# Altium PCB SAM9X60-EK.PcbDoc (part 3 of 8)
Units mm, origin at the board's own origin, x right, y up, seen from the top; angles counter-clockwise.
Board outline 150 x 125 mm, 4 copper layers (L1 - Top Layer, L2 - GND, L3 - PWR, L4 - Bottom Layer), stack 1.52 mm thick; 566 components, 500 nets, 2132 pads, 1038 vias.

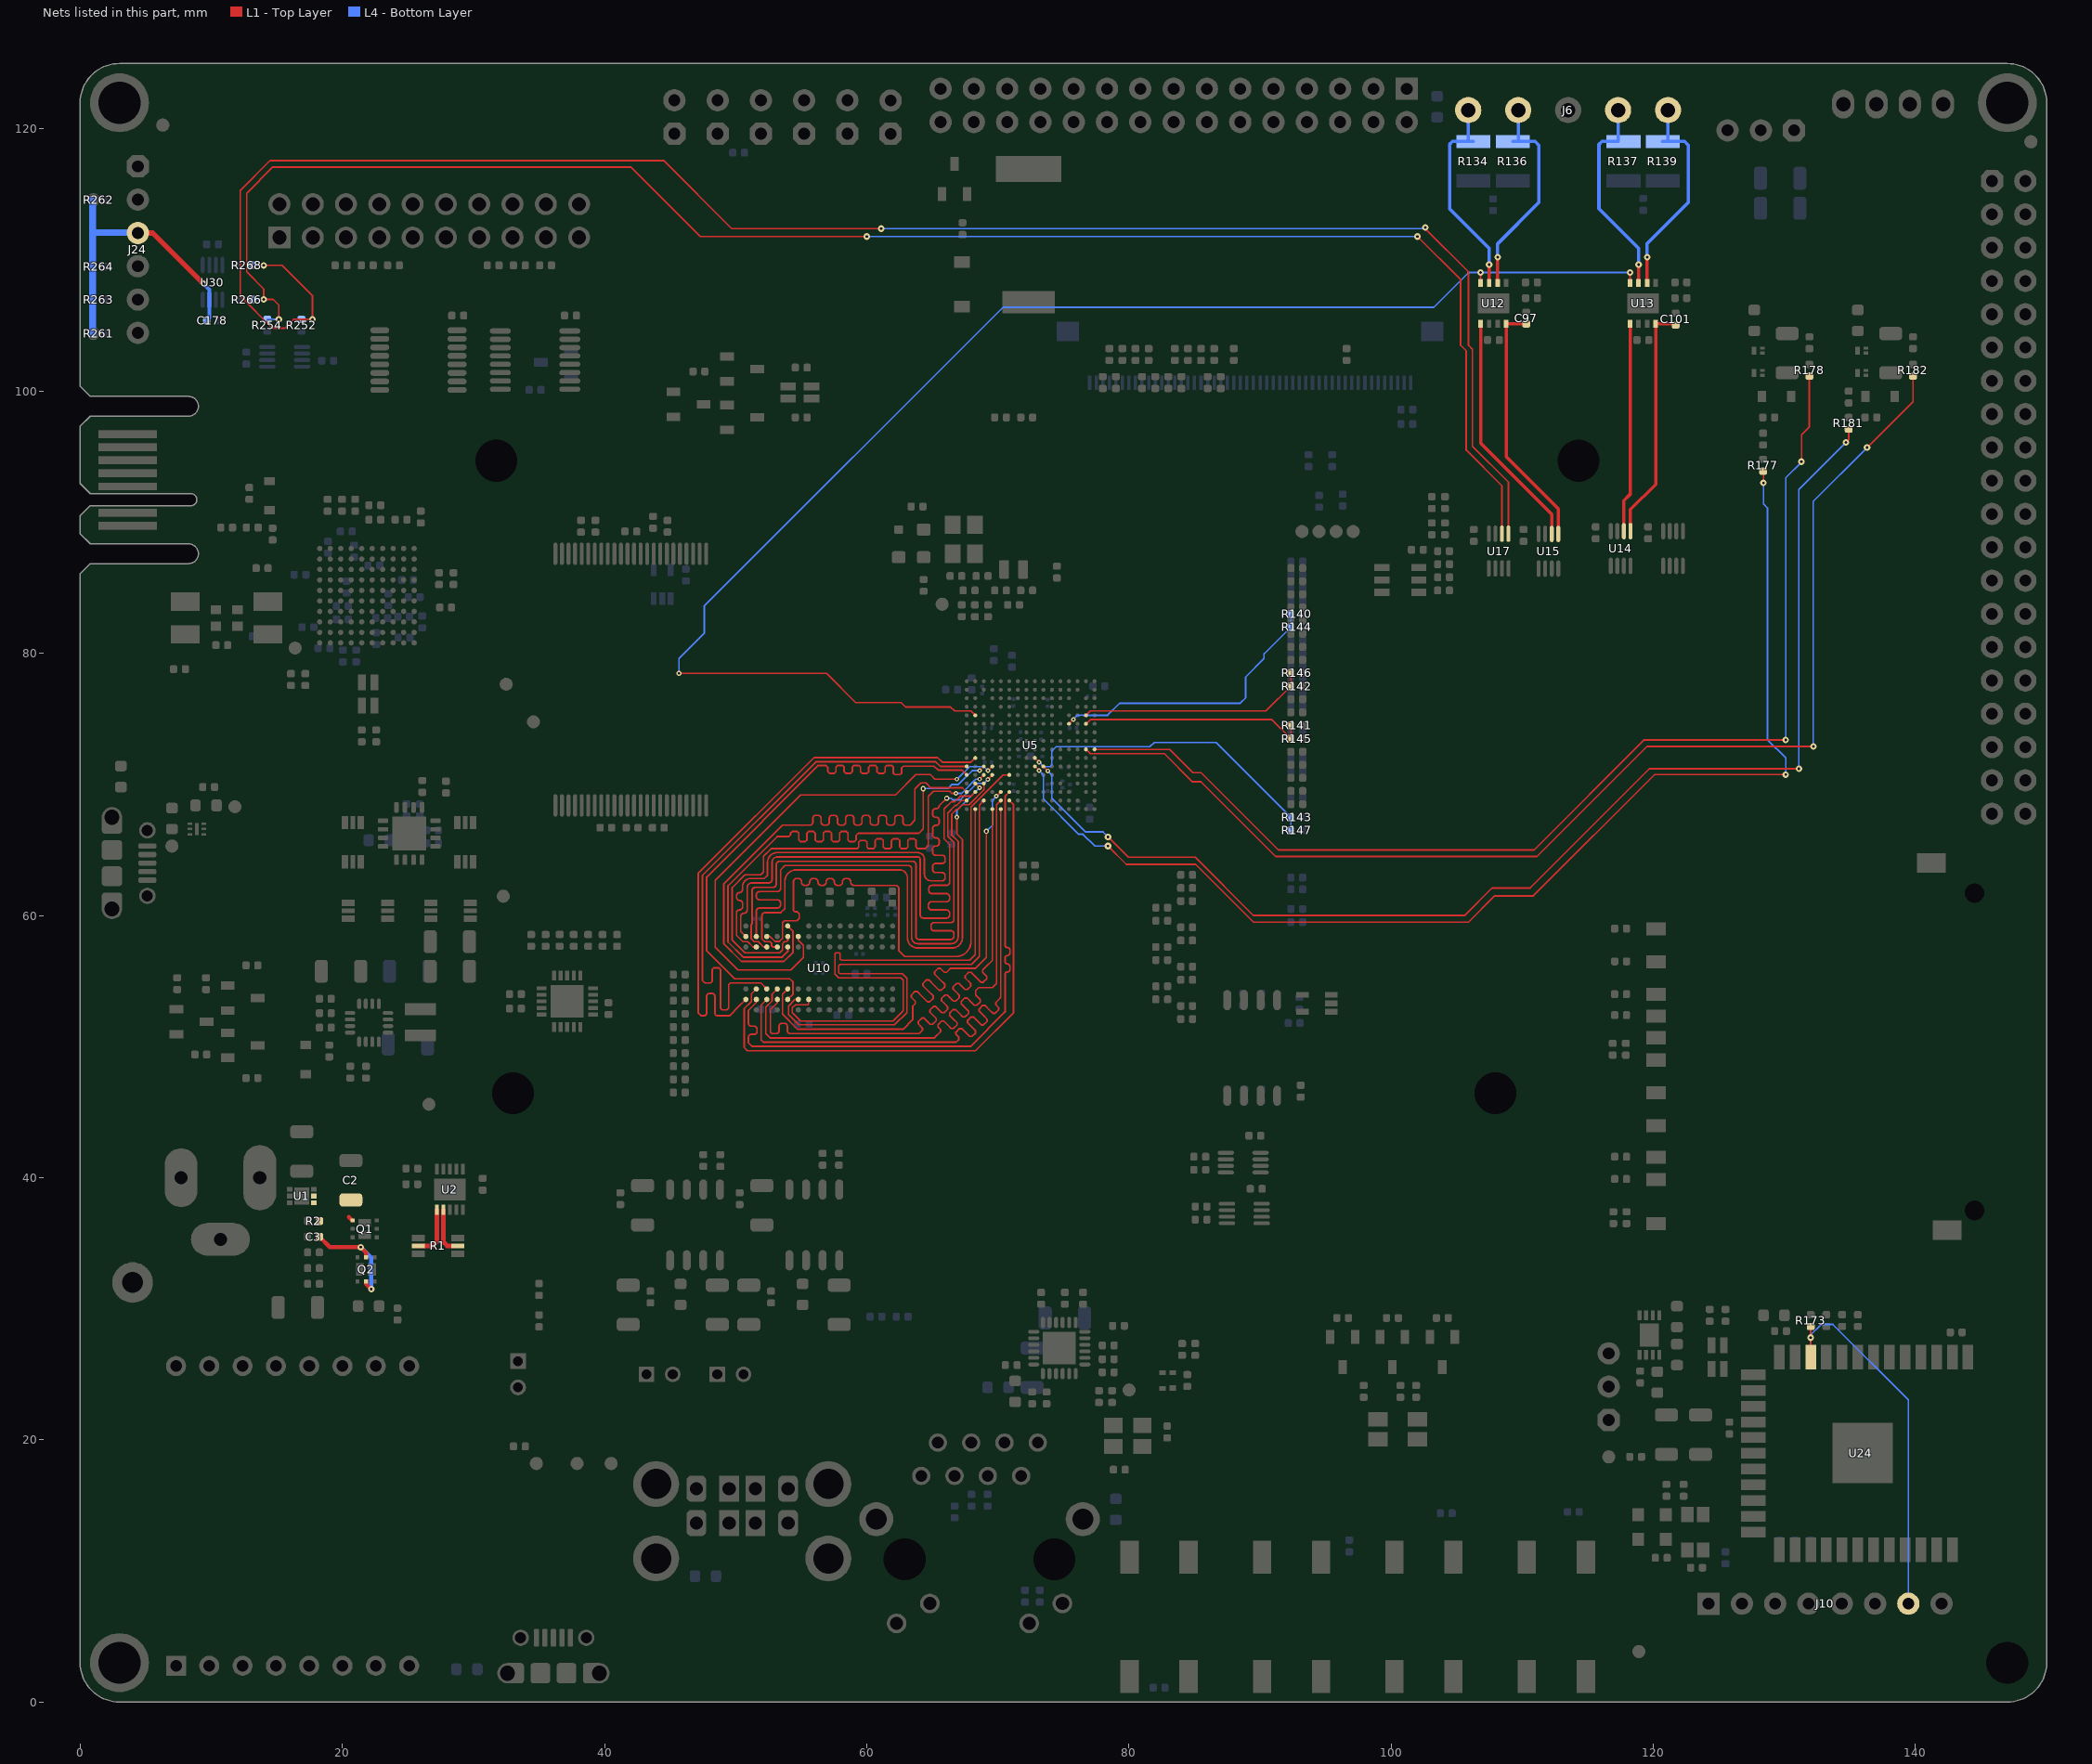
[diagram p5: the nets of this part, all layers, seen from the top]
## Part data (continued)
J12: library part CON0005, Current=6A, Manufacturer 1="Phoenix Contact", Manufacturer 2="Degson Electronics Co., Ltd.", Manufacturer Part Number 1=1725672, Manufacturer Part Number 2=DG308-2.54-04P-14-00A(H), Supplier Part Number 1=277-1275-ND, Voltage=63V
J14: library part SKT1042, Manufacturer 1="Sullins Connector Solutions", Manufacturer 2=Nextron, Manufacturer Part Number 1=PPTC081LFBN-RC, Manufacturer Part Number 2=R-212-0810-0071-000, Package="mikroBUS HOST", Supplier Part Number 1=S7006-ND
J15: library part CON1372, Current=0.5A, Manufacturer 1="Omron Electronics Inc-EMC Div", Manufacturer Part Number 1=XF2M-5015-1A, Supplier Part Number 1=OR732CT-ND
J16: library part CON0153, Manufacturer 1=Samtec, Manufacturer Part Number 1=TSW-120-07-G-D, Manufacturer Part Number 2=TSW-120-07-S-D
J17: library part CON1580, Manufacturer 1="Wurth Electronics Inc.", Manufacturer Part Number 1=61303021121, Supplier Part Number 1=732-5306-ND
J18: library part CON1674, "CON_PCB_MEC1-108-02-F-D-RA1-SL", Current=1.6A, Manufacturer 1="Samtec Inc.", Manufacturer Part Number 1=MEC1-108-02-F-D-RA1-SL, Supplier Part Number 1=SAM11473-ND
J23: library part CON1883, Current=3A, Manufacturer 1="On Shore Technology Inc.", Manufacturer Part Number 1=302-R201, Supplier Part Number 1=ED10536-ND, Voltage="HDR-2.54 Male 2x10"
J24: library part CON1106, Manufacturer 1=FCI, Manufacturer 3="Samtec Inc", Manufacturer 4=Nextron, Manufacturer Part Number 1=68000-106HLF, Manufacturer Part Number 2=68001-106HLF, Manufacturer Part Number 3=TSW-106-07-G-S, Manufacturer Part Number 4=R-211-0611-0021-400, Supplier Part Number 1=609-3249-ND
L1: library part IND1348, Manufacturer 1=TDK, Manufacturer 2="TDK Corporation", Manufacturer Part Number 1=MLP2520H2R2MT0S1, Operating Temperature="-40C to +125C", Package=1008, RMS Current=1.3A, Supplier Part Number 1=810-MLP2520H2R2MT0S1, Test Frequency=2MHz
LABEL1: library part 08-00126
LCD1: library part DISPLAY0025, Manufacturer 1="PDA INC", Manufacturer Part Number 1=TM5000B, Operating Temperature="0C to +70C", Voltage=5V
LD1: library part DIODE1214, Forward Current="20mA, 20mA, 20mA", Manufacturer 1="Cree Inc", Manufacturer 2="Cree Inc.", Manufacturer Part Number 1=CLV1A-FKB-CK1N1G1BB7R4S3, Manufacturer Part Number 2=CLV1A-FKB-CK1VW1DE1BB7C3C3, Operating Temperature="-40C - +100C", Package=4-PLCC, Power="130mW, 100mW, 100mW", Reverse Current=10uA, Reverse Voltage=5V, Supplier Part Number 1=CLV1A-FKB-CK1N1G1BB7R4S3CT-ND
PAD1 PAD2 PAD3 PAD4: library part MECH0185, Manufacturer 1="Essentra Components", Manufacturer Part Number 1=RBS-35, Supplier Part Number 1=RPC1620-ND
Q1 Q2: library part TRA1245, Current=-4.5A, Drain to Source Voltage=-20V, Gate to Source Voltage=900mV, Manufacturer 1="Vishay Siliconix", Operating Temperature="-55C to +150C", Package=SC70-6L, Power=7.8W, Supplier Part Number 1=SIA923AEDJ-T1-GE3CT-ND
Q3 Q4 Q5 Q10 Q11 Q12 Q13 Q14 Q15: library part MIC7420, "Transistor MOS", Manufacturer 1="Microchip Technology", Manufacturer Part Number 1=TN2106K1-G
Q6 Q8: library part TRA1229, "Transistor MOS", Current=1.4A, Drain to Source Voltage=20V, Gate to Source Voltage=8V, Manufacturer 1="Toshiba Semiconductor and Storage", Manufacturer Part Number 1=SSM3J56ACT,L3F, Operating Temperature="-55C to +150C", Package=SOT-883, Power=0.5W, Supplier Part Number 1=SSM3J56ACTL3FCT-ND
Q7 Q9: library part TRA1230, "Transistor MOS", Current=1.4A, Drain to Source Voltage=20V, Gate to Source Voltage=4.5V, Manufacturer 1="Toshiba Semiconductor and Storage", Manufacturer Part Number 1=SSM3K56ACT,L3F, Operating Temperature="-55C to +150C", Package=SOT-883, Power=0.5W, Supplier Part Number 1=SSM3K56ACTL3FCT-ND
Q16: library part TRA1223, "Transistor MOS", Current=230mA, Drain to Source Voltage=60V, Gate to Source Voltage=20V, Manufacturer 1="Infineon Technologies", Manufacturer Part Number 1=BSS138NH6327XTSA2, Operating Temperature="-55C to +150C", Package=SOT23-3, Power=0.36W, Supplier Part Number 1=BSS138NH6327XTSA2CT-ND
R1: library part RSMT1231, "Shunt", Current=5A, Manufacturer 1=Yageo, Manufacturer Part Number 1=PF1206FRF070R01L, Operating Temperature="-55C to +155C", Package=1206, Power=0.25W, Supplier Part Number 1=311-0.01AJCT-ND, Temperature Coeffcient=100ppm/C, Tolerance=1%, Voltage=50mV
R2 R3 R5 R15 R16 R17 R29 R34 R35 R36 R37 R47 R48 R49 R148 R162 R163 R164 R165 R166 R167 R189 R194 R204 R245 R256 R257 R258 R259 R260 R261 R262 R263 R264 R270: library part RES2196, Manufacturer 1=Yageo, Manufacturer Part Number 1=RC0402JR-07100KL, Package=0402, Power=1/16W, Supplier Part Number 1=311-100KJRCT-ND, Temperature Coeffcient=100ppm/C, Tolerance=5%
R4 R12 R13 R19 R33 R97 R98 R99 R100 R101 R102 R103 R104 R105 R106 R107 R108 R109 R110 R111 R112 R113 R114 R115 R116 R117 R118 R127 R129 R152 R153 R154 R155 R168 R176 R179 R180 R183 R186 R196 R202 R207 R232 R237 R241 R250: library part RSMT0439, Manufacturer 1=Vishay, Manufacturer 2=Yageo, Manufacturer Part Number 1=CRCW040210K0JNED, Manufacturer Part Number 2=RC0402JR-0710KL, Operating Temperature="-55C to +155C", Package=0402, Power=1/16W, Supplier Part Number 1=541-10KJCT-ND, Temperature Coeffcient=100ppm/C, Tolerance=5%, Voltage=50V
R6 R20 R185 R190 R191 R192 R195 R197 R200 R206 R234 R235 R238 R265: library part RES1587, Manufacturer 1=Yageo, Manufacturer Part Number 1=RC0402FR-07100RL, Operating Temperature="-55C to +155C", Package=0402, Power=1/16W, Supplier Part Number 1=311-100LRCT-ND, Temperature Coeffcient=100ppm/C, Tolerance=1%, Voltage=50V
R7 R8 R9 R10: library part RSMT1231, "Shunt", Current=5A, Manufacturer 1=Yageo, Manufacturer Part Number 1=PF1206FRF070R01L, Operating Temperature="-55C to +155C", Package=1206, Power=1/4W, Supplier Part Number 1=311-0.01AJCT-ND, Temperature Coeffcient=100ppm/C, Tolerance=1%, Voltage=50mV
R11 R119: library part RSMT1238, Current=1A, Manufacturer 1=Yageo, Manufacturer Part Number 1=RC0402FR-0720KL, Operating Temperature="-55C to +155C", Package=0402, Power=1/16, Supplier Part Number 1=311-20.0KLRCT-ND, Temperature Coeffcient=100ppm/C, Tolerance=1%, Voltage=100V
R14: library part RSMT0440, Manufacturer 1=Yageo, Manufacturer Part Number 1=9C06031A8451FKHFT, Operating Temperature="-55C to +155C", Package=0603, Power=1/10W, Supplier Part Number 1=311-8.45KHCT-ND, Temperature Coeffcient=100ppm/C, Tolerance=1%, Voltage=50V
R18 R122 R123 R160 R161 R187 R188 R199 R201 R246 R249: library part RSMT0316, Manufacturer 1=Panasonic, Manufacturer Part Number 1=ERJ-2GEJ102X, Operating Temperature="-55C to +155C", Package=0402, Power=1/16W, Supplier Part Number 1=P1.0KJCT-ND, Temperature Coeffcient=200ppm/C, Tolerance=5%, Voltage=50V
R21 R24: library part RES1019, Manufacturer 1=Yageo, Manufacturer Part Number 1=RC0402JR-071ML, Operating Temperature="-55C to +155C", Package=0402, Power=1/16W, Supplier Part Number 1=311-1.0MJRCT-ND, Temperature Coeffcient=100ppm/C, Tolerance=5%, Voltage=50V
R22 R26 R27 R28 R30 R60 R63 R65 R66 R91 R126 R128 R130 R131 R133 R135 R138 R169 R170 R171 R173 R174 R177 R178 R181 R182 R208 R209 R210 R211 R214 R217 R233 R239: library part RSMT1040, Manufacturer 1=Yageo, Manufacturer Part Number 1=RC0402JR-070RL, Operating Temperature="-55C to +155C", Package=0402, Power=1/16W, Supplier Part Number 1=311-0.0JRCT-ND
R23: library part RES1505, Manufacturer 1="Vishay Dale", Manufacturer Part Number 1=CRCW04025K62FKED, Operating Temperature="-55C to +155C", Package=0402, Power=1/16W, Supplier Part Number 1=541-5.62KLTR-ND, Temperature Coeffcient=100ppm/C, Tolerance=1%, Voltage=50V
R25: library part RES2180, Manufacturer 1="Vishay Dale", Manufacturer Part Number 1=CRCW020110R0FNED, Operating Temperature="-55C to +155C", Package=0201, Power=1/20W, Supplier Part Number 1=541-10.0ABCT-ND, Temperature Coeffcient=200ppm/C, Tolerance=1%
R31 R32 R38 R39 R40 R41 R42 R43 R44 R45 R46 R50 R51 R52 R53 R54 R55 R56 R57 R58 R59 R64 R67 R68 R69 R70 R71 R72 R73 R74 R75 R76 R77 R78 R79 R80 R81 R82 R85 R86 R87 R88 R89 R90 R92 R93 R94 R95 R96 R140 R141 R142 R143 R144 R145 R146 R147 R156 R157 R158 R159 R212 R213 R215 R216 R218 R219 R220 R221 R222 R223 R224 R225 R226 R227 R228 R229 R230 R231 R252 R254 R266 R268: library part RES1474, Manufacturer 1="Panasonic Electronic Components", Manufacturer Part Number 1=ERJ-2RKF22R0X, Operating Temperature="-55C to +155C", Package=0402, Power=1/10W, Supplier Part Number 1=P22.0LCT-ND, Temperature Coeffcient=100ppm/C, Tolerance=1%
R61 R62 R83 R84 R203: library part RES1020, Manufacturer 1="Vishay Dale", Manufacturer Part Number 1=CRCW04022K20JNED, Operating Temperature="-55C to +155C", Package=0402, Power=1/16W, Supplier Part Number 1=541-2.2KJCT-ND, Temperature Coeffcient=200ppm/C, Tolerance=5%, Voltage=50V
R120 R121: library part RES1519, Manufacturer 1="Panasonic Electronic Components", Manufacturer Part Number 1=ERJ-1GEF4701C, Operating Temperature="-55C to +125C", Package=0201, Power=1/20W, Supplier Part Number 1=P4.70KABTR-ND, Temperature Coeffcient=200ppm/C, Tolerance=1%, Voltage=25V
R124: library part RES1731, Manufacturer 1=Yageo, Manufacturer Part Number 1=RC0402FR-076K49L, Operating Temperature="-55C to +155C", Package=0402, Power=1/16W, Supplier Part Number 1=311-6.49KLRCT-ND, Temperature Coeffcient=100ppm/C, Tolerance=1%, Voltage=50V
R125: library part RSMT1037, Manufacturer 1=Yageo, Manufacturer Part Number 1=RC0402JR-07470RL, Operating Temperature="-55C to +155C", Package=0402, Power=1/16W, Supplier Part Number 1=311-470JRCT-ND, Temperature Coeffcient=100ppm/C, Tolerance=5%, Voltage=50V
R132 R149 R172 R175 R251: library part RSMT1243, Current=1A, Manufacturer 1=Yageo, Manufacturer Part Number 1=RC0402FR-0751RL, Operating Temperature="-55C to +155C", Package=0402, Power=1/16W, Supplier Part Number 1=311-51.0LRCT-ND, Temperature Coeffcient=100ppm/C, Tolerance=1%, Voltage=100V
R134 R136 R137 R139: library part RSMT1222, Current=5.56A, Manufacturer 1=Yageo, Manufacturer Part Number 1=RC1210FR-0762RL, Operating Temperature="-55C to +155C", Package=1210, Power=1/2W, Supplier Part Number 1=603-RC1210FR-0762RL, Temperature Coeffcient=100PPM/C, Tolerance=1%, Voltage=200V
R150: library part RES1424, Manufacturer 1=Panasonic, Manufacturer Part Number 1=ERJ-2RKF2003X, Operating Temperature="-55C to +125C", Package=0402, Power=1/10W, Supplier Part Number 1=P200KLCT-ND, Temperature Coeffcient=100ppm/C, Tolerance=1%, Voltage=50V
R236 R242 R243 R244: library part RSMT1167, Manufacturer 1="Vishay Dale", Manufacturer Part Number 1=CRCW0402150RFKED, Supplier Part Number 1=541-150LCT-ND
R240: library part RSMT1211, Manufacturer 1="Vishay Dale", Manufacturer Part Number 1=CRCW04026K80FKED, Operating Temperature="-55C to +155C", Package=0402, Power=1/16W, Supplier Part Number 1=541-6.80KLCT-ND, Temperature Coeffcient=100ppm/C, Tolerance=1%, Voltage=50V
R247 R248: library part RES1800, Manufacturer 1=Yageo, Manufacturer 2=Digi-Key, Manufacturer Part Number 1=RC0402FR-0739RL, Manufacturer Part Number 2=311-39.0LRCT-ND, Operating Temperature="-55°C ~ 155°C", Package=0402, Power=1/16W, Tolerance=1%
SW1 SW2 SW3 SW4: library part SWITCH0003, "Switch", Current=50mA, Manufacturer 1=E-Switch, Manufacturer 4=OMRON, Manufacturer 8="Switech Electronics Co. Ltd", Manufacturer Part Number 1=TL3301NF260QG/TR, Manufacturer Part Number 2=TL3301NF260QG, Manufacturer Part Number 3=TL3301NF160QG/TR, Manufacturer Part Number 4=B3S-1000P, Manufacturer Part Number 5=B3S-1000, Manufacturer Part Number 6=B3S-1002P, Manufacturer Part Number 7=B3S-1002, Manufacturer Part Number 8=TS2A-043C-G9, Operating Temperature="-20C to +70C", Supplier Part Number 1=EG1868CT-ND, Voltage=12V
TP1: library part MISC0025, "Test Point", Manufacturer 1=Keystone, Manufacturer Part Number 1=5011, Supplier Part Number 1=36-5011-ND
TP2 TP4 TP5 TP6 TP7 TP8 TP9 TP10 TP11 VBUS_JLINK VBUS_USBA VBUS_USBB VBUS_USBC VDD_3V3 VDD_3V3_3U VDD_MAIN_5V VDD_WILC VDDCORE VDDIOM: library part TEST-POINT, "Test Point pad 1.00mm"
U1: library part IC1481, Manufacturer 1="ON Semiconductor", Manufacturer Part Number 1=NCP349MNAETBG, Operating Temperature="-40C to 85C", Package=DFN-6, Supplier Part Number 1=NCP349MNAETBGOSCT-ND
U2: library part MIC6142, Manufacturer 1="Microchip Technology", Manufacturer Part Number 1=PAC1710-1-AIA-TR, Supplier Part Number 1=PAC1710-1-AIA-CT-ND
U3: library part MIC7858, Manufacturer 1="Microchip Technology", Manufacturer Part Number 1=MIC2800-G8SYML, Supplier Part Number 1=MIC2800-G8SYML-TRCT-ND
U4: library part MIC7010, Manufacturer 1="Microchip Technology", Manufacturer Part Number 1=PAC1934-I/JQ
U5: library part MIC8772, "SAM9X60 MPU 600MHz ARM926EJ-S TFBGA-228", Manufacturer 1=Microchip, Manufacturer Part Number 1=SAM9X60-V/DWB, PackageType=TFBGA, PackageWidth=11x11x1.2mm, TempRange=Various
U6: library part MIC2806, "I/O Expander", IOVoltageTolerant=VDD, Manufacturer 1=Microchip, Manufacturer Part Number 1=MCP23008T-E/ML, Manufacturer Part Number 2=MCP23008-E/ML, OperatingVoltageMax=5.5, OperatingVoltageMin=1.8, PackageType=QFN, PackageWidth=4x4x0.9mm, PinCurrent=25, TempRange="-40C to +125C", TotalCurrent=160
U7: library part MIC7407, Manufacturer 1="Microchip Technology", Manufacturer Part Number 1=24AA025E48T-I/OT, MaxClockFreq="400 kHz", OpVoltMax=5.5, OpVoltMin=1.7, PackageType=SOT-23, Supplier Part Number 1=24AA025E48T-I/OTCT-ND, TempRange="-40C to +85C"
U8: library part MIC6216, "SQI Serial Flash", Manufacturer 1="Microchip Technology", Manufacturer Part Number 1=SST26VF064B-104I/SM, MaxClockFreq="104 MHz", OpVoltMax=3,6, OpVoltMin=2,3, PackageType=SOIJ, PackageWidth=.208in, TempRange="-40C to +85C"
U9: library part IC1477, Manufacturer 1="Micron Technology Inc.", Manufacturer Part Number 1="MT29F4G08ABAEAWP:E TR", Operating Temperature="0C to +70C", Package=TSOP-48, Supplier Part Number 1=557-1674-1-ND
U10: library part IC1476, "2Gb DDR2-800 SDRAM, 128Mb x 16", Manufacturer 1="Winbond Electronics", Manufacturer Part Number 1=W972GG6KB-25, Operating Temperature="0C to +85C", Package=WBGA-84
U11: library part MIC7404, Manufacturer 1="Microchip Technology", Manufacturer Part Number 1=KSZ8081RNAIA-TR, Supplier Part Number 1=576-4174-1-ND
U12 U13: library part MIC7856, Manufacturer 1="Microchip Technology", Manufacturer Part Number 1=MCP2542FDT-E/MF, OperatingCurrentMax=10, OperatingVoltageMax=5.5, OperatingVoltageMin=4.5, PackageType=DFN, PackageWidth=3x3x0.9mm, StandbyCurrentMax=15, Supplier Part Number 1=MCP2542FDT-E/MFCT-ND, TempRange="-40C to +125C", TransientVoltage="-150 to +100"
U14 U15 U21: library part IC1512, "BUFFER DL TRI-ST NON-INV", Manufacturer 1="ON Semiconductor", Manufacturer Part Number 1=NL27WZ125USG, Operating Temperature="-55C to +125C", Package=US-8, Supplier Part Number 1=NL27WZ125USGOSCT-ND
U16 U17 U23: library part IC1514, "BUFFER DL TRI-ST NON-INV", Manufacturer 1="ON Semiconductor", Manufacturer Part Number 1=NL27WZ126USG, Operating Temperature="-55C to +125C", Package=US-8, Supplier Part Number 1=NL27WZ126USGOSCT-ND
U19 U20: library part MIC7234, Manufacturer 1="Microchip Technology", Supplier Part Number 1=576-1057-ND
U22: library part MIC2599, "LDO", Manufacturer 1=Microchip, Manufacturer Part Number 1=MCP1725T-3302E/MC, Manufacturer Part Number 2=MCP1725-3302E/MC, PackageType=DFN, PackageWidth=2x3x0.9mm, TempRange="-40C to +125C"
U24: library part MIC7405, FrequencyRange="2.412-2.472 MHz", Manufacturer 1="Microchip Technology", Manufacturer Part Number 1=ATWILC3000-MR110CA, PowerRX="84mA (802.11n MCS7)", PowerTX="253mA (802.11n MCS7)", RfPower=0, Supplier Part Number 1=ATWILC3000-MR110CA-ND
U25 U26: library part IC1252, "Single  Non-Inverting 3-State  buffer", Manufacturer 1="Diodes Incorporated", Manufacturer Part Number 1=74AHC1G126SE-7, Operating Temperature="-40°C ~ 125°C", Package=SC-70-5, Supplier Part Number 1=621-74AHC1G126SE-7
U27: library part MIC7470, Manufacturer 1="Microchip Technology", Manufacturer Part Number 1=ATSAM3U4CA-CU, PackageType=TFBGA, PackageWidth=9x9x1.2mm, Supplier Part Number 1=ATSAM3U4CA-CU-ND, TempRange="-40C to +85C"
U28: library part MIC6905, Manufacturer 1="Microchip Technology", Manufacturer Part Number 1=MIC5528-3.3YMT-TR, PackageType=UDFN, PackageWidth=1.2x1.2x0.6mm, Supplier Part Number 1=576-4766-1-ND, TempRange="-40C to +125C"
U29 U30: library part IC1128, "Level Shifter", Manufacturer 1="Texas Instruments", Manufacturer Part Number 1=TXS0102DCUR, Operating Temperature="-40C to +85C", Package=US-8, Supplier Part Number 1=296-21931-1-ND
U31: library part IC1517, Manufacturer 1="IDT, Integrated Device Technology Inc", Manufacturer Part Number 1=QS3VH257PAG, Operating Temperature="-40C to +85C", Package=TSSOP-16, Supplier Part Number 1=800-2205-ND
U32: library part IC1516, Manufacturer 1="IDT, Integrated Device Technology Inc", Manufacturer Part Number 1=QS3VH125QG, Operating Temperature="-40C to +85C", Package=QSOP-16, Supplier Part Number 1=800-2199-ND
Y1: library part OSC1047, "Crystal", Load Capacitance=18pF, Manufacturer 1="Abracon Corporation", Manufacturer Part Number 1=ABM8G-24.000MHZ-18-D2Y-T, Package=ABM8G, Supplier Part Number 1=535-10273-1-ND
Y2: library part OSC1063, "Crystal", Manufacturer 1="Abracon LLC", Manufacturer Part Number 1=ABS06-32.768KHZ-T, Supplier Part Number 1=535-10104-1-ND
Y3: library part MIC7861, Manufacturer 1="Microchip Technology", Manufacturer Part Number 1=DSC1001CI5-024.0000, Supplier Part Number 1=576-4617-ND
Y5: library part OSC1159, "Crystal", Load Capacitance=20pF, Manufacturer 1="ECS Inc.", Manufacturer Part Number 1=ECS-250-20-33-CKM-TR, Operating Temperature="-20C to +70C", Package=L3.2W2.5H0.8, Supplier Part Number 1=XC1817CT-ND, Tolerance=10ppm
Y6: library part MIC8785, Manufacturer 1="Microchip Technology Inc", Manufacturer Part Number 1=DSC6102HI2B-025.000
Y7: library part OSC1187, Manufacturer 1="Abracon LLC", Manufacturer Part Number 1=ASH7KW-32.768KHZ-L-T, Operating Temperature="-40C to +85C", Package=DFN-4, Supplier Part Number 1=535-12059-1-ND, Supply Current=1.8uA, Tolerance=20ppm, Voltage=1.2-5.5V
Y8: library part MIC7476, Manufacturer 1="Microchip Technology", Manufacturer Part Number 1=DSC6083CE2A-032K768, Supplier Part Number 1=DSC6083CE2A-032K768-ND
Y9: library part OSC1155, "Crystal", Load Capacitance=16pF, Manufacturer 1="IQD Frequency Products", Manufacturer Part Number 1=LFXTAL026384Reel, Operating Temperature="-20C to +70C", Package="7.5mm X 5mm", Supplier Part Number 1=449-LFXTAL026384REEL, Supply Current=-, Tolerance=30ppm
Y10: library part MIC7210, Manufacturer 1="Microchip Technology Inc", Manufacturer Part Number 1=DSC6011JI1A-012.0000

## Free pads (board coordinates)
  round 4.5 hole 3.2 unplated mask+0.2: 0(3,3) 0(3,122) 0(147,122)
  round 0 hole 3.2 unplated mask+0.2: 0(147,3)
  round 1 smd paste-1 mask+0.5: 1.00mm(6.3,120.3) 1.00mm(118.9,3.85) 1.00mm(148.8,119.025)
  round 1 smd far side paste-1 mask+0.5: 1.00mm(6.3,120.3) 1.00mm(118.9,3.85) 1.00mm(148.8,119.025)

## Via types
v1: diameter 0.5, hole 0.2, L1 - Top Layer to L4 - Bottom Layer, tented both sides, 483 vias
v2: diameter 0.5, hole 0.2, L1 - Top Layer to L4 - Bottom Layer, 268 vias
v3: diameter 0.4, hole 0.2, L1 - Top Layer to L4 - Bottom Layer, tented both sides, 145 vias
v4: diameter 0.35, hole 0.15, L1 - Top Layer to L4 - Bottom Layer, tented both sides, 121 vias
v5: diameter 0.55, hole 0.3, L1 - Top Layer to L4 - Bottom Layer, tented bottom, 16 vias
v6: diameter 0.559, hole 0.305, L1 - Top Layer to L4 - Bottom Layer, 5 vias

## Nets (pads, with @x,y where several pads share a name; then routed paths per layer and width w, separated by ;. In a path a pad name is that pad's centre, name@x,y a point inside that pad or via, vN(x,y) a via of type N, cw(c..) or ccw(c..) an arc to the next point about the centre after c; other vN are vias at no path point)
5V_FTDI: C178.2 J24.3 R261.1 R262.1 R263.2 R264.2 U30.7 | length 23.3
  L1 - Top Layer w0.4: J24.3@4.4,112.07 5.53,112.07 v1(9.4,108.2)
  L4 - Bottom Layer w0.3: v1(9.4,108.2) 9.85,107.75 U30.7@9.85,106.975 9.85,105.6 C178.2@9.65,105.4
  L4 - Bottom Layer w0.5: R261.1@0.95,104.4 R263.2@0.95,107 R264.2@0.95,109.5 0.95,112.1 ; R262.1@0.95,114.6 0.95,112.1 ; J24.3@4.4,112.07 4.37,112.1 0.95,112.1
5V_N: R1.4 U2.2 | length 3.3
  L1 - Top Layer w0.35: U2.2@27.7,37.55 27.7,35.1 28,34.8 R1.4@28.4,34.8
5V_P: R1.3 U2.1 | length 4
  L1 - Top Layer w0.35: R1.3@25.8,34.8 26.9,34.8 27.2,35.1 U2.1@27.2,37.55
CAN0_H: J6.1 R134.2 U12.7 | length 16.1
  L1 - Top Layer w0.25: U12.7@107.475,108.25 v2(107.475,109.65)
  L4 - Bottom Layer w0.25: J6.1@105.88,121.444 R134.2@105.88,119.05 ; R134.2@106.275,119.05 R134.2@105.88,119.05 ; v2(107.475,109.65) 107.475,110.9 104.45,113.925 104.45,118.825 104.675,119.05 R134.2@105.88,119.05
CAN0_L: J6.2 R136.1 U12.6 | length 16.3
  L1 - Top Layer w0.25: U12.6@108.125,108.25 v2(108.125,110.225)
  L4 - Bottom Layer w0.25: v2(108.125,110.225) 108.125,111.25 111.25,114.375 111.25,118.775 110.975,119.05 R136.1@109.275,119.05 ; R136.1@109.69,119.05 J6.2@109.69,121.444
CAN0_RX: C97.2 U12.4 U15.5 | length 19.2
  L1 - Top Layer w0.25: C97.2@110.3,105.125 110.275,105.15 U12.4@108.775,105.15 108.775,95 112.75,91.025 U15.5@112.75,89.115
CAN0_TX: U12.1 U15.6 | length 18.3
  L1 - Top Layer w0.25: U12.1@106.825,105.15 106.825,96.025 112.25,90.6 U15.6@112.25,89.115
CAN1_H: J6.4 R137.2 U13.7 | length 15.7
  L1 - Top Layer w0.25: U13.7@118.875,108.25 v2(118.875,109.65)
  L4 - Bottom Layer w0.25: R137.2@117.28,119.05 116.075,119.05 115.85,118.825 115.85,113.925 118.875,110.9 v2(118.875,109.65) ; R137.2@117.31,119.05 J6.4@117.31,121.444
CAN1_L: J6.5 R139.1 U13.6 | length 16.3
  L1 - Top Layer w0.25: U13.6@119.525,108.25 v2(119.525,110.225)
  L4 - Bottom Layer w0.25: v2(119.525,110.225) 119.525,111.25 122.65,114.375 122.65,118.775 122.375,119.05 R139.1@120.675,119.05 ; R139.1@121.12,119.05 J6.5@121.12,121.444
CAN1_RX: C101.2 U13.4 U14.5 | length 18.2
  L1 - Top Layer w0.25: U14.5@118.25,89.325 118.25,90.975 120.175,92.9 U13.4@120.175,105.15 121.6,105.15 C101.2@121.7,105.05
CAN1_TX: U13.1 U14.6 | length 16
  L1 - Top Layer w0.25: U14.6@117.75,89.325 117.75,91.65 118.225,92.125 U13.1@118.225,105.15
CAN/DBGU_RX_PA09: R143.2 R147.2 U5.G8 | length 24.5
  L1 - Top Layer w0.125: U5.G8@72.825,72.025 v4(73.15,71.7)
  L4 - Bottom Layer w0.1: v4(73.15,71.7) 73.475,71.375 74,71.375 74.125,71.5 74.125,72.55 ; 74.45,72.875 81.6,72.875 81.925,73.2
  L4 - Bottom Layer w0.125: 74.125,72.55 74.45,72.875 ; 81.925,73.2 86.65,73.2 R143.2@92.35,67.5 R147.2@92.35,66.5
CAN/DBGU_TX_PA10: R141.2 R145.2 U5.L2 | length 17.4
  L1 - Top Layer w0.125: U5.L2@76.725,74.625 77.047,74.947 90.903,74.947 R145.2@92.35,73.5 R141.2@92.35,74.5
CAN/FLEXCOM_RX_PA06: R142.2 R146.2 U5.M2 | length 17.5
  L1 - Top Layer w0.125: U5.M2@76.725,75.275 77.05,75.6 90.45,75.6 R142.2@92.35,77.5 R146.2@92.35,78.5
CAN/FLEXCOM_TX_PA05: R140.2 R144.2 U5.L4 | length 22.2
  L1 - Top Layer w0.125: U5.L4@75.425,74.625 v4(75.75,74.95)
  L4 - Bottom Layer w0.1: 76.275,75.275 76.491,75.275
  L4 - Bottom Layer w0.125: v4(75.75,74.95) 76.075,75.275 76.275,75.275 ; 76.491,75.275 78.375,75.275 79.3,76.2 88.5,76.2 88.9,76.6 88.9,78.2 90.3,79.6 90.3,80 90.35,80 R144.2@92.35,82 R140.2@92.35,83
CAN_STBY_PD21: U5.M15 U12.8 U13.8 | length 112.6
  L1 - Top Layer w0.125: v3(45.675,78.475) 56.925,78.475 59.15,76.25 62.625,76.25 62.975,75.9 66.4,75.9 66.7,75.6 67.95,75.6 U5.M15@68.275,75.275 ; U12.8@106.825,108.25 v2(106.825,109.05) ; U13.8@118.225,108.25 v2(118.225,109.05)
  L4 - Bottom Layer w0.125: v3(45.675,78.475) 45.675,79.6 47.6,81.525 47.6,83.6 70.4,106.4 103.25,106.4 105.9,109.05 v2(106.825,109.05) v2(118.225,109.05)
CLASSD_L0_PA24: R177.1 U5.F8 | length 91.7
  L1 - Top Layer w0.125: U5.F8@72.825,71.375 72.829,71.375 v4(73.143,71.061) ; v1(78.4,65.3) 79.8,63.9 85.1,63.9 89.5,59.5 105.9,59.5 107.9,61.5 110.849,61.5 120.098,70.749 v2(130.1,70.749) ; R177.1@128.375,93.9 128.4,93.875 v2(128.4,93)
  L4 - Bottom Layer w0.1: 73.475,68.9 73.475,70.729
  L4 - Bottom Layer w0.125: v4(73.143,71.061) 73.475,70.729 ; 73.475,68.9 76.175,66.2 76.5,66.2 77.4,65.3 v1(78.4,65.3) ; v2@128.5,92.9 128.4,92.8 128.4,91.4 128.7,91.1 128.7,73.425 130.1,72.025 v2(130.1,70.749)
CLASSD_L1_PA25: R178.1 U5.H1 | length 87.9
  L1 - Top Layer w0.125: U5.H1@77.375,72.675 83.1,72.675 84.875,70.9 85.5,70.9 91.4,65 110.9,65 119.3,73.4 v2(130.1,73.4) ; v2(131.3,94.625) 131.3,96.675 131.9,97.275 R178.1@131.9,101.15
  L4 - Bottom Layer w0.125: v2(130.1,73.4) 130.1,93.4 131.3,94.6 v2(131.3,94.625)
CLASSD_L2_PA26: R181.1 U5.F7 | length 95.5
  L1 - Top Layer w0.125: U5.F7@73.475,71.375 73.803,71.047 v4(73.803,71.036) ; v1(78.4,66) 79.95,64.45 85.05,64.45 89.5,60 105.6,60 107.7,62.1 110.6,62.1 119.7,71.2 v2(131.1,71.2) ; v2(134.7,96.1) 134.9,96.3 R181.1@134.9,97.1
  L4 - Bottom Layer w0.1: 74.125,68.95 74.125,70.714
  L4 - Bottom Layer w0.125: v4(73.803,71.036) 74.125,70.714 ; 74.125,68.95 76.7,66.375 78.025,66.375 v1(78.4,66) ; v2(131.1,71.2) 131.1,92.5 v2(134.7,96.1)
CLASSD_L3_PA27: R182.1 U5.H2 | length 93.7
  L1 - Top Layer w0.125: U5.H2@76.725,72.675 77.043,72.357 82.7,72.357 84.857,70.2 85.5,70.2 91.2,64.5 111.107,64.5 119.507,72.9 v2(132.2,72.9) ; v2(136.3,95.7) 139.8,99.2 R182.1@139.8,101.15
  L4 - Bottom Layer w0.125: v2(132.2,72.9) 132.2,91.6 v2(136.3,95.7)
CTS/SCL: J10.7 R173.1 U24.11 | length 28.3
  L1 - Top Layer w0.125: U24.11@132,26.31 v2(132,27.8) R173.1@132,28.65
  L4 - Bottom Layer w0.125: v2(132,27.8) 132,28 132.8,28.8 133.7,28.8 139.45,23.05 J10.7@139.45,7.5
DBGU_RX_PA09: R252.1 R268.1 U17.5 | length 142.6
  L1 - Top Layer w0.125: v1(14,109.6) 15.4,109.6 17.725,107.275 v1(17.725,105.475) 16.275,105.475 15.6,104.8 14.675,104.8 12.205,107.27 12.205,115.305 14.495,117.595 44.505,117.595 49.7,112.4 v1(61.1,112.4) ; v1(102.6,112.5) 102.6,112.4 105.9,109.1 105.9,103.5 106.2,103.2 106.2,95.8 108.95,93.05 U17.5@108.95,89.125
  L4 - Bottom Layer w0.125: R268.1@13.15,109.6 v1(14,109.6) ; R252.1@16.875,105.475 v1(17.725,105.475) ; v1(61.1,112.4) 102.5,112.4 v1(102.6,112.5)
DBGU_TX_PA10: R254.1 R266.1 U17.6 | length 130.5
  L1 - Top Layer w0.125: v1(15.15,105.475) 15.15,106.575 14.725,107 v1(14,107) 14,107.8 12.7,109.1 12.7,115.1 14.7,117.1 40.8,117.1 42,117.1 47.3,111.8 v1(60,111.8) ; v1(102,111.8) 105.3,108.5 105.3,103.494 105.725,103.069 105.725,95.496 108.45,92.771 U17.6@108.45,89.125
  L4 - Bottom Layer w0.125: R266.1@13.15,107 v1(14,107) ; R254.1@14.275,105.475 v1(15.15,105.475) ; v1(60,111.8) v1(102,111.8)
DC_5V: C2.1 C3.1 Q1.1 Q2.2 Q2.5 R2.2 U1.4 U1.5 | length 9.1
  L1 - Top Layer w0.3: C3.1@18.25,35.5 19.05,34.7 v1(21.4,34.7) 21.8,34.3 Q2.5@21.8,33.913 ; 20.5,37 20.75,36.75 Q1.1@20.788,36.75 ; Q2.2@21.8,32.087 21.8,31.9 v1(22.2,31.5)
  L4 - Bottom Layer w0.3: v1(21.4,34.7) 22.2,33.9 v1(22.2,31.5)
DDR_A2: U5.A13 U10.M8 | length 43
  L1 - Top Layer w0.125: U10.M8@53.175,53.6 53.175,53.35 52.65,52.825 52.65,51.1 52.75,51 53,51 53.094,51 ccw(c53.094,51.219) 53.313,51.219 53.313,51.562 cw(c53.531,51.562) 53.531,51.781 53.719,51.781 cw(c53.719,51.562) 53.938,51.562 53.938,51.219 ccw(c54.156,51.219) 54.156,51 54.425,51 64,51 64.113,51.112 64.245,51.245 64.245,51.422 63.935,51.732 63.935,51.909 64.2,52.174 64.377,52.174 64.775,51.775 64.846,51.705 65.023,51.705 65.288,51.97 65.288,52.147 65.217,52.217 64.819,52.616 64.819,52.793 65.084,53.058 65.261,53.058 65.659,52.659 65.73,52.589 65.907,52.589 66.172,52.854 66.172,53.031 66.101,53.101 65.702,53.5 65.702,53.677 65.968,53.942 66.144,53.942 66.543,53.543 66.614,53.472 66.791,53.472 67.056,53.738 67.056,53.914 66.985,53.985 66.586,54.384 66.586,54.561 66.851,54.826 67.028,54.826 67.427,54.427 67.498,54.356 67.675,54.356 67.94,54.622 67.94,54.798 67.869,54.869 67.513,55.225 67.513,55.402 67.778,55.667 67.955,55.667 68.311,55.311 68.71,54.912 68.887,54.912 69.152,55.177 69.152,55.354 68.841,55.664 68.841,55.841 69.087,56.087 69.575,56.575 69.575,67.265 ; 69.575,67.285 U5.A13@69.575,68.125
DDR_A3: U5.D15 U10.M3 | length 40.1
  L1 - Top Layer w0.125: U10.M3@53.175,57.6 52.825,57.6 52.75,57.675 52.75,57.875 52.625,58 52.225,58 52,58.225 52,59.975 cw(c52.25,59.975) 52.25,60.225 53.45,60.225 53.75,60.525 53.75,62.615 cw(c54.621,62.615) 54.621,63.486 62.492,63.486 cw(c62.492,62.878) 63.1,62.878 63.1,58.296 ccw(c63.871,58.296) 63.871,57.525 66.525,57.525 ccw(c66.525,58.296) 67.296,58.296 ; v4(66.875,67.5) 66.875,66.225 67.3,65.8 67.3,58.296 ; U5.D15@68.275,70.075 v4(68.6,69.75)
  L4 - Bottom Layer w0.125: v4(66.875,67.5) 66.875,68.025 v4(68.6,69.75)
DDR_A4: U5.B12 U10.M7 | length 43
  L1 - Top Layer w0.125: U10.M7@53.175,54.4 52.775,54 52.775,53.475 52.3,53 52.3,50.989 52.625,50.664 65.164,50.664 65.633,51.133 65.633,51.309 65.441,51.501 65.441,51.678 65.706,51.943 65.882,51.943 66.163,51.663 66.443,51.382 66.62,51.382 66.885,51.648 66.885,51.824 66.605,52.105 66.324,52.385 66.324,52.562 66.59,52.827 66.766,52.827 67.047,52.547 67.327,52.266 67.504,52.266 67.769,52.531 67.769,52.708 67.489,52.989 67.208,53.269 67.208,53.446 67.473,53.711 67.65,53.711 67.931,53.431 68.211,53.15 68.388,53.15 68.653,53.415 68.653,53.592 68.373,53.873 68.3,53.945 68.3,54.267 68.533,54.5 69.575,54.5 69.9,54.825 69.9,68.45 U5.B12@70.225,68.775
DDR_A5: U5.E11 U10.N2 | length 42.7
  L1 - Top Layer w0.125: U10.N2@52.375,58.4 52.625,58.4 53,58.025 53.338,58.025 53.575,58.262 53.575,59.45 53.725,59.6 54.675,59.6 54.85,59.775 54.85,60.125 54.675,60.3 54.5,60.3 54.4,60.4 54.4,62.575 cw(c54.65,62.575) 54.65,62.825 54.775,62.825 cw(c54.775,62.575) 55.025,62.575 ; 55.025,62.55 ccw(c55.275,62.55) 55.275,62.3 55.4,62.3 ccw(c55.4,62.55) 55.65,62.55 ; 55.65,62.575 cw(c55.9,62.575) 55.9,62.825 56.025,62.825 cw(c56.025,62.575) 56.275,62.575 ; 56.275,62.55 ccw(c56.525,62.55) 56.525,62.3 56.65,62.3 ccw(c56.65,62.55) 56.9,62.55 ; 56.9,62.575 cw(c57.15,62.575) 57.15,62.825 57.275,62.825 cw(c57.275,62.575) 57.525,62.575 ; 57.525,62.55 ccw(c57.775,62.55) 57.775,62.3 57.9,62.3 ccw(c57.9,62.55) 58.15,62.55 ; 58.15,62.575 cw(c58.4,62.575) 58.4,62.825 58.525,62.825 cw(c58.525,62.575) 58.775,62.575 ; 58.775,62.55 ccw(c59.025,62.55) 59.025,62.3 62.19,62.3 cw(c62.19,62.05) 62.44,62.05 62.44,57.335 62.9,56.875 66.799,56.875 ; 66.799,56.872 ccw(c66.799,58.024) 67.95,58.024 67.95,68.277 70.398,70.725 U5.E11@70.875,70.725
DDR_A6: U5.A12 U10.N8 | length 43
  L1 - Top Layer w0.125: U10.N8@52.375,53.6 51.95,53.175 51.95,50.5 52.111,50.339 66.814,50.339 66.887,50.412 67.02,50.545 67.02,50.722 66.808,50.934 66.808,51.111 67.073,51.376 67.25,51.376 67.55,51.075 67.851,50.775 68.028,50.775 68.293,51.04 68.293,51.217 67.992,51.517 67.692,51.818 67.692,51.995 67.957,52.26 68.134,52.26 68.434,51.959 68.735,51.659 68.912,51.659 69.177,51.924 69.177,52.101 68.876,52.401 68.576,52.702 68.576,52.879 68.841,53.144 69.018,53.144 69.318,52.843 69.619,52.543 69.795,52.543 70.061,52.808 70.061,52.985 69.849,53.197 69.849,53.374 70.038,53.562 70.225,53.75 U5.A12@70.225,68.125
DDR_A7: U5.B16 U10.N3 | length 42.9
  L1 - Top Layer w0.125: U10.N3@52.375,57.6 52.125,57.6 51.725,58 51.425,58 51.175,58.25 51.175,59.275 51.25,59.35 51.25,61.9 cw(c51.5,61.9) 51.5,62.15 52.85,62.15 ccw(c52.85,62.4) 53.1,62.4 53.1,63.886 cw(c53.35,63.886) 53.35,64.136 63.5,64.136 cw(c63.5,63.886) 63.75,63.886 63.75,58.425 ccw(c64,58.425) 64,58.175 66.4,58.175 ccw(c66.4,58.425) 66.65,58.425 66.65,58.525 66.65,58.619 ccw(c66.431,58.619) 66.431,58.837 65.126,58.837 cw(c65.126,59.056) 64.907,59.056 64.907,59.244 cw(c65.126,59.244) 65.126,59.462 66.431,59.462 ccw(c66.431,59.681) 66.65,59.681 66.65,59.825 66.65,65.575 66.175,66.05 66.175,67.825 66.75,68.4 66.85,68.4 67.225,68.775 U5.B16@67.625,68.775
DDR_A8: U5.F16 U10.N7 | length 43.1
  L1 - Top Layer w0.125: U10.N7@52.375,54.4 51.925,54.85 50.175,54.85 49.588,54.85 49.463,54.725 49.463,52.934 49.338,52.809 48.963,52.809 48.838,52.934 48.838,54.85 48.838,55.885 48.713,56.01 48.338,56.01 48.213,55.885 48.213,54.975 48.088,54.85 47.9,54.85 47.65,54.85 47.465,55.035 47.465,63.076 56.113,71.725 65.265,71.725 65.565,71.425 65.615,71.375 U5.F16@67.625,71.375
DDR_A9: U5.D14 U10.P2 | length 43
  L1 - Top Layer w0.125: U10.P2@51.575,58.4 51.575,60.175 ; 51.575,60.125 51.575,60.325 cw(c51.825,60.325) 51.825,60.575 53.175,60.575 ccw(c53.175,60.825) 53.425,60.825 53.425,60.95 ccw(c53.175,60.95) 53.175,61.2 51.825,61.2 cw(c51.825,61.45) 51.575,61.45 51.575,61.575 cw(c51.825,61.575) 51.825,61.825 53.175,61.825 ccw(c53.175,62.075) 53.425,62.075 53.425,63.475 53.761,63.811 63.175,63.811 cw(c63.175,63.561) 63.425,63.561 63.425,58.311 ; U5.D14@68.925,70.075 68.938,70.062 68.938,69.588 68.925,69.575 67.8,68.45 67.3,68.45 66.95,68.1 66.85,68.1 66.475,67.725 66.475,66.15 66.975,65.65 66.975,58.399 cw(c66.426,58.399) 66.426,57.85 63.889,57.85 cw(c63.889,58.314) 63.425,58.303 ; 63.425,58.303 cw(c63.889,58.314) 63.425,58.311 ; 63.425,58.303 cw(c63.889,58.314) 63.425,58.311 ; 63.425,58.303 cw(c63.889,58.314) 63.425,58.311 ; 63.425,58.303 cw(c63.889,58.314) 63.425,58.311 ; 63.425,58.303 cw(c63.889,58.314) 63.425,58.311 ; 63.425,58.303 63.425,58.311 ; 63.425,58.311 cw(c63.889,58.314) 63.425,58.314 ; 63.425,58.311 cw(c63.889,58.314) 63.425,58.314 ; 63.425,58.311 cw(c63.889,58.314) 63.425,58.314 ; 63.425,58.311 cw(c63.889,58.314) 63.425,58.314 ; 63.425,58.311 cw(c63.889,58.314) 63.425,58.314 ; 63.425,58.311 cw(c63.889,58.314) 63.425,58.314 ; 63.425,58.311 cw(c63.889,58.314) 63.425,58.314 ; 63.425,58.311 cw(c63.889,58.314) 63.425,58.314
DDR_A10: U5.C11 U10.P8 | length 43
  L1 - Top Layer w0.125: U10.P8@51.575,53.6 51.575,53.365 50.975,52.765 50.975,51.875 50.975,51.781 ccw(c51.194,51.781) 51.194,51.562 51.406,51.562 cw(c51.406,51.344) 51.625,51.344 51.625,51.156 cw(c51.406,51.156) 51.406,50.937 51.194,50.937 ccw(c51.194,50.719) 50.975,50.719 50.975,50.5 50.975,50.3 51.261,50.014 67.914,50.014 70.55,52.65 70.55,54.75 70.55,55.062 70.55,55.531 cw(c70.706,55.531) 70.706,55.687 ccw(c70.706,55.906) 70.925,55.906 70.925,56.094 ccw(c70.706,56.094) 70.706,56.312 cw(c70.706,56.469) 70.55,56.469 70.55,56.781 cw(c70.706,56.781) 70.706,56.937 ccw(c70.706,57.156) 70.925,57.156 70.925,57.344 ccw(c70.706,57.344) 70.706,57.562 cw(c70.706,57.719) 70.55,57.719 70.55,58.187 70.55,58.575 70.55,69.1 U5.C11@70.875,69.425
DDR_A11: U5.E13 U10.P3 | length 40
  L1 - Top Layer w0.1: v4(69.231,70.375) 69.231,70.381 U5.E13@69.575,70.725
  L1 - Top Layer w0.125: U10.P3@51.575,57.6 51.325,57.6 50.925,58 50.55,58 50.065,58.485 50.065,60.215 cw(c50.275,60.215) 50.275,60.425 ccw(c50.275,60.675) 50.525,60.675 50.525,60.925 ccw(c50.3,60.925) 50.3,61.15 cw(c50.3,61.376) 50.074,61.376 50.074,61.525 cw(c50.3,61.525) 50.3,61.751 ccw(c50.3,61.976) 50.525,61.976 50.525,62.198 cw(c51.152,62.198) 51.152,62.825 52.175,62.825 52.428,63.078 52.428,64.053 cw(c53.175,64.053) 53.175,64.8 63.9,64.8 cw(c63.9,64.3) 64.4,64.3 ; 64.4,64.3 64.4,63.16 ccw(c64.912,63.16) 64.912,62.649 65.75,62.65 ccw(c65.75,62.876) 65.976,62.876 65.976,63.05 ccw(c65.749,63.05) 65.749,63.276 65.25,63.276 65.249,63.275 cw(c65.249,63.5) 65.024,63.5 65.024,63.75 cw(c65.249,63.75) 65.249,63.975 65.748,63.975 65.749,63.976 ccw(c65.749,64.202) 65.975,64.202 ; 65.025,66.125 65.025,66.148 ; 65.249,65.299 ccw(c65.249,65.074) 65.024,65.074 65.024,64.824 ccw(c65.249,64.824) 65.249,64.599 65.25,64.6 65.749,64.6 cw(c65.749,64.374) 65.975,64.374 65.976,64.2 ; 65.249,65.299 65.3,65.299 ; 65.25,68.15 ccw(c65.25,67.925) 65.025,67.925 65.025,67.723 ccw(c65.25,67.725) 65.25,67.5 65.298,67.5 cw(c65.298,67.274) 65.524,67.274 65.524,67.1 ; 65.25,68.15 65.3,68.15 ccw(c65.3,68.375) 65.525,68.375 v3(66.1,68.95) ; 65.3,65.299 ccw(c65.3,65.524) 65.525,65.524 65.524,65.525 65.524,65.699 ccw(c65.298,65.699) 65.298,65.925 65.25,65.925 cw(c65.25,66.15) 65.025,66.148 ; 65.525,67.099 cw(c65.3,67.099) 65.3,66.874 65.25,66.874 ccw(c65.25,66.649) 65.025,66.649 65.025,66.148 ; 65.025,66.148 cw(c65.25,66.15) 65.025,66.15 ; 65.025,66.148 cw(c65.25,66.15) 65.025,66.15 ; 65.025,66.148 cw(c65.25,66.15) 65.025,66.15 ; 65.025,66.148 cw(c65.25,66.15) 65.025,66.15 ; 65.025,66.148 cw(c65.25,66.15) 65.025,66.15 ; 65.025,66.148 cw(c65.25,66.15) 65.025,66.15 ; 65.025,66.148 cw(c65.25,66.15) 65.025,66.15 ; 65.025,66.148 cw(c65.25,66.15) 65.025,66.15
  L4 - Bottom Layer w0.1: 68.397,70.075 68.931,70.075 v4(69.231,70.375)
  L4 - Bottom Layer w0.125: v3(66.1,68.95) 66.425,68.95 66.55,68.825 67.147,68.825 68.397,70.075
DDR_A13: U5.B11 U10.P7 | length 43
  L1 - Top Layer w0.125: U10.P7@51.575,54.4 51.2,54.025 51.2,53.45 50.65,52.9 50.65,49.925 50.886,49.689 68.289,49.689 71.2,52.6 71.2,68.45 U5.B11@70.875,68.775
DDR_A14: U5.C15 U10.R2 | length 42.9
  L1 - Top Layer w0.125: 50.625,60.175 ccw(c50.625,60.425) 50.875,60.425 50.875,62.114 cw(c51.25,62.114) 51.25,62.489 52.525,62.489 ccw(c52.525,62.739) 52.775,62.739 52.775,64.063 cw(c53.187,64.063) 53.187,64.475 63.875,64.475 ; 50.64,60.175 ccw(c50.64,59.925) 50.39,59.925 50.39,58.785 U10.R2@50.775,58.4 ; 63.88,64.475 cw(c63.875,64.275) 64.075,64.275 64.075,60.05 ccw(c64.325,60.05) 64.318,59.8 66.075,59.8 ccw(c66.075,60.05) 66.325,60.05 66.325,60.178 ; 66.325,60.2 66.325,60.178 ; U5.C15@68.275,69.425 67.95,69.1 67.125,69.1 66.713,68.688 66.463,68.688 65.9,68.125 65.9,65.85 66.325,65.425 66.325,62.543 cw(c66.075,62.55) 66.075,62.3 64.975,62.3 ccw(c64.975,62.05) 64.725,62.05 64.725,61.925 ccw(c64.975,61.925) 64.975,61.675 66.075,61.675 cw(c66.075,61.425) 66.325,61.425 66.325,61.3 cw(c66.075,61.3) 66.075,61.05 64.95,61.05 ccw(c64.95,60.8) 64.7,60.8 64.7,60.675 ccw(c64.95,60.675) 64.95,60.425 66.075,60.425 cw(c66.075,60.175) 66.325,60.178 ; 66.325,60.175 ccw(c66.075,60.175) 66.325,60.178 ; 66.325,60.175 ccw(c66.075,60.175) 66.325,60.178 ; 66.325,60.175 ccw(c66.075,60.175) 66.325,60.178 ; 66.325,60.175 ccw(c66.075,60.175) 66.325,60.178 ; 66.325,60.175 ccw(c66.075,60.175) 66.325,60.178 ; 66.325,60.175 ccw(c66.075,60.175) 66.325,60.178 ; 66.325,60.175 ccw(c66.075,60.175) 66.325,60.178 ; 66.325,60.175 ccw(c66.075,60.175) 66.325,60.178
DDR_A15: U5.G15 U10.R8 | length 43
  L1 - Top Layer w0.125: 50.25,53.075 49.525,52.35 48.725,52.35 48.631,52.35 cw(c48.631,52.569) 48.413,52.569 48.413,53.84 ccw(c48.194,53.84) 48.194,54.059 48.006,54.059 ccw(c48.006,53.84) 47.788,53.84 47.788,52.569 cw(c47.569,52.569) 47.569,52.35 47.55,52.35 47.365,52.35 47.14,52.575 47.14,63.211 55.979,72.05 65.4,72.05 65.75,71.7 67.95,71.7 U5.G15@68.275,72.025 ; 50.25,53.075 U10.R8@50.775,53.6
DDR_A16: U5.E14 U10.L2 | length 40
  L1 - Top Layer w0.125: U10.L2@53.975,58.4 53.975,58.1 53.875,58 53.725,58 53.575,57.85 53.575,57.375 53.354,57.154 50.708,57.154 49.74,58.122 49.74,62.134 50.706,63.1 51.9,63.1 52.125,63.325 52.125,64.519 52.706,65.1 59.075,65.1 59.262,65.1 59.387,65.225 59.387,65.605 59.512,65.73 59.887,65.73 60.012,65.605 60.012,65.225 60.137,65.1 60.512,65.1 60.637,65.225 60.637,65.729 60.762,65.854 61.137,65.854 61.262,65.729 61.262,65.225 61.387,65.1 61.762,65.1 61.887,65.225 61.887,65.729 62.012,65.854 62.387,65.854 62.512,65.729 62.512,65.225 62.637,65.1 63.012,65.1 63.137,65.225 63.137,65.729 63.262,65.854 63.637,65.854 63.762,65.729 63.762,65.225 63.887,65.1 64.25,65.1 64.45,65.1 64.7,65.35 64.7,69.1 65.075,69.475 66.325,69.475 66.475,69.325 v4(66.8,69.325) 66.837,69.325 v4@66.85,69.338 ; v4(68.6,70.4) U5.E14@68.925,70.725
  L4 - Bottom Layer w0.125: v4(66.8,69.325) 67.24,69.325 68.315,70.4 v4(68.6,70.4)
DDR_A17: U5.F14 U10.L3 | length 40
  L1 - Top Layer w0.125: U10.L3@53.975,57.6 53.975,57.254 53.548,56.827 50.575,56.827 49.415,57.988 49.415,62.269 53.171,66.025 54.062,66.025 54.187,66.15 54.187,66.286 54.312,66.411 54.687,66.411 54.812,66.286 54.812,65.764 54.937,65.639 55.312,65.639 55.437,65.764 55.437,66.286 55.562,66.411 55.937,66.411 56.062,66.286 56.062,65.764 56.188,65.639 56.562,65.639 56.687,65.764 56.687,66.286 56.813,66.411 57.187,66.411 57.312,66.286 57.312,65.764 57.438,65.639 57.812,65.639 57.937,65.764 57.937,66.286 58.063,66.411 58.437,66.411 58.562,66.286 58.562,65.764 58.688,65.639 59.062,65.639 59.187,65.764 59.187,66.112 59.35,66.275 63.975,66.275 64.3,66.6 v3(64.3,69.675) ; v4(68.596,71.05) 68.6,71.05 U5.F14@68.925,71.375
  L4 - Bottom Layer w0.125: v3(64.3,69.675) 64.275,69.675 64.25,69.7 66.2,69.7 66.5,70 66.99,70 68.04,71.05 v4(68.596,71.05) v4@68.6,71.05
DDR_A18: U5.C16 U10.L1 | length 43
  L1 - Top Layer w0.125: U10.L1@53.975,59.2 54.375,58.8 54.375,57.194 53.681,56.5 50.443,56.5 49.09,57.853 49.09,62.403 53.587,66.9 54,66.9 55.669,66.9 ccw(c55.669,67.119) 55.888,67.119 55.888,67.423 cw(c56.106,67.423) 56.106,67.642 56.294,67.642 cw(c56.294,67.423) 56.513,67.423 56.513,67.119 ccw(c56.731,67.119) 56.731,66.9 56.919,66.9 ccw(c56.919,67.119) 57.138,67.119 57.138,67.423 cw(c57.356,67.423) 57.356,67.642 57.544,67.642 cw(c57.544,67.423) 57.763,67.423 57.763,67.119 ccw(c57.981,67.119) 57.981,66.9 58.169,66.9 ccw(c58.169,67.119) 58.388,67.119 58.388,67.423 cw(c58.606,67.423) 58.606,67.642 58.794,67.642 cw(c58.794,67.423) 59.013,67.423 59.013,67.119 ccw(c59.231,67.119) 59.231,66.9 59.419,66.9 ccw(c59.419,67.119) 59.638,67.119 59.638,67.423 cw(c59.856,67.423) 59.856,67.642 60.044,67.642 cw(c60.044,67.423) 60.263,67.423 60.263,67.119 ccw(c60.481,67.119) 60.481,66.9 60.669,66.9 ccw(c60.669,67.119) 60.888,67.119 60.888,67.423 cw(c61.106,67.423) 61.106,67.642 61.294,67.642 cw(c61.294,67.423) 61.513,67.423 61.513,67.119 ccw(c61.731,67.119) 61.731,66.9 61.919,66.9 ccw(c61.919,67.119) 62.138,67.119 62.138,67.423 cw(c62.356,67.423) 62.356,67.642 62.544,67.642 cw(c62.544,67.423) 62.763,67.423 62.763,67.119 ccw(c62.981,67.119) 62.981,66.9 ; U5.C16@67.625,69.425 67.3,69.75 64.875,69.75 64.512,70.113 64.119,70.113 63.675,69.669 63.675,67.275 63.3,66.9 63.075,66.9 ; 62.981,66.9 63.075,66.9 ; 62.981,66.9 63.075,66.9
DDR_CAS: U5.C12 U10.L7 | length 40
  L1 - Top Layer w0.1: v4(69.892,69.105) 70.211,69.425 U5.C12@70.225,69.425
  L1 - Top Layer w0.125: U10.L7@53.975,54.4 53.575,54 53.575,52.475 54.725,51.325 62.775,51.325 63.5,52.05 63.5,53.075 63.575,53.15 63.708,53.283 63.708,53.459 63.403,53.764 63.403,53.941 63.668,54.206 63.845,54.206 64.238,53.813 64.631,53.42 64.808,53.42 65.073,53.685 65.073,53.862 64.68,54.255 64.287,54.648 64.287,54.825 64.552,55.09 64.728,55.09 65.122,54.697 65.515,54.304 65.692,54.304 65.957,54.569 65.957,54.745 65.564,55.139 65.17,55.532 65.17,55.709 65.436,55.974 65.612,55.974 65.917,55.669 66.094,55.669 66.25,55.825 66.4,55.975 68.3,55.975 69.125,56.8 v3(69.125,66.425)
  L4 - Bottom Layer w0.1: 69.575,68.359 69.575,68.541
  L4 - Bottom Layer w0.125: v3(69.125,66.425) 69.575,66.875 69.575,68.359 ; 69.575,68.541 69.575,68.775 69.875,69.075 v4@69.875,69.125
DDR_CKE: U5.F13 U10.K2 | length 40
  L1 - Top Layer w0.125: U10.K2@54.775,58.4 54.775,58.121 55.175,57.721 55.175,56.8 54.225,55.85 50.174,55.85 48.44,57.584 48.44,62.673 54.967,69.2 62.2,69.2 63.75,70.75 64.85,70.75 65.2,70.4 v4(66.875,70.4) ; v4(69.25,71.05) U5.F13@69.575,71.375
  L4 - Bottom Layer w0.1: 67.875,71.375 68.925,71.375
  L4 - Bottom Layer w0.125: v4(66.875,70.4) 66.875,70.375 66.887,70.388 67.875,71.375 ; 68.925,71.375 v4(69.25,71.05)
DDR_CLK_N: U5.B14 U10.K8 | length 42.9
  L1 - Top Layer w0.1: U10.K8@54.775,53.6 54.525,53.6 54.025,53.1 54.025,52.451 54.826,51.65 62.124,51.65 63.075,52.601 63.075,55.2 62.725,55.55 57.975,55.55 57.875,55.65 57.875,56.176 57.974,56.275 67.974,56.275 68.575,56.876 68.575,68.425 U5.B14@68.925,68.775
DDR_CLK_P: U5.A15 U10.J8 | length 42.9
  L1 - Top Layer w0.1: U10.J8@55.575,53.6 55.575,53.275 55.5,53.2 54.55,53.2 54.325,52.975 54.325,52.575 54.95,51.95 62,51.95 62.775,52.725 62.775,55.076 62.601,55.25 57.851,55.25 57.575,55.526 57.575,57.075 57.65,57.15 57.9,57.15 57.975,57.075 57.975,56.675 58.075,56.575 67.85,56.575 68.275,57 68.275,67.55 U5.A15@68.275,68.125
DDR_CS: U5.E16 U10.L8 | length 43
  L1 - Top Layer w0.125: U10.L8@53.975,53.6 54.375,54 54.375,54.925 54.125,55.175 49.925,55.175 47.79,57.31 47.79,62.942 56.298,71.45 56.475,71.45 56.875,71.45 57.025,71.3 57.025,70.975 57.15,70.85 57.525,70.85 57.65,70.975 57.65,71.325 57.775,71.45 58.15,71.45 58.275,71.325 58.275,70.975 58.4,70.85 58.775,70.85 58.9,70.975 58.9,71.325 59.025,71.45 59.4,71.45 59.525,71.325 59.525,70.975 59.65,70.85 60.025,70.85 60.15,70.975 60.15,71.325 60.275,71.45 60.65,71.45 60.775,71.325 60.775,70.975 60.9,70.85 61.275,70.85 61.4,70.975 61.4,71.325 61.525,71.45 61.9,71.45 62.025,71.325 62.025,70.85 62.125,70.75 62.55,70.75 62.65,70.85 62.65,71.25 62.8,71.4 65.131,71.4 65.431,71.1 67.25,71.1 U5.E16@67.625,70.725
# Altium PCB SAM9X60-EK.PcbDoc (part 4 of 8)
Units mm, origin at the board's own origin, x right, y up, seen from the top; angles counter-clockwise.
Board outline 150 x 125 mm, 4 copper layers (L1 - Top Layer, L2 - GND, L3 - PWR, L4 - Bottom Layer), stack 1.52 mm thick; 566 components, 500 nets, 2132 pads, 1038 vias.

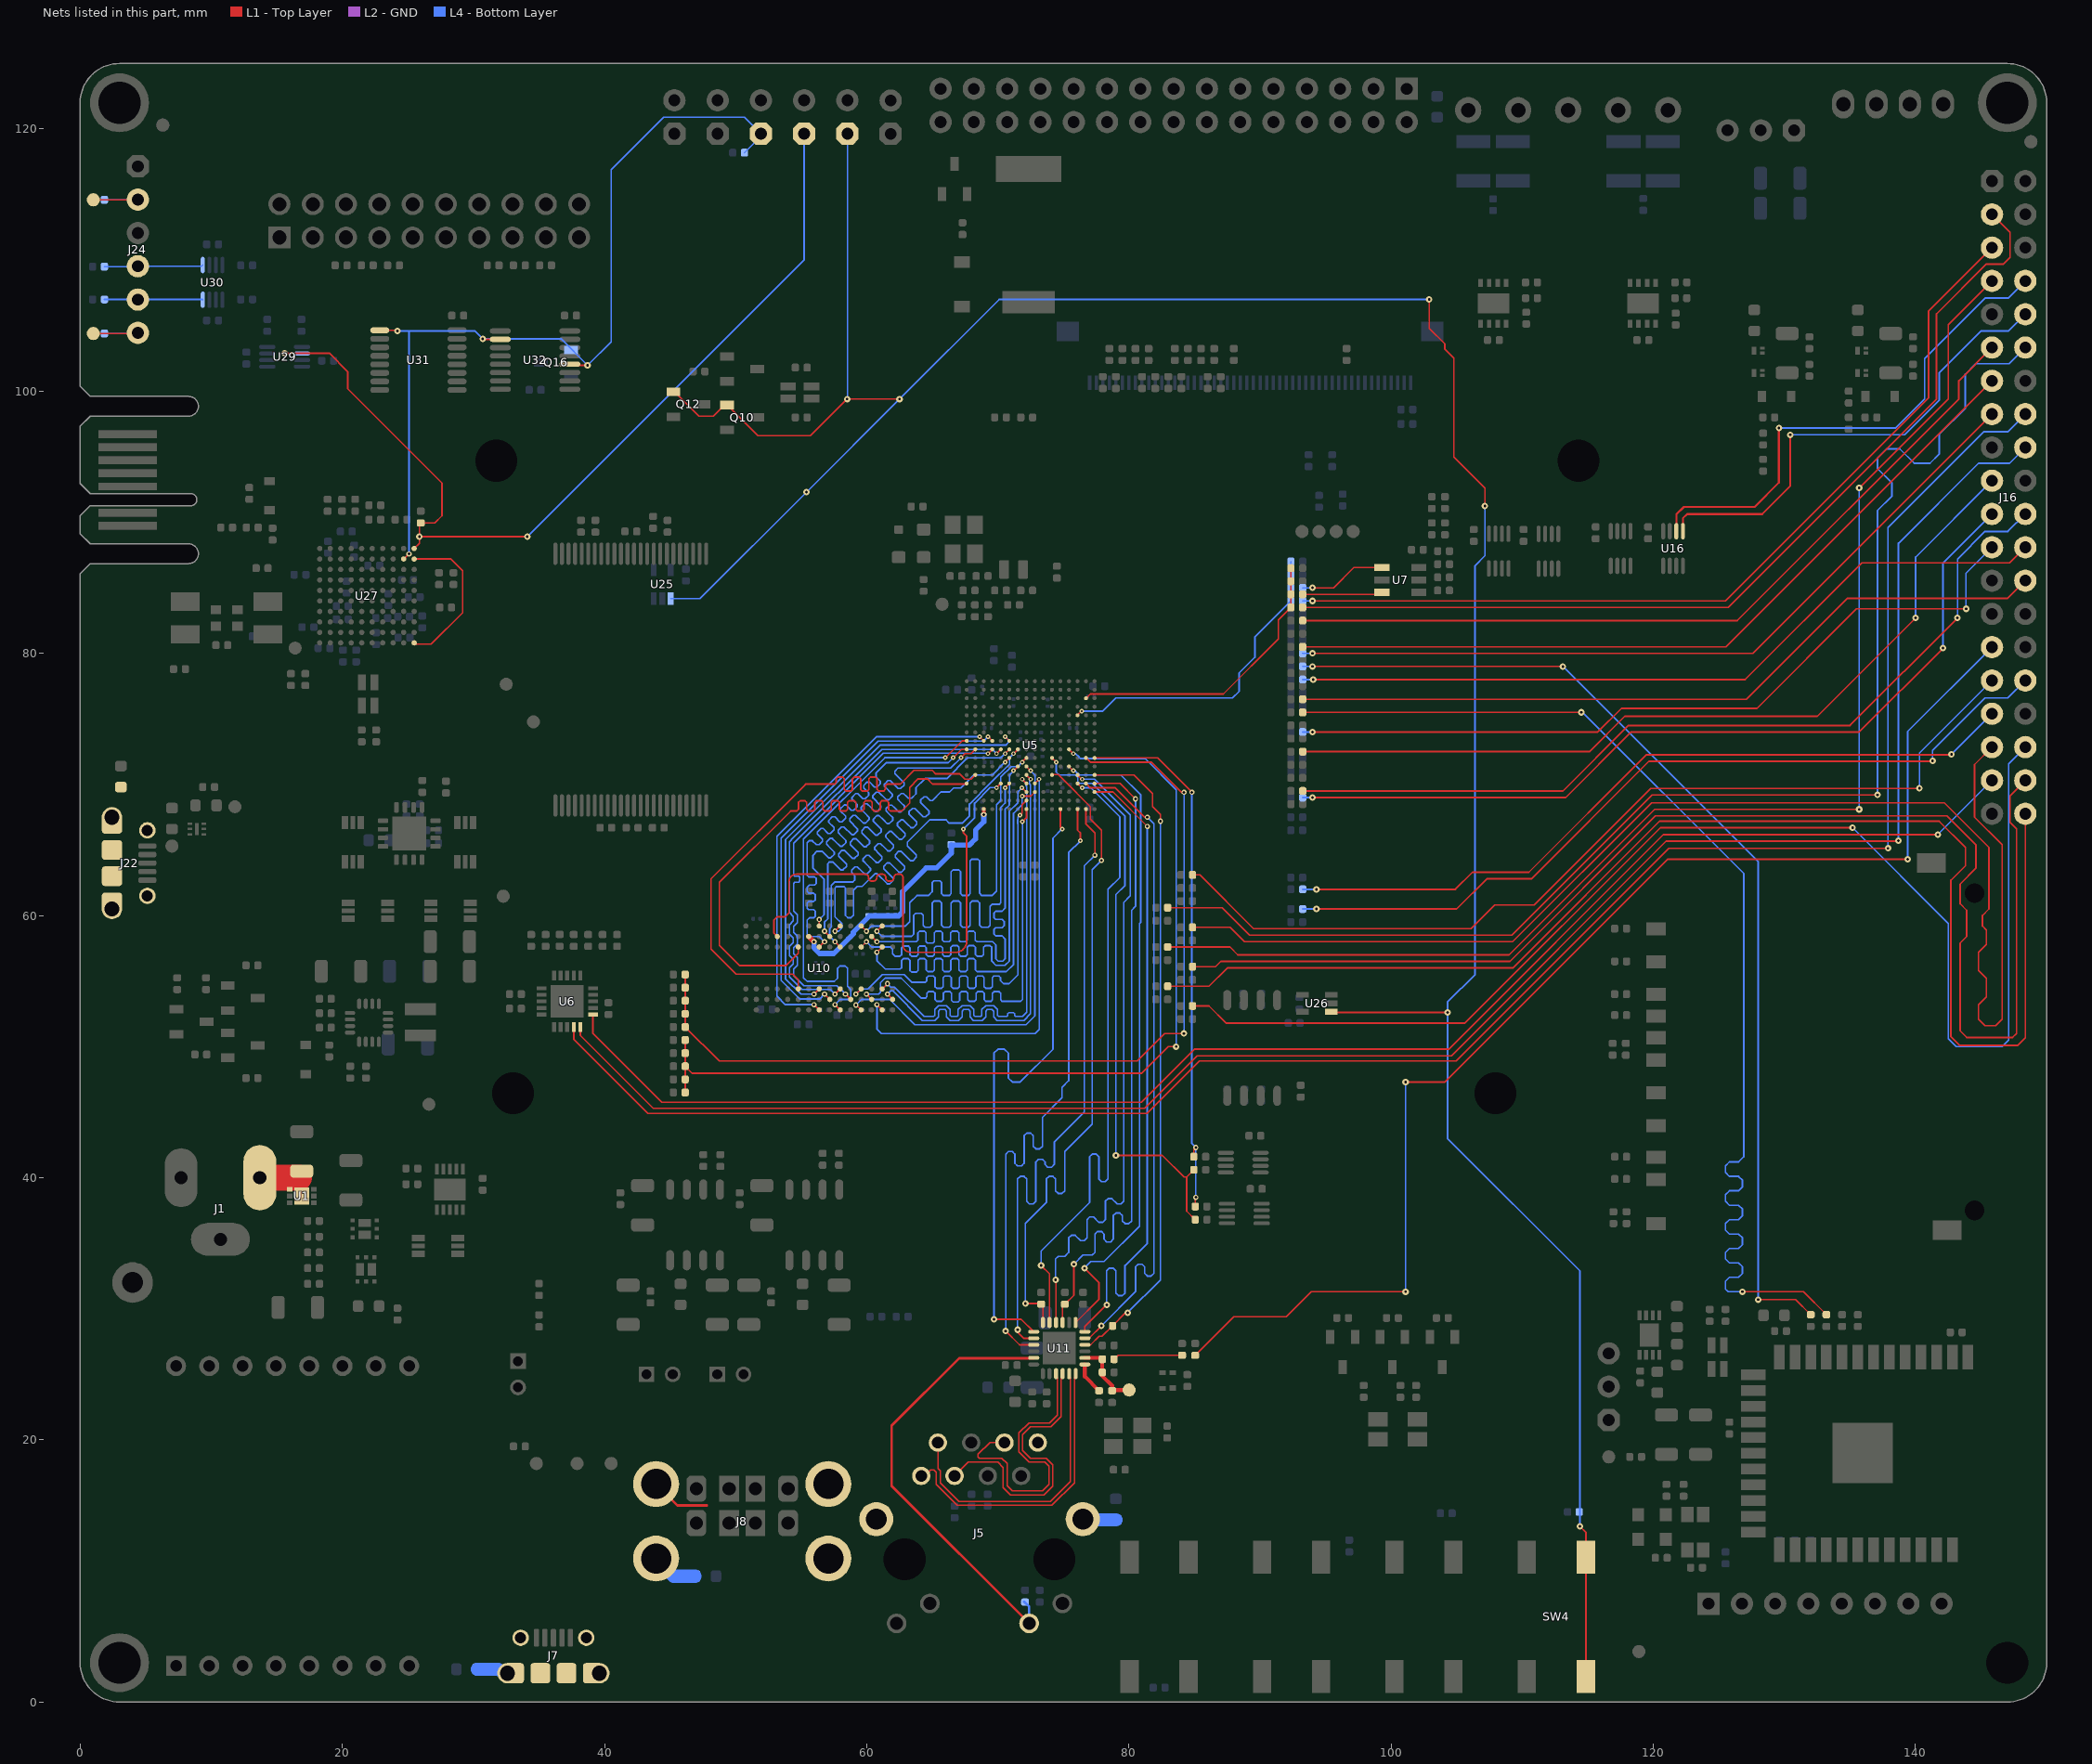
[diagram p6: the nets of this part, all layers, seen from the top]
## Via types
v1: diameter 0.5, hole 0.2, L1 - Top Layer to L4 - Bottom Layer, tented both sides, 483 vias
v2: diameter 0.5, hole 0.2, L1 - Top Layer to L4 - Bottom Layer, 268 vias
v3: diameter 0.4, hole 0.2, L1 - Top Layer to L4 - Bottom Layer, tented both sides, 145 vias
v4: diameter 0.35, hole 0.15, L1 - Top Layer to L4 - Bottom Layer, tented both sides, 121 vias
v5: diameter 0.55, hole 0.3, L1 - Top Layer to L4 - Bottom Layer, tented bottom, 16 vias
v6: diameter 0.559, hole 0.305, L1 - Top Layer to L4 - Bottom Layer, 5 vias

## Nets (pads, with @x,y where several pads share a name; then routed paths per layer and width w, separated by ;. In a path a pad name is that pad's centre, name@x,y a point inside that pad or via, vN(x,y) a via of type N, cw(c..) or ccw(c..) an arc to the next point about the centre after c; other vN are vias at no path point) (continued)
DDR_D0: U5.J13 U10.G8 | length 34.9
  L1 - Top Layer w0.125: v3(56.775,54) U10.G8@57.175,53.6 ; v4(69.25,73.65) U5.J13@69.575,73.325
  L4 - Bottom Layer w0.125: v3(56.775,54) 56.401,53.625 54.9,53.625 53.475,55.05 53.475,65.915 60.76,73.2 60.872,73.313 68.912,73.313 v4(69.25,73.65)
DDR_D1: U5.H11 U10.G2 | length 34.9
  L1 - Top Layer w0.125: v3(56.775,58.8) U10.G2@57.175,58.4 ; v4(70.55,72.35) U5.H11@70.875,72.675
  L4 - Bottom Layer w0.1: 68.425,72.025 70.225,72.025 v4(70.55,72.35)
  L4 - Bottom Layer w0.125: v3(56.775,58.8) 56.775,59.5 57.025,59.75 57.025,63.95 57.163,64.088 57.412,64.088 57.713,63.788 58.013,63.487 58.19,63.487 58.455,63.753 58.455,63.929 58.155,64.23 57.854,64.53 57.854,64.707 58.119,64.972 58.296,64.972 58.597,64.672 58.897,64.371 59.074,64.371 59.339,64.636 59.339,64.813 59.039,65.114 58.738,65.414 58.738,65.591 59.003,65.856 59.18,65.856 59.481,65.556 59.781,65.255 59.958,65.255 60.223,65.52 60.223,65.697 59.923,65.998 59.622,66.298 59.622,66.475 59.887,66.74 60.064,66.74 60.365,66.44 60.665,66.139 60.842,66.139 61.107,66.404 61.107,66.581 60.807,66.882 60.506,67.182 60.506,67.359 60.771,67.624 60.948,67.624 61.248,67.323 61.549,67.023 61.726,67.023 61.991,67.288 61.991,67.465 61.69,67.765 61.474,67.982 61.474,68.158 61.739,68.424 61.916,68.424 62.132,68.207 62.433,67.907 62.61,67.907 62.875,68.172 62.875,68.349 62.574,68.649 62.358,68.865 62.358,69.042 62.623,69.307 62.8,69.307 63.016,69.091 63.157,68.95 63.425,68.95 63.759,69.284 63.759,69.759 64.45,70.45 66.1,70.45 67.675,72.025 68.425,72.025
DDR_D2: U5.J11 U10.H7 | length 34.9
  L1 - Top Layer w0.125: v3(55.975,54) U10.H7@56.375,54.4 ; v4(70.55,73.65) U5.J11@70.875,73.325
  L4 - Bottom Layer w0.125: v3(55.975,54) 54.985,54 53.8,55.185 53.8,65.781 61.019,73 70.6,73 70.8,73.2 70.8,73.4 v4(70.55,73.65)
DDR_D3: U5.H16 U10.H3 | length 34.8
  L1 - Top Layer w0.125: U10.H3@56.375,57.6 v3@56.737,57.962 ; v4(66.6,72.05) 67.225,72.675 U5.H16@67.625,72.675
  L4 - Bottom Layer w0.125: v3(56.775,58) 56.375,58.4 55.6,58.4 55.45,58.55 55.45,59.65 55.625,59.825 55.95,59.825 56.075,59.95 56.075,60.325 55.95,60.45 55.55,60.45 55.45,60.55 55.45,60.95 55.575,61.075 55.95,61.075 56.075,61.2 56.075,61.575 55.95,61.7 55.6,61.7 55.45,61.85 55.45,62.15 55.625,62.325 56.025,62.325 56.15,62.45 56.15,62.825 56.025,62.95 55.575,62.95 55.45,63.075 55.45,65.55 55.6,65.7 55.854,65.7 56.154,65.4 56.37,65.4 56.615,65.645 56.615,65.822 56.225,66.212 56.225,66.375 56.5,66.65 56.671,66.65 57.057,66.264 57.234,66.264 57.499,66.529 57.499,66.706 57.1,67.105 57.1,67.25 57.375,67.525 57.564,67.525 57.941,67.148 58.118,67.148 58.383,67.413 58.383,67.59 57.977,67.996 57.977,68.127 58.288,68.438 58.419,68.438 58.825,68.032 59.002,68.032 59.267,68.297 59.267,68.474 58.875,68.866 58.875,69.025 59.15,69.3 59.325,69.3 59.709,68.916 59.886,68.916 60.151,69.181 60.151,69.358 59.775,69.734 59.775,69.925 60.025,70.175 60.217,70.175 60.593,69.799 60.77,69.799 61.035,70.065 61.035,70.241 60.717,70.56 60.717,70.892 61.475,71.65 66.2,71.65 v4(66.6,72.05)
DDR_D4: U5.H15 U10.H1 | length 34.9
  L1 - Top Layer w0.125: U10.H1@56.375,59.2 56.375,59.45 ; 56.375,59.451 v3(56.375,59.7) ; v4@67.15,72.05 v4(67.2,72.05) 67.5,72.35 67.95,72.35 U5.H15@68.275,72.675
  L4 - Bottom Layer w0.125: v3(56.375,59.7) 56.75,60.075 56.75,62.75 55.9,63.6 55.9,64.6 56.2,64.9 56.587,64.9 57.08,64.407 57.257,64.407 57.522,64.672 57.522,64.849 57.191,65.18 56.934,65.436 56.934,65.613 57.199,65.878 57.376,65.878 57.633,65.622 57.964,65.291 58.141,65.291 58.406,65.556 58.406,65.732 58.074,66.064 57.818,66.32 57.818,66.497 58.083,66.762 58.26,66.762 58.848,66.174 59.024,66.174 59.29,66.44 59.29,66.616 58.702,67.204 58.702,67.381 58.967,67.646 59.144,67.646 59.732,67.058 59.908,67.058 60.173,67.323 60.173,67.5 59.842,67.832 59.586,68.088 59.586,68.265 59.851,68.53 60.028,68.53 60.284,68.273 60.615,67.942 60.792,67.942 61.057,68.207 61.057,68.384 60.47,68.972 60.47,69.149 60.735,69.414 60.912,69.414 61.499,68.826 61.676,68.826 61.941,69.091 61.941,69.268 61.354,69.856 61.354,70.032 61.619,70.298 61.796,70.298 62.052,70.041 62.405,69.688 62.582,69.688 62.847,69.953 62.847,70.13 62.141,70.836 62.141,71.013 62.378,71.25 66.4,71.25 v4(67.2,72.05)
DDR_D5: U5.J14 U10.H9 | length 34.9
  L1 - Top Layer w0.125: v3(55.975,53.2) U10.H9@56.375,52.8 ; v4(68.6,73.65) U5.J14@68.925,73.325
  L4 - Bottom Layer w0.125: v3(55.975,53.2) 53.8,53.2 53.15,53.85 53.15,66.05 60.75,73.65 v4(68.6,73.65)
DDR_D6: U5.H10 U10.F1 | length 34.9
  L1 - Top Layer w0.1: v4(71.2,72.35) U5.H10@71.525,72.675
  L1 - Top Layer w0.125: v3(57.575,58.8) U10.F1@57.975,59.2
  L4 - Bottom Layer w0.1: 70.875,71.542 70.875,72.025 v4(71.2,72.35)
  L4 - Bottom Layer w0.125: v3(57.575,58.8) 57.85,58.8 58.1,59.05 58.1,59.375 57.575,59.9 57.575,62.1 57.688,62.212 58.262,62.212 58.375,62.1 58.375,60.01 58.55,59.835 58.8,59.835 59,60.035 59,61.95 59.275,62.225 59.65,62.225 60.615,63.19 60.792,63.19 61.568,62.414 61.745,62.414 62.01,62.679 62.01,62.856 61.292,63.574 61.292,63.751 61.557,64.016 61.734,64.016 62.452,63.298 62.629,63.298 62.894,63.563 62.894,63.74 62.176,64.458 62.176,64.635 62.441,64.9 62.618,64.9 63.336,64.182 63.512,64.182 63.778,64.447 63.778,64.624 63.1,65.302 63.1,65.6 64.8,67.3 66.05,67.3 66.3,67.05 67.275,67.05 67.834,67.609 67.834,68.502 69.452,70.12 ; 69.452,70.119 70.875,71.542
DDR_D7: U5.J16 U10.F9 | length 34.9
  L1 - Top Layer w0.125: v3(57.576,53.2) U10.F9@57.975,52.8 ; v4(66,72.05) 67.275,73.325 U5.J16@67.625,73.325
  L4 - Bottom Layer w0.125: v3(57.576,53.2) 57.975,53.6 58.6,53.6 58.775,53.775 58.775,54.35 58.525,54.6 58.525,55.975 58.35,56.15 57.95,56.15 57.775,55.975 57.775,55.225 57.525,54.975 55.45,54.975 55.175,55.25 55.175,65.834 61.391,72.05 v4(66,72.05)
DDR_D8: U5.A9 U10.C8 | length 34.6
  L1 - Top Layer w0.125: v3(59.975,54) U10.C8@60.375,53.6 ; v4(71.875,67.15) 72.175,67.45 U5.A9@72.175,68.125
  L4 - Bottom Layer w0.125: v3(59.975,54) 60.9,54 61.05,54.15 61.05,54.875 61.4,55.225 62.625,55.225 64.15,53.7 64.468,53.7 64.587,53.819 64.587,54.069 64.712,54.194 65.087,54.194 65.212,54.069 65.212,53.582 65.337,53.457 65.712,53.457 65.837,53.582 65.837,54.069 65.962,54.194 66.337,54.194 66.462,54.069 66.462,53.524 66.587,53.399 66.962,53.399 67.087,53.524 67.087,54.069 67.212,54.194 67.587,54.194 67.712,54.069 67.712,53.575 67.837,53.45 68.212,53.45 68.337,53.575 68.337,54.069 68.462,54.194 68.837,54.194 68.962,54.069 68.962,53.575 69.087,53.45 69.462,53.45 69.587,53.575 69.587,54.069 69.712,54.194 70.087,54.194 70.212,54.069 70.212,53.575 70.337,53.45 71.725,53.45 71.875,53.6 v4(71.875,67.15)
DDR_D9: U5.F10 U10.C2 | length 34.7
  L1 - Top Layer w0.125: U10.C2@60.375,58.4 v3@60.775,58 ; v4(71.2,71.05) U5.F10@71.525,71.375
  L4 - Bottom Layer w0.1: 70.875,68.85 70.875,70.725 v4(71.2,71.05)
  L4 - Bottom Layer w0.125: v3(60.775,58) 63.775,58 63.9,58.125 63.9,58.675 64.025,58.8 64.4,58.8 64.525,58.675 64.525,58 64.625,57.9 65.05,57.9 65.15,58 65.15,58.675 65.275,58.8 65.65,58.8 65.775,58.675 65.775,58.125 65.9,58 66.275,58 66.4,58.125 66.4,58.675 66.525,58.8 66.9,58.8 67.025,58.675 67.025,58.125 67.15,58 67.525,58 67.65,58.125 67.65,58.675 67.775,58.8 68.15,58.8 68.275,58.675 68.275,58.125 68.4,58 69.6,58 69.85,57.75 69.85,56.7 70.025,56.525 70.375,56.525 70.55,56.7 70.55,58.225 70.325,58.45 69.834,58.45 69.709,58.575 69.709,58.95 69.834,59.075 70.325,59.075 70.475,59.225 70.475,59.55 70.325,59.7 69.834,59.7 69.709,59.825 69.709,60.2 69.834,60.325 70.325,60.325 70.55,60.55 70.55,68.1 70.875,68.425 70.875,68.85
DDR_D10: U5.B9 U10.D7 | length 34.7
  L1 - Top Layer w0.125: v3(59.175,54) U10.D7@59.575,54.4 ; v4(71.675,67.65) 71.85,67.825 71.85,68.45 U5.B9@72.175,68.775
  L4 - Bottom Layer w0.125: v3(59.175,54) 59.575,54.4 60.087,54.4 61.188,55.5 62.85,55.5 63.45,54.9 64.45,54.9 64.575,55.025 64.575,55.265 64.7,55.39 65.075,55.39 65.2,55.265 65.2,54.579 65.325,54.454 65.7,54.454 65.825,54.579 65.825,55.265 65.95,55.39 66.325,55.39 66.45,55.265 66.45,54.579 66.575,54.454 66.95,54.454 67.075,54.579 67.075,55.265 67.2,55.39 67.575,55.39 67.7,55.265 67.7,54.579 67.825,54.454 68.2,54.454 68.325,54.579 68.325,55.265 68.45,55.39 68.825,55.39 68.95,55.265 68.95,54.579 69.075,54.454 69.45,54.454 69.575,54.579 69.575,55.265 69.7,55.39 70.075,55.39 70.2,55.265 70.2,55.025 70.425,54.8 70.85,54.8 71.525,55.475 71.525,66.987 71.512,67 71.512,67.3 71.525,67.312 71.525,67.5 v4(71.675,67.65)
DDR_D11: U5.C9 U10.D3 | length 34.6
  L1 - Top Layer w0.125: U10.D3@59.575,57.6 v3(59.975,58) ; v4(71.84,69.74) 71.86,69.74 U5.C9@72.175,69.425
  L4 - Bottom Layer w0.1: 71.525,68.6 71.525,69.425
  L4 - Bottom Layer w0.125: v3(59.975,58) 60.375,57.6 61.8,57.6 61.975,57.425 61.975,57.075 62.15,56.9 62.537,56.9 62.662,57.025 62.662,57.55 62.787,57.675 63.162,57.675 63.287,57.55 63.287,57.025 63.412,56.9 63.787,56.9 63.912,57.025 63.912,57.55 64.037,57.675 64.412,57.675 64.537,57.55 64.537,57.025 64.662,56.9 65.037,56.9 65.162,57.025 65.162,57.525 65.287,57.65 65.662,57.65 65.787,57.525 65.787,57.025 65.912,56.9 66.287,56.9 66.412,57.025 66.412,57.575 66.537,57.7 66.912,57.7 67.037,57.575 67.037,57.025 67.162,56.9 67.537,56.9 67.662,57.025 67.662,57.575 67.787,57.7 68.162,57.7 68.287,57.575 68.287,57.025 68.412,56.9 68.787,56.9 68.912,57.025 68.912,57.575 69.037,57.7 69.412,57.7 69.537,57.575 69.537,56.512 69.85,56.2 70.55,56.2 70.875,56.525 70.875,67.95 71.525,68.6 ; 71.525,69.425 v4(71.84,69.74) v4@71.85,69.75
DDR_D12: U5.G9 U10.D1 | length 34.6
  L1 - Top Layer w0.125: U10.D1@59.575,59.2 v3(59.975,58.8) ; v4(71.85,71.7) U5.G9@72.175,72.025
  L4 - Bottom Layer w0.1: 70.225,68.775 70.225,70.575 71.025,71.375 71.525,71.375 v4(71.85,71.7)
  L4 - Bottom Layer w0.125: v3(59.975,58.8) 60.375,59.2 62.95,59.2 63.275,59.525 63.275,60.975 63.825,61.525 64.697,61.525 64.987,61.815 64.987,62.5 65.132,62.645 65.567,62.645 65.712,62.5 65.712,61.67 65.857,61.525 66.292,61.525 66.437,61.67 66.437,63.334 66.582,63.479 67.017,63.479 67.162,63.334 67.162,61.67 67.307,61.525 67.742,61.525 67.887,61.67 67.887,64.155 68.032,64.3 68.467,64.3 68.612,64.155 68.612,61.688 68.775,61.525 69.55,61.525 69.9,61.875 69.9,68.45 70.225,68.775
DDR_D13: U5.F9 U10.D9 | length 34.8
  L1 - Top Layer w0.125: v3@59.175,53.2 U10.D9@59.575,52.8 ; U5.F9@72.175,71.375 v4(72.5,71.05)
  L4 - Bottom Layer w0.1: 72.825,70.225 72.825,70.725
  L4 - Bottom Layer w0.125: v3(59.175,53.175) 59.6,53.6 61.75,53.6 63.675,51.675 72.15,51.675 72.825,52.35 72.825,70.225 ; v4(72.5,71.05) 72.825,70.725
DDR_D14: U5.D11 U10.B1 | length 34.6
  L1 - Top Layer w0.125: v3(60.775,58.8) U10.B1@61.175,59.2 ; v4(70.55,69.75) U5.D11@70.875,70.075
  L4 - Bottom Layer w0.125: v3(60.775,58.8) 61.163,58.413 63.413,58.413 63.575,58.575 63.575,60.025 63.725,60.175 64.15,60.175 64.3,60.025 64.3,59.25 64.45,59.1 64.842,59.1 64.987,59.245 64.987,60.955 65.132,61.1 65.567,61.1 65.712,60.955 65.712,59.245 65.857,59.1 66.292,59.1 66.437,59.245 66.437,60.955 66.582,61.1 67.017,61.1 67.162,60.955 67.162,59.245 67.307,59.1 67.742,59.1 67.887,59.245 67.887,60.955 68.032,61.1 68.467,61.1 68.612,60.955 68.612,59.245 68.757,59.1 69.25,59.1 69.4,59.25 69.4,60.7 69.55,60.85 70.1,60.85 70.225,60.975 70.225,68.25 70.55,68.575 v4(70.55,69.75)
DDR_D15: U5.D8 U10.B9 | length 34.6
  L1 - Top Layer w0.125: v3@60.775,53.2 U10.B9@61.175,52.8 ; U5.D8@72.825,70.075 v4(73.15,70.4)
  L4 - Bottom Layer w0.125: v3(60.775,53.2) 60.775,51.35 61.125,51 72.85,51 73.15,51.3 v4(73.15,70.4)
DDR_DQM0: U5.G11 U10.F3 | length 34.9
  L1 - Top Layer w0.125: v3@57.575,58 U10.F3@57.975,57.6 ; v4(70.55,71.7) U5.G11@70.875,72.025
  L4 - Bottom Layer w0.1: 68.175,70.725 69.575,70.725
  L4 - Bottom Layer w0.125: v3(57.575,58) 57.175,58.4 57.175,59 57.3,59.125 57.3,62.3 57.55,62.55 58.925,62.55 59.083,62.708 59.083,63.034 58.843,63.274 58.843,63.451 59.108,63.716 59.285,63.716 59.613,63.388 59.835,63.166 60.012,63.166 60.277,63.431 60.277,63.607 60.055,63.83 59.727,64.158 59.727,64.335 59.992,64.6 60.169,64.6 60.497,64.272 60.719,64.049 60.896,64.049 61.161,64.315 61.161,64.491 60.939,64.714 60.611,65.042 60.611,65.219 60.876,65.484 61.052,65.484 61.381,65.156 61.603,64.933 61.78,64.933 62.045,65.198 62.045,65.375 61.823,65.598 61.451,65.969 61.451,66.146 61.717,66.411 61.893,66.411 62.265,66.04 62.487,65.817 62.664,65.817 62.929,66.082 62.929,66.259 62.707,66.482 62.335,66.853 62.335,67.03 62.6,67.295 62.777,67.295 63.148,66.923 63.371,66.701 63.548,66.701 63.813,66.966 63.813,67.143 63.59,67.365 63.219,67.737 63.219,67.913 63.484,68.179 63.661,68.179 64.315,67.525 64.491,67.525 64.757,67.79 64.757,67.967 64.103,68.621 64.103,68.797 64.368,69.062 64.545,69.062 64.828,68.78 65.005,68.78 65.65,69.425 66.325,69.425 66.625,69.725 67.175,69.725 68.175,70.725 ; 69.575,70.725 v4(70.55,71.7)
DDR_DQM1: U5.C8 U10.B3 | length 34.6
  L1 - Top Layer w0.125: v3(60.775,57.2) U10.B3@61.175,57.6 ; v4@71.875,69.1 72.5,69.1 U5.C8@72.825,69.425
  L4 - Bottom Layer w0.125: v3(60.775,57.2) 60.775,56.55 61.415,55.91 62.538,55.91 62.663,56.035 62.663,56.585 62.788,56.71 63.163,56.71 63.288,56.585 63.288,55.816 63.413,55.691 63.788,55.691 63.913,55.816 63.913,56.585 64.038,56.71 64.413,56.71 64.538,56.585 64.538,55.85 64.663,55.725 65.038,55.725 65.163,55.85 65.163,56.585 65.288,56.71 65.663,56.71 65.788,56.585 65.788,55.85 65.913,55.725 66.288,55.725 66.413,55.85 66.413,56.585 66.538,56.71 66.913,56.71 67.038,56.585 67.038,55.85 67.163,55.725 67.538,55.725 67.663,55.85 67.663,56.585 67.788,56.71 68.163,56.71 68.288,56.585 68.288,55.85 68.413,55.725 70.65,55.725 71.2,56.275 71.2,67.8 71.85,68.45 v4(71.85,69.1)
DDR_DQS0_N: U5.H13 U10.E8 | length 34.8
  L1 - Top Layer w0.1: v3(58.375,54) U10.E8@58.775,53.6 ; v4(69.25,72.35) U5.H13@69.575,72.675
  L4 - Bottom Layer w0.1: v3(58.375,54) 57.725,54.65 55.201,54.65 54.412,55.438 54.412,55.9 54.7,56.188 54.7,56.788 54.413,57.075 54.413,57.537 54.7,57.824 54.7,58.424 54.413,58.712 54.413,59.173 54.7,59.461 54.7,60.061 54.413,60.348 54.412,62.45 54.5,62.537 54.8,62.537 54.9,62.637 54.9,62.912 54.8,63.012 54.5,63.012 54.412,63.1 54.412,65.513 61.274,72.375 69.225,72.375 v4(69.25,72.35)
DDR_DQS0_P: U5.H12 U10.F7 | length 34.9
  L1 - Top Layer w0.1: v3(57.575,54) U10.F7@57.975,54.4 ; v4(69.9,72.35) U5.H12@70.225,72.675
  L4 - Bottom Layer w0.1: v3(57.575,54) 57.225,54.35 55.077,54.35 54.113,55.314 54.113,56.024 54.4,56.312 54.4,56.663 54.113,56.951 54.113,57.661 54.4,57.948 54.4,58.3 54.113,58.587 54.113,59.298 54.4,59.585 54.4,59.937 54.113,60.224 54.113,65.637 54.399,65.924 61.15,72.675 69.575,72.675 v4(69.9,72.35)
DDR_DQS1_N: U5.E9 U10.A8 | length 34.8
  L1 - Top Layer w0.1: v3(61.575,54) U10.A8@61.975,53.6 ; U5.E9@72.175,70.725 72.325,70.575 v4(72.5,70.4)
  L4 - Bottom Layer w0.1: v3(61.575,54) 61.825,54.25 62,54.25 64.25,52 64.6,52 65.207,52 65.475,52.268 65.475,52.708 65.592,52.825 65.958,52.825 66.075,52.708 66.075,52.268 66.343,52 67.007,52 67.275,52.268 67.275,52.708 67.392,52.825 67.758,52.825 67.875,52.708 67.875,52.268 68.143,52 68.807,52 69.075,52.268 69.075,52.708 69.192,52.825 69.558,52.825 69.675,52.708 69.675,52.268 69.943,52 72,52 72.5,52.5 72.5,69.974 72.425,70.049 72.425,70.325 v4(72.5,70.4)
DDR_DQS1_P: U5.D9 U10.B7 | length 34.7
  L1 - Top Layer w0.1: U10.B7@61.175,54.4 v3@61.575,54.8 ; v4(71.85,70.4) U5.D9@72.175,70.075
  L4 - Bottom Layer w0.1: v3(61.575,54.8) 61.825,54.55 62.124,54.55 64.374,52.3 64.724,52.3 65.083,52.3 65.175,52.392 65.175,52.832 65.468,53.125 66.082,53.125 66.375,52.832 66.375,52.392 66.467,52.3 66.883,52.3 66.975,52.392 66.975,52.832 67.268,53.125 67.882,53.125 68.175,52.832 68.175,52.392 68.267,52.3 68.683,52.3 68.775,52.392 68.775,52.832 69.068,53.125 69.682,53.125 69.975,52.832 69.975,52.392 70.067,52.3 70.675,52.3 70.75,52.375 70.75,52.5 70.85,52.6 71.175,52.6 71.275,52.5 71.275,52.375 71.35,52.3 71.876,52.3 72.2,52.624 72.2,69.85 72.125,69.925 72.125,70.125 v4(71.85,70.4)
DDR_RAS: U5.E15 U10.K7 | length 43.1
  L1 - Top Layer w0.125: U10.K7@54.775,54.4 54.775,55.1 54.35,55.525 54.311,55.525 54.31,55.524 50.036,55.524 48.115,57.445 48.115,62.807 55.333,70.025 57.35,70.025 57.537,70.025 57.662,70.15 57.662,70.433 57.787,70.558 58.162,70.558 58.287,70.433 58.287,70.025 58.287,69.617 58.412,69.492 58.787,69.492 58.912,69.617 58.912,70.025 58.912,70.433 59.037,70.558 59.412,70.558 59.537,70.433 59.537,70.025 59.537,69.617 59.662,69.492 60.037,69.492 60.162,69.617 60.162,70.025 60.162,70.433 60.287,70.558 60.662,70.558 60.787,70.433 60.787,70.025 60.787,69.617 60.912,69.492 61.287,69.492 61.412,69.617 61.412,69.9 61.537,70.025 61.85,70.025 62.55,70.025 63.6,71.075 64.996,71.075 65.271,70.8 67.09,70.8 67.49,70.4 67.95,70.4 U5.E15@68.275,70.725
DDR_SDA10: U5.D12 U10.M2 | length 39.8
  L1 - Top Layer w0.1: v4(69.9,69.75) U5.D12@70.225,70.075
  L1 - Top Layer w0.125: U10.M2@53.175,58.4 52.925,58.65 52.925,59.675 53.15,59.9 53.775,59.9 54.075,60.2 54.075,62.596 cw(c54.629,62.596) 54.629,63.15 ; 54.629,63.15 59.885,63.15 ; 59.885,63.15 cw(c59.885,62.9) 60.135,62.9 ; 60.135,62.875 ccw(c60.385,62.875) 60.385,62.625 60.51,62.625 ccw(c60.51,62.875) 60.76,62.875 ; 60.76,62.9 cw(c61.01,62.9) 61.01,63.15 ; 61.01,63.15 61.2,63.15 ; 61.2,63.15 cw(c61.2,62.9) 61.45,62.9 ; 61.45,62.875 ccw(c61.7,62.875) 61.7,62.625 61.825,62.625 ccw(c61.825,62.875) 62.075,62.875 ; 62.075,62.9 cw(c62.325,62.9) 62.325,63.15 ; 62.325,63.15 62.515,63.15 ; 62.515,63.15 cw(c62.515,62.9) 62.765,62.9 62.765,57.75 ccw(c63.315,57.75) 63.315,57.2 66.788,57.2 ccw(c66.788,58.037) 67.625,58.037 67.625,66.05 67.375,66.3 v4(67.375,66.6)
  L4 - Bottom Layer w0.1: 68.225,68.575 69.4,69.75 v4(69.9,69.75)
  L4 - Bottom Layer w0.125: v4(67.375,66.6) 68.225,67.45 68.225,68.575
DDR_VREF: C63.1 C64.1 C66.2 R120.1 R121.2 U5.A14 U10.J2 | length 21.1
  L1 - Top Layer w0.3: v3(68.925,67.7) U5.A14@68.925,68.125
  L1 - Top Layer w0.4: U10.J2@55.575,58.4 v3(55.975,58)
  L4 - Bottom Layer w0.4: v3(55.975,58) 55.975,57.525 56.4,57.1 57.475,57.1 58.575,58.2 58.975,58.6 58.975,58.725 60.225,59.975 62.431,59.975 62.725,60.269 62.725,61.825 64.525,63.625 65.325,63.625 66.45,64.75 C64.1@66.45,65.375 ; C64.1@66.45,65.4 C64.1@66.45,65.375 ; v3(68.925,67.7) 68.925,67.15 68.3,66.525 68.3,65.844 67.831,65.375 C64.1@66.45,65.375
DDR_WE: U5.D16 U10.K3 | length 43
  L1 - Top Layer w0.125: U10.K3@54.775,57.6 54.775,57.135 53.815,56.175 50.308,56.175 48.765,57.718 48.765,62.538 54.202,67.975 54.475,67.975 54.662,67.975 54.787,68.1 54.787,68.629 54.912,68.754 55.287,68.754 55.412,68.629 55.412,68.1 55.537,67.975 55.912,67.975 56.037,68.1 56.037,68.637 56.162,68.762 56.537,68.762 56.662,68.637 56.662,68.1 56.787,67.975 57.162,67.975 57.287,68.1 57.287,68.637 57.412,68.762 57.787,68.762 57.912,68.637 57.912,68.1 58.037,67.975 58.412,67.975 58.537,68.1 58.537,68.637 58.662,68.762 59.037,68.762 59.162,68.637 59.162,68.1 59.287,67.975 59.662,67.975 59.787,68.1 59.787,68.637 59.912,68.762 60.287,68.762 60.412,68.637 60.412,68.1 60.537,67.975 60.912,67.975 61.037,68.1 61.037,68.637 61.162,68.762 61.537,68.762 61.662,68.637 61.662,68.1 61.787,67.975 62.475,67.975 62.675,67.975 63.275,68.575 63.275,69.775 63.925,70.425 64.631,70.425 65.031,70.025 67.575,70.025 U5.D16@67.625,70.075
DIS_BOOT: J13.1 Q10.1 Q12.1 R204.1 SW4.1 SW4.2 U25.1 U26.1 | length 229.2
  L1 - Top Layer w0.125: Q12.1@45.35,99.95 47.2,98.1 48.3,98.1 49.15,98.95 Q10.1@49.35,98.95 51.7,96.6 55.7,96.6 v1(58.5,99.4) v1(62.5,99.4) ; U26.1@95.425,52.65 95.475,52.6 v2(104.3,52.6) ; v2(102.9,107) 102.9,104.8 104.1,103.6 104.1,103.2 104.775,102.525 104.775,94.988 107.15,92.612 v2(107.15,91.25) ; v2(114.4,13.4) 114.85,12.95 SW4.1@114.85,11.05 SW4.2@114.85,1.95
  L4 - Bottom Layer w0.125: U25.1@45.05,84.175 47.275,84.175 v1(55.4,92.3) v1(62.5,99.4) 70.1,107 v2(102.9,107) ; v1@58.525,99.4 J13.1@58.525,119.65 ; v2(107.15,91.25) 107.15,87.45 106.4,86.7 106.4,55.5 104.3,53.4 v2(104.3,52.6) 104.3,43 114.4,32.9 v2(114.4,13.4)
DIS_CDC: J21.1 R241.2 U27.K10 U29.6 | length 72.4
  L1 - Top Layer w0.125: v1(15.6,102.9) 19,102.9 20.4,101.5 20.4,100.2 27.6,93 27.6,90.5 27.05,89.95 R241.2@25.975,89.95 ; U27.K10@25.475,88 25.875,88.4 v1(25.875,88.9) ; R241.2@25.875,89.8 v1(25.875,88.9) ; v1(34.1,88.9) v1(25.875,88.9)
  L4 - Bottom Layer w0.125: v1(15.6,102.9) 15.625,102.875 U29.6@16.925,102.875 ; v1@34,88.8 v1(34.1,88.9) 55.225,110.025 J21.1@55.225,119.65
DIS_JLINK: J20.1 Q16.1 R232.2 U27.J9 U31.1 U32.2 U32.12 | length 68.6
  L1 - Top Layer w0.125: U31.1@22.85,104.645 24.155,104.645 v1(24.2,104.6) ; U27.J9@24.675,87.2 25.063,87.588 v3(25.084,87.588) ; v1(30.7,104) 30.742,103.958 U32.2@32.05,103.958 ; U32.12@37.35,102.053 37.433,101.97 v2(38.7,101.97) v2@38.75,102.02
  L4 - Bottom Layer w0.125: v1(24.2,104.6) 25.084,104.6 ; v3(25.084,87.588) 25.084,104.6 ; R232.2@50.675,118.195 51.925,119.445 J20.1@51.925,119.65 50.675,120.9 44.5,120.9 40.5,116.9 40.5,103.77 v2(38.7,101.97) 36.67,104 v1(30.7,104) 30.1,104.6 25.084,104.6
EARTH_ETH: FB3.1 J5.8 J5.13 J5.14 | length 2.5
  L4 - Bottom Layer w1: J5.14@76.475,13.95 76.525,13.9 FB3.1@79,13.9
EARTH_JLINK: FB13.1 J22.0
EARTH_USB_A: FB5.1 J7.0 | length 1.6
  L4 - Bottom Layer w1: FB5.1@30.3,2.5 31.877,2.5 J7.0@31.925,2.452
EARTH_USB_B: FB7.1 J8.0 | length 8.1
  L1 - Top Layer w0.2: J8.0@43.93,16.63 45.56,15 47.8,15
  L4 - Bottom Layer w1: J8.0@43.93,10.95 45.28,9.6 FB7.1@46.9,9.6
EEPROM_TWCK: R76.2 U7.1 | length 6.7
  L1 - Top Layer w0.125: v2(94,85) 95.6,85 97.15,86.55 U7.1@99.3,86.55
  L4 - Bottom Layer w0.125: R76.2@93.25,85 v2(94,85)
EEPROM_TWD: R67.2 U7.3 | length 6.1
  L1 - Top Layer w0.125: R67.2@93.25,84.5 99.15,84.5 U7.3@99.3,84.65
ENSPI: U27.K1 U27.K9 | length 12
  L1 - Top Layer w0.125: U27.K1@25.475,80.8 25.575,80.7 26.775,80.7 29.175,83.1 29.175,86.3 28.275,87.2 U27.K9@25.475,87.2
ETH0_IRQ_PB08: R122.2 U5.E6 U11.18 | length 50.3
  L1 - Top Layer w0.125: v2(72.1,30.4) 73.15,30.4 73.25,30.3 R122.2@73.3,30.35 73.435,30.215 U11.18@73.435,28.95 ; U5.E6@74.125,70.725 74.15,70.75 74.6,70.75 75.025,70.325 77.054,68.296 77.054,67.346 77.9,66.5 v3(77.9,64.2)
  L4 - Bottom Layer w0.125: v2(72.1,30.4) 72.1,36.5 73.7,38.1 73.7,39.9 73.9,40.1 74.2,40.1 74.4,39.9 74.4,39 74.6,38.8 74.9,38.8 75.1,39 75.1,42 77.2,44.1 77.2,63.5 v3(77.9,64.2)
ETH0_MDC_PB06: U5.D2 U11.11 | length 50.2
  L1 - Top Layer w0.125: U11.11@76.635,27.75 76.965,27.75 77.9,28.685 v1(77.9,28.7) ; U5.D2@76.725,70.075 77.06,69.74 78.96,69.74 81.2,67.5 v3(81.4,67.5)
  L4 - Bottom Layer w0.125: v1(77.9,28.7) 80.5,31.3 80.5,33.2 80.7,33.4 81,33.4 81.2,33.2 81.2,32.7 81.4,32.5 81.7,32.5 81.9,32.7 81.9,67 v3(81.4,67.5)
ETH0_MDIO_PB05: R123.2 U5.E1 U11.10 | length 50.2
  L1 - Top Layer w0.125: U11.10@76.635,27.25 77.069,27.25 77.719,27.9 77.95,27.9 R123.2@78.75,28.7 79.75,29.7 v1(79.9,29.7) ; U5.E1@77.375,70.725 80.375,70.725 81.8,69.3 81.8,68.3 82.4,67.7 v3(82.4,67.2)
  L4 - Bottom Layer w0.125: v1(79.9,29.7) 82.4,32.2 v3(82.4,67.2)
ETH0_PCK1_PC31: R88.1 R133.2 | length 5.3
  L1 - Top Layer w0.125: R133.2@78.865,26.15 79.165,26.45 R88.1@84.05,26.45
ETH0_RX0_PB00: U5.F4 U11.13 | length 50.2
  L1 - Top Layer w0.125: U5.F4@75.425,71.375 v4(75.75,71.05) ; U11.13@75.935,28.95 77.7,30.715 77.7,32 v2(76.6,33.1)
  L4 - Bottom Layer w0.1: v4@75.9,71.05 76.225,70.725 76.516,70.725
  L4 - Bottom Layer w0.125: v4(75.75,71.05) v4@75.9,71.05 ; 76.516,70.725 79.375,70.725 80.9,69.2 80.9,59.5 80.8,59.4 80.8,36.3 78.1,33.6 77.1,33.6 v2(76.6,33.1)
ETH0_RX1_PB01: U5.C1 U11.12 | length 50.3
  L1 - Top Layer w0.125: U11.12@76.635,28.25 76.635,28.635 v1@78.2,30.2 ; U5.C1@77.375,69.425 78.775,69.425 v3@81.5,66.7
  L4 - Bottom Layer w0.125: v1@78.2,30.2 v1(78.3,30.3) 78.3,32.9 78.5,33.1 78.8,33.1 79,32.9 79,31.2 79.2,31 79.5,31 79.7,31.2 79.7,33.3 81.4,35 81.4,66.6 v3@81.5,66.7
  other v3: 81.4,66.8
ETH0_RXDV_PB03: R127.1 U5.D1 U11.15 | length 50.2
  L1 - Top Layer w0.125: U11.15@74.935,28.95 74.935,30.17 R127.1@75.115,30.35 75.8,31.035 v2(75.8,33.4) ; U5.D1@77.375,70.075 79.325,70.075 v3(80.5,68.9)
  L4 - Bottom Layer w0.125: v2(75.8,33.4) 76.5,34.1 77.2,34.1 77.4,34.3 77.4,35.7 77.6,35.9 77.9,35.9 78.1,35.7 78.1,35.3 78.3,35.1 78.6,35.1 78.8,35.3 78.8,37.1 79,37.3 79.3,37.3 79.5,37.1 79.5,36.7 79.7,36.5 80,36.5 80.2,36.7 80.2,60.4 80.5,60.7 v3(80.5,68.9)
ETH0_RXER_PB02: U5.D3 U11.17 | length 50.2
  L1 - Top Layer w0.125: v2(73.3,33.3) 73.935,32.665 U11.17@73.935,28.95 ; U5.D3@76.075,70.075 76.4,69.75 v4(76.425,69.75)
  L4 - Bottom Layer w0.125: v2(73.3,33.3) 73.3,34.4 77,38.1 77,41.6 77.2,41.8 77.5,41.8 77.7,41.6 77.7,39.9 77.9,39.7 78.2,39.7 78.4,39.9 78.4,62 79.3,62.9 79.3,67.525 77.075,69.75 v4(76.425,69.75)
ETH0_TX0_PB09: U5.A2 U11.20 | length 50.2
  L1 - Top Layer w0.125: v2(71.5,28.4) 71.5,28.215 71.965,27.75 U11.20@72.735,27.75 ; U5.A2@76.725,68.125 76.725,66.975 77.4,66.3 v3(77.4,64.6)
  L4 - Bottom Layer w0.125: v2(71.5,28.4) 71.5,39.9 71.7,40.1 72,40.1 72.2,39.9 72.2,38.2 72.4,38 72.7,38 72.9,38.2 72.9,41.2 73.1,41.4 73.4,41.4 73.6,41.2 73.6,41 73.8,40.8 74.1,40.8 74.3,41 74.3,42.7 76.6,45 76.6,63.8 v3(77.4,64.6)
ETH0_TX1_PB10: U5.A3 U11.21 | length 50.2
  L1 - Top Layer w0.125: v2(70.6,28.3) 71.65,27.25 U11.21@72.735,27.25 ; U5.A3@76.075,68.125 76.075,66.525 76.3,66.3 v4(76.3,65.7)
  L4 - Bottom Layer w0.125: v2(70.6,28.3) 70.6,41.6 70.6,41.8 70.8,42 71.1,42 71.3,41.8 71.3,41.1 71.5,40.9 71.8,40.9 72,41.1 72,43.2 72.2,43.4 72.5,43.4 72.7,43.2 72.7,42.4 72.9,42.2 73.2,42.2 73.4,42.4 73.4,44.6 74.9,46.1 74.9,46.9 75.4,47.4 75.4,64.8 v4(76.3,65.7)
ETH0_TXCK_PB04: U5.E3 U11.16 | length 50.1
  L1 - Top Layer w0.125: v2(74.4,32.2) 74.435,32.165 U11.16@74.435,28.95 ; U5.E3@76.075,70.725 v4@76.4,70.4
  L4 - Bottom Layer w0.125: v2(74.4,32.2) 74.4,33.8 74.6,34 75.1,34 75.4,34.3 75.4,35.4 75.6,35.6 75.9,35.6 76.3,35.2 76.6,35.2 76.8,35.4 76.8,36.8 77,37 77.3,37 77.7,36.6 78,36.6 78.2,36.8 78.2,38.2 78.4,38.4 78.7,38.4 79.1,38 79.4,38 79.6,38.2 79.6,61 80.1,61.5 80.1,67.675 78.825,68.95 77.375,70.4 v4(76.425,70.4) v4@76.4,70.4
ETH0_TXEN_PB07: U5.A5 U11.19 | length 50.2
  L1 - Top Layer w0.125: v2(69.7,29.2) 71.785,29.2 U11.19@72.735,28.25 ; U5.A5@74.775,68.125 74.775,66.725 v4(74.9,66.6)
  L4 - Bottom Layer w0.125: v2(69.7,29.2) 69.7,49.5 70,49.8 70.5,49.8 70.8,49.5 70.8,47.6 71.1,47.3 71.7,47.3 74.2,49.8 74.2,65.9 v4(74.9,66.6)
ETH_LED: J5.11 R129.2 U11.23 | length 34.2
  L1 - Top Layer w0.2: J5.11@72.385,6 61.9,16.485 61.9,21.085 67.04,26.225 72.71,26.225 U11.23@72.735,26.25
  L4 - Bottom Layer w0.2: R129.2@72,7.65 72.385,7.265 J5.11@72.385,6
ETH_RX_N: J5.6 U11.3 | length 22.5
  L1 - Top Layer w0.1: J5.6@70.505,19.79 69.39,19.79 68.5,18.9 68.5,18.7 68.6,18.6 70.3,18.6 70.7,18.2 70.7,16.5 71.1,16.1 73.4,16.1 73.9,16.6 73.9,17.976 73.576,18.3 72.376,18.3 71.6,19.076 71.6,20.524 72.376,21.3 73.935,21.3 74.535,21.9 74.535,24.765 74.435,24.865 U11.3@74.435,25.05
ETH_RX_P: J5.3 U11.4 | length 22.5
  L1 - Top Layer w0.1: J5.3@66.695,17.25 67.745,18.3 70,18.3 70.4,17.9 70.4,16.376 70.976,15.8 73.524,15.8 74.2,16.476 74.2,18.1 73.7,18.6 72.5,18.6 71.9,19.2 71.9,20.4 72.5,21 74.059,21 74.835,21.776 74.835,24.735 74.935,24.835 U11.4@74.935,25.05
ETH_TX_N: J5.2 U11.5 | length 22.6
  L1 - Top Layer w0.1: J5.2@65.425,19.79 65.439,19.776 65.439,17.8 65.6,17.639 65.6,16.724 67.024,15.3 74,15.3 75.535,16.835 75.535,24.765 75.435,24.865 U11.5@75.435,25.05
ETH_TX_P: J5.1 U11.6 | length 22.6
  L1 - Top Layer w0.1: J5.1@64.155,17.25 64.41,17.25 64.86,17.7 65.115,17.7 65.3,17.515 65.3,16.6 66.9,15 74.124,15 75.835,16.711 75.835,24.735 75.935,24.835 U11.6@75.935,25.05
ETH_XI: R126.1 R132.2 R133.1 TP4.1 U11.8 | length 5.4
  L1 - Top Layer w0.3: U11.8@76.635,26.25 77.865,26.25 R133.1@77.965,26.15 R132.2@77.965,25.15 77.965,24.885 78.715,24.135 R126.1@78.715,23.75 78.765,23.8 TP4.1@80.015,23.8
ETH_XO: R128.1 U11.7 | length 2.4
  L1 - Top Layer w0.3: U11.7@76.635,25.75 76.635,24.83 R128.1@77.715,23.75
EXT40_CLK1_PC31: J16.29 R86.1 | length 98.2
  L1 - Top Layer w0.125: R86.1@85.05,26.45 88,29.4 92,29.4 93.9,31.3 v2(101.1,31.3) ; v2(101.1,47.3) 104.1,47.3 121.1,64.3 v2(139.4,64.3)
  L4 - Bottom Layer w0.125: v2(101.1,31.3) v2(101.1,47.3) ; v2(139.4,64.3) 139.4,74.04 J16.29@145.83,80.47
EXT40_CLK2_PB13: J16.31 R66.2 | length 72.1
  L1 - Top Layer w0.125: R66.2@84.85,63.1 85.4,63.1 89.5,59 106.1,59 107.9,60.8 110.9,60.8 119.8,69.7 140.224,69.7 v2@140.3,69.624
  L4 - Bottom Layer w0.125: v2(140.3,69.7) 140.3,72.4 J16.31@145.83,77.93
EXT40_GP5: J16.16 U6.14 | length 150.4
  L1 - Top Layer w0.125: U6.14@37.65,51.485 37.65,50.561 43.311,44.9 81.373,44.9 85.373,48.9 104.959,48.9 121.189,65.13 v2(137.9,65.13)
  L4 - Bottom Layer w0.125: v2(137.9,65.13) 137.9,89.6 145.2,96.9 147.02,96.9 J16.16@148.37,98.25
EXT40_GP6: J16.18 U6.15 | length 147.3
  L1 - Top Layer w0.125: U6.15@38.15,51.485 38.15,50.861 43.711,45.3 81.207,45.3 85.207,49.3 104.591,49.3 120.964,65.673 v2@138.7,65.673
  L4 - Bottom Layer w0.125: v2(138.7,65.7) 138.7,88.4 144.8,94.5 147.16,94.5 J16.18@148.37,95.71
EXT40_GP7: J16.37 U6.16 | length 120.5
  L1 - Top Layer w0.125: U6.16@39.115,52.45 39.115,50.996 44.361,45.75 80.95,45.75 85,49.8 104.384,49.8 120.757,66.173 v2(141.7,66.173)
  L4 - Bottom Layer w0.125: v2(141.7,66.173) 141.7,66.18 J16.37@145.83,70.31
EXT40_GPIO_PA02: J16.11 R32.1 | length 62
  L1 - Top Layer w0.125: R32.1@93.25,82.5 126.4,82.5 143.3,99.4 143.3,100.8 J16.11@145.83,103.33
EXT40_GPIO_PA03: J16.15 R39.1 | length 60.1
  L1 - Top Layer w0.125: v2(94.001,80.001) 127.581,80.001 J16.15@145.83,98.25
  L4 - Bottom Layer w0.125: R39.1@93.25,80 v2(94.001,80.001)
EXT40_GPIO_PA04: J16.13 R41.1 | length 61
  L1 - Top Layer w0.125: R41.1@93.25,80.5 125.54,80.5 J16.13@145.83,100.79
EXT40_GPIO_PA14: J16.22 R59.1 | length 66.5
  L1 - Top Layer w0.125: R59.1@93.251,69.5 113.1,69.5 118.1,74.5 135,74.5 v2(143.2,82.7)
  L4 - Bottom Layer w0.125: v2(143.2,82.7) 143.2,87.2 145.3,89.3 147.04,89.3 J16.22@148.37,90.63
EXT40_GPIO_PB24: J16.36 R82.1 | length 104.1
  L1 - Top Layer w0.125: R82.1@84.85,53.1 86.1,53.1 87.4,51.8 105.638,51.8 120.538,66.7 v2(135.2,66.7)
  L4 - Bottom Layer w0.125: v2(135.2,66.7) 142.5,59.4 142.5,50.6 143.1,50 146.6,50 147.1,50.5 147.1,71.58 J16.36@148.37,72.85
EXT40_I2SCK_PB19: J16.12 R69.1 | length 104.1
  L1 - Top Layer w0.125: R69.1@82.95,60.6 87.1,60.6 89.2,58.5 109.2,58.5 119.9,69.2 v2(137.1,69.2)
  L4 - Bottom Layer w0.125: v2(137.1,69.2) 137.1,90.9 138.2,92 138.2,93 137.1,94.1 137.1,94.9 137.8,95.6 138.8,95.6 139.9,94.5 141.1,94.5 141.8,95.2 141.8,96.7 143.8,98.7 143.8,101.3 144.6,102.1 147.14,102.1 J16.12@148.37,103.33
EXT40_I2SDIN_PB21: J16.38 R74.1 | length 105.2
  L1 - Top Layer w0.125: R74.1@84.85,56.1 86.6,56.1 87,56.5 109.066,56.5 120.166,67.6 142.4,67.6 144.6,65.4 144.6,63.6 143.4,62.4 143.4,60.9 143.9,60.4 143.9,58.4 143.4,57.9 143.4,51.2 143.9,50.7 147.4,50.7 147.7,51 147.7,66.6 147.2,67.1 147.2,69.14 J16.38@148.37,70.31
EXT40_I2SDOUT_PB22: J16.40 R77.1 | length 105.1
  L1 - Top Layer w0.125: R77.1@82.95,54.6 86.1,54.6 87.5,56 109.273,56 120.473,67.2 141.8,67.2 143.8,65.2 143.8,63.8 142.7,62.7 142.7,50.76 143.36,50.1 147.8,50.1 148.37,50.67 J16.40@148.37,67.77
EXT40_I2SMCK_PB23: J16.7 R80.1 | length 102.1
  L1 - Top Layer w0.125: R80.1@82.95,57.6 87.7,57.6 88.3,57 109,57 120.1,68.1 v2(135.7,68.1) ; v2(135.7,92.614) 142.5,99.414 142.5,105.08 J16.7@145.83,108.41
  L4 - Bottom Layer w0.125: v2(135.7,68.1) v2(135.7,92.614)
EXT40_I2SWS_PB20: J16.35 R71.1 | length 105.6
  L1 - Top Layer w0.125: R71.1@84.85,59.1 87.7,59.1 88.8,58 109.266,58 119.866,68.6 142.2,68.6 145.6,65.2 145.6,60.5 145.1,60 145.1,59.2 145.4,58.9 145.4,57.8 144.8,57.2 144.8,55.8 145.4,55.2 145.4,53.8 144.8,53.2 144.8,52.1 145.3,51.6 146.1,51.6 146.6,52.1 146.6,65.4 144.5,67.5 144.5,71.52 J16.35@145.83,72.85
EXT40_NPCS1_PA07: J16.24 R43.1 | length 59.3
  L1 - Top Layer w0.125: v2(94.051,78) 127,78 135.9,86.9 147.18,86.9 J16.24@148.37,88.09
  L4 - Bottom Layer w0.125: R43.1@93.25,78 v2(94.051,78)
EXT40_NPCS2_PA08: J16.26 R45.1 | length 58.9
  L1 - Top Layer w0.125: R45.1@93.25,76.5 127.1,76.5 134.8,84.2 147.02,84.2 J16.26@148.37,85.55
EXT40_PWM0_PB11: J16.32 R60.2 | length 62.8
  L1 - Top Layer w0.125: v2(94.3,60.5) 105,60.5 107.3,62.8 110.7,62.8 119.674,71.774 141.274,71.774 v2(141.3,71.8)
  L4 - Bottom Layer w0.125: R60.2@93.25,60.5 v2(94.3,60.5) ; v2(141.3,71.8) 141.3,72.6 145.3,76.6 147.04,76.6 J16.32@148.37,77.93
EXT40_PWM1_PB12: J16.33 R63.2 | length 58.2
  L1 - Top Layer w0.125: v2(94.3,62) 104.9,62 106.2,63.3 110.5,63.3 119.469,72.269 142.709,72.269 v2(142.74,72.3)
  L4 - Bottom Layer w0.125: R63.2@93.25,62 v2(94.3,62) ; v2@142.7,72.3 v2(142.74,72.3) J16.33@145.83,75.39
EXT40_RXD: J16.10 U16.5 | length 37.1
  L1 - Top Layer w0.15: U16.5@122.25,89.325 122.25,90.3 122.575,90.625 128.3,90.625 130.45,92.775 v2(130.45,96.675)
  L4 - Bottom Layer w0.125: v2(130.45,96.675) 139.175,96.675 141.8,99.3 141.8,101.4 145,104.6 147.1,104.6 J16.10@148.37,105.87
EXT40_SPI_MISO_PA11: J16.21 R51.1 | length 65.3
  L1 - Top Layer w0.125: v2(94.001,69) 113.307,69 118.307,74 135.7,74 v2(142.1,80.4)
  L4 - Bottom Layer w0.125: R51.1@93.251,69 v2(94.001,69) ; v2(142.1,80.4) 142.1,86.9 J16.21@145.83,90.63
EXT40_SPI_MOSI_PA12: J16.19 R54.1 | length 63.9
  L1 - Top Layer w0.125: R54.1@93.251,72.5 115.11,72.5 117.81,75.2 132.5,75.2 v2(140,82.7)
  L4 - Bottom Layer w0.125: v2(140,82.7) 140,87.34 J16.19@145.83,93.17
EXT40_SPI_SCLK_PA13: J16.23 R57.1 | length 60
  L1 - Top Layer w0.125: v2(94.001,74) 115.761,74 117.561,75.8 127.9,75.8 135.5,83.4 v2(143.85,83.4)
  L4 - Bottom Layer w0.125: R57.1@93.25,74 v2(94.001,74) ; v2(143.85,83.4) 143.85,86.11 J16.23@145.83,88.09
EXT40_TWCK: J16.5 R78.2 | length 67.6
  L1 - Top Layer w0.125: v2(94,84) 125.494,84 141,99.506 141,106.12 J16.5@145.83,110.95
  L4 - Bottom Layer w0.125: R78.2@93.25,84 v2(94,84)
EXT40_TWD: J16.3 R68.2 | length 72.7
  L1 - Top Layer w0.125: R68.2@93.25,83.5 125.701,83.5 141.6,99.399 141.6,105.9 145.4,109.7 146.7,109.7 147.2,110.2 147.2,112.12 J16.3@145.83,113.49
EXT40_TXD: J16.8 U16.6 | length 39.5
  L1 - Top Layer w0.15: U16.6@121.75,89.325 121.75,90.6 122.325,91.175 127.725,91.175 129.575,93.025 v2(129.575,97.2)
  L4 - Bottom Layer w0.125: v2(129.575,97.2) 138.5,97.2 140.7,99.4 140.7,102.5 145.3,107.1 147.06,107.1 J16.8@148.37,108.41
EXT_5V: C1.1 J1.1 U1.1 U1.7 | length 2.9
  L1 - Top Layer w2: J1.1@13.8,40 16.7,40
FLEXCOM0_IO0_PA00: R62.1 R64.1 R67.1 R68.1 U5.P2 | length 22.3
  L1 - Top Layer w0.125: U5.P2@76.725,76.575 77.05,76.9 87.2,76.9 91.4,81.1 91.4,82.55 R68.1@92.35,83.5 R67.1@92.35,84.5 ; R67.1@92.35,84.5 R62.1@92.35,86.5
FLEXCOM0_IO1_PA01: R61.1 R73.1 R76.1 R78.1 U5.M3 | length 24.6
  L1 - Top Layer w0.125: U5.M3@76.087,75.275 U5.M3@76.075,75.275 v4(76.4,75.6)
  L2 - GND w0.125: v4(76.4,75.6) v4@76.418,75.582
  L4 - Bottom Layer w0.125: v4@76.418,75.582 77.982,75.582 79,76.6 87.9,76.6 88.4,77.1 88.4,78.5 89.6,79.7 89.6,81.25 R78.1@92.35,84 R73.1@92.35,86 R61.1@92.35,87
FLEXCOM5_IO0_TX_PA22: R156.2 R158.2 U5.G1 | length 41
  L1 - Top Layer w0.125: U5.G1@77.375,72.025 82.175,72.025 v3(84.8,69.4) ; R158.2@84.95,41.6 84.95,42.15 v3(85.1,42.3) ; R156.2@85.05,37.8 85.05,38.45 v3(85.1,38.5)
  L4 - Bottom Layer w0.125: v3(84.8,69.4) 84.8,42.6 v3(85.1,42.3) v3(85.1,38.5)
FLEXCOM5_IO1_RX_PA21: R157.2 R159.2 U5.G6 | length 44.6
  L1 - Top Layer w0.125: U5.G6@74.125,72.025 v4(74.45,71.7) ; v2(79,41.7) 82.55,41.7 84.2,40.05 84.4,40.05 ; R159.2@84.95,40.6 84.4,40.05 ; R157.2@85.05,36.8 84.4,37.45 84.4,40.05
  L4 - Bottom Layer w0.1: 75.659,70.725 75.925,70.725 76.1,70.55 76.1,70.2 76.225,70.075 76.516,70.075
  L4 - Bottom Layer w0.125: v4(74.45,71.7) 74.45,70.95 74.675,70.725 75.659,70.725 ; 76.516,70.075 77.185,70.075 79.7,67.56 79.7,62.3 79,61.6 v2(79,41.7)
FLEXCOM5_IO3_BT_CTS_PA08: R44.1 R171.2 | length 87.5
  L1 - Top Layer w0.125: R44.1@93.25,75.5 v2(114.5,75.5) ; v2(126.8,31.3) 131.45,31.3 R171.2@133.2,29.55
  L4 - Bottom Layer w0.125: v2(114.5,75.5) 114.6,75.5 126.9,63.2 126.9,41.6 126.5,41.2 125.8,41.2 125.5,40.9 125.5,40.4 125.8,40.1 126.5,40.1 126.8,39.8 126.8,39.3 126.5,39 125.8,39 125.5,38.7 125.5,38.2 125.8,37.9 126.5,37.9 126.8,37.6 126.8,37.1 126.5,36.8 125.8,36.8 125.5,36.5 125.5,36 125.8,35.7 126.5,35.7 126.8,35.4 126.8,34.9 126.5,34.6 125.8,34.6 125.5,34.3 125.5,33.8 125.8,33.5 126.5,33.5 126.8,33.2 126.8,32.7 126.5,32.4 125.8,32.4 125.5,32.1 125.5,31.5 125.7,31.3 v2(126.8,31.3)
FLEXCOM5_IO4_BT_RTS_PA07: R42.1 R173.2 | length 78.8
  L1 - Top Layer w0.125: v2(94.001,79.001) v2@113.1,79.001 ; v2(128,30.7) 130.85,30.7 R173.2@132,29.55
  L4 - Bottom Layer w0.125: R42.1@93.25,79 v2(94.001,79.001) ; v2(113.1,79) 128,64.1 128,63 128,32.3 v2(128,30.7)
FLEXCOM6_TWCK_PA31: R83.1 R93.1 R94.1 R95.1 R96.1 U5.H4 | length 71.5
  L1 - Top Layer w0.125: R95.1@46.15,46.5 R96.1@46.15,48.5 ; R83.1@46.15,50.5 R96.1@46.15,48.5 ; U5.H4@75.425,72.675 v4(75.75,72.35) ; v2@83.5,50 83,50 80.962,47.962 46.687,47.962 R96.1@46.15,48.5
  L4 - Bottom Layer w0.1: 75.925,72.35 76.186,72.089
  L4 - Bottom Layer w0.125: v4(75.75,72.35) 75.925,72.35 ; 76.186,72.089 76.3,71.975 81.225,71.975 83.6,69.6 83.6,50.1 v2@83.5,50
  other v2: 83.6,50
FLEXCOM6_TWD_PA30: R84.1 R87.1 R89.1 R90.1 R92.1 U5.G2 | length 70.9
  L1 - Top Layer w0.125: R84.1@46.15,55.5 R90.1@46.15,51.5 48.75,48.9 80.619,48.9 82.719,51 v2(84.2,51) ; U5.G2@76.725,72.025 77.05,71.7 81.7,71.7 84,69.4 v3@84.1,69.4
  L4 - Bottom Layer w0.125: v3@84.1,69.4 84.2,69.3 v2(84.2,51)
  other v3: 84.2,69.4
FTDI_CTS: J24.6 R261.2 TP10.1 | length 6.3
  L1 - Top Layer w0.125: TP10.1@0.825,104.4 4.45,104.4 J24.6@4.4,104.45
  L4 - Bottom Layer w0.125: R261.2@1.85,104.4 4.35,104.4 J24.6@4.4,104.45
FTDI_RTS: J24.2 R262.2 TP11.1 | length 6
  L1 - Top Layer w0.125: TP11.1@0.975,114.6 TP11.1@1,114.6 4.41,114.6 J24.2@4.4,114.61
  L4 - Bottom Layer w0.125: R262.2@1.85,114.6 4.39,114.6 J24.2@4.4,114.61
FTDI_RX: J24.4 R264.1 U30.1 | length 7.6
  L4 - Bottom Layer w0.125: R264.1@1.85,109.5 4.37,109.5 J24.4@4.4,109.53 9.255,109.53 U30.1@9.35,109.625
FTDI_TX: J24.5 R263.1 U30.8 | length 7.5
  L4 - Bottom Layer w0.125: R263.1@1.85,107 4.39,107 9.325,107 U30.8@9.35,106.975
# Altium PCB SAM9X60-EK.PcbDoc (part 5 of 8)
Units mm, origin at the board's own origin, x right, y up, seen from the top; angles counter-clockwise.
Board outline 150 x 125 mm, 4 copper layers (L1 - Top Layer, L2 - GND, L3 - PWR, L4 - Bottom Layer), stack 1.52 mm thick; 566 components, 500 nets, 2132 pads, 1038 vias.

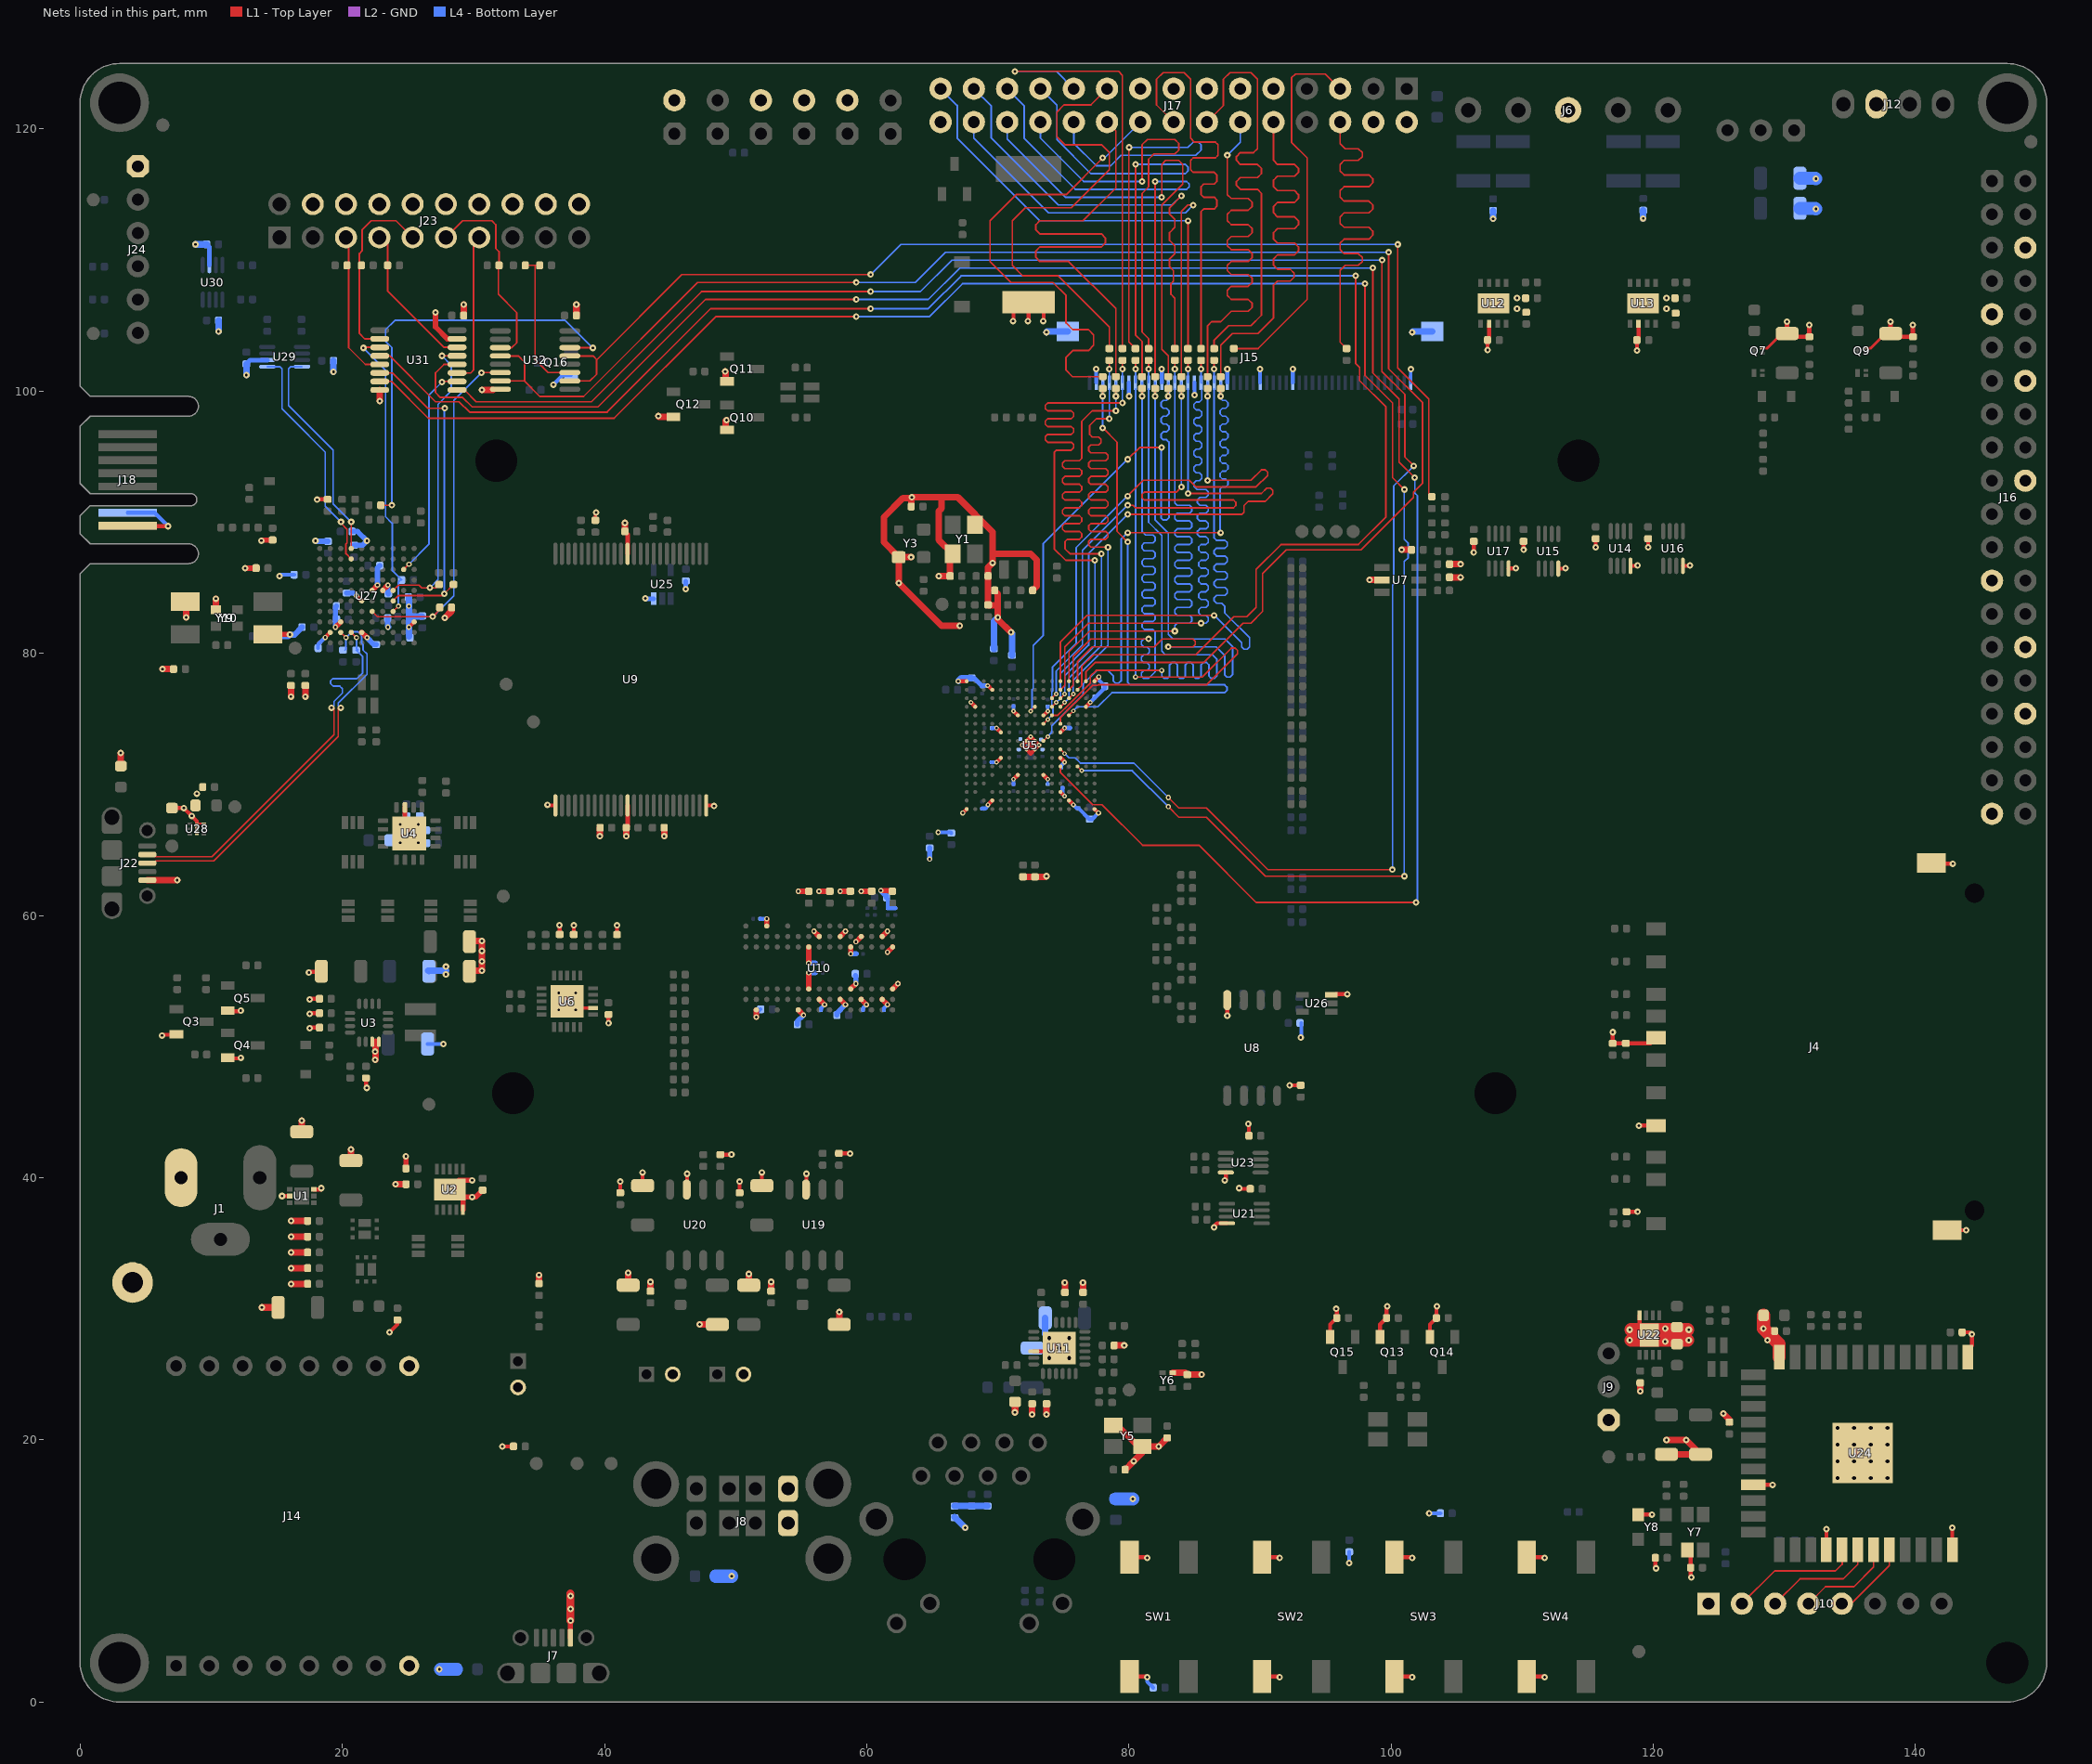
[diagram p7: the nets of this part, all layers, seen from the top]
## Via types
v1: diameter 0.5, hole 0.2, L1 - Top Layer to L4 - Bottom Layer, tented both sides, 483 vias
v2: diameter 0.5, hole 0.2, L1 - Top Layer to L4 - Bottom Layer, 268 vias
v3: diameter 0.4, hole 0.2, L1 - Top Layer to L4 - Bottom Layer, tented both sides, 145 vias
v4: diameter 0.35, hole 0.15, L1 - Top Layer to L4 - Bottom Layer, tented both sides, 121 vias
v5: diameter 0.55, hole 0.3, L1 - Top Layer to L4 - Bottom Layer, tented bottom, 16 vias
v6: diameter 0.559, hole 0.305, L1 - Top Layer to L4 - Bottom Layer, 5 vias

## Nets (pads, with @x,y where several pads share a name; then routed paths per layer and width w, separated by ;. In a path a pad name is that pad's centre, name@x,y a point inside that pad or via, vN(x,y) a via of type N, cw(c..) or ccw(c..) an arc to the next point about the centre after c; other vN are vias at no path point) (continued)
GND: C1.2 C2.2 C3.2 C4.2 C5.1 C6.1 C7.2 C8.2 C9.2 C10.2 C11.2 C12.2 C13.1 C14.1 C15.1 C16.1 C17.2 C18.2 C19.2 C20.2 C21.2 C22.2 C23.2 C24.2 C25.2 C26.2 C27.2 C28.1 C29.1 C31.1 C32.2 C33.2 C34.2 C35.1 C36.2 C37.2 C38.2 C39.1 C40.1 C41.2 C42.2 C43.2 C44.2 C45.2 C46.2 C47.1 C48.2 C49.2 C50.2 C51.2 C52.2 C53.2 C54.2 C55.2 C56.2 C57.1 C58.2 C59.2 C60.2 C61.2 C62.1 C64.2 C65.1 C66.1 C67.1 C68.1 C69.2 C70.2 C71.1 C72.1 C73.1 C74.1 C75.2 C76.2 C77.2 C78.1 C79.1 C80.1 C81.1 C82.1 C85.2 C86.2 C87.2 C88.2 C89.2 C90.2 C91.2 C92.2 C93.2 C94.1 C95.2 C96.2 C97.1 C98.1 C99.2 C100.2 C101.1 C102.2 C103.2 C104.2 C105.2 C106.1 C113.2 C114.2 C115.2 C116.2 C117.2 C118.2 C119.2 C120.2 C121.2 C122.2 C123.2 C124.2 C125.2 C126.2 C127.1 C128.1 C129.2 C130.2 C131.2 C132.2 C133.2 C134.1 C135.2 C136.2 C137.1 C138.1 C139.1 C140.1 C143.2 C144.2 C145.2 C146.1 C147.1 C148.1 C149.1 C150.2 C151.2 C152.2 C153.2 C154.1 C155.2 C156.1 C157.1 C158.1 C159.1 C160.1 C161.1 C162.1 C163.2 C164.2 C165.2 C166.2 C167.2 C168.2 C169.1 C170.1 C171.2 C172.1 C173.1 C174.1 C175.1 C176.2 C177.1 C178.1 C179.2 FB3.2 FB5.2 FB7.2 FB13.2 J1.2 J3.2 J4.3 J4.6 J4.12 J6.3 J7.5 J8.4 J8.8 J9.1 J10.1 J12.3 J13.2 J14.8 J14.9 J15.2 J15.7 J15.12 J15.17 J15.22 J15.27 J15.32 J15.50 J15.MNT J16.6 J16.9 J16.14 J16.20 J16.25 J16.30 J16.34 J16.39 J17.2 J17.4 J17.9 J17.11 J17.13 J17.15 J17.17 J17.30 J18.2 J18.3 J20.2 J21.2 J22.5 J23.4 J23.6 J23.8 J23.10 J23.12 J23.14 J23.16 J23.18 J23.20 J24.1 Q3.2 Q4.2 Q5.2 Q7.2 Q9.2 Q10.2 Q11.2 Q12.2 Q13.2 Q14.2 Q15.2 Q16.2 R2.1 R3.1 R5.1 R6.2 R14.1 R23.1 R28.2 R47.1 R48.1 R49.1 R104.2 R105.2 R117.1 R118.1 R119.1 R121.1 R124.1 R127.2 R131.1 R150.1 R153.1 R155.1 R174.2 R179.1 R183.1 R196.2 R202.2 R207.2 R240.1 R250.2 SW1.3 SW1.4 SW2.3 SW2.4 SW3.3 SW3.4 SW4.3 SW4.4 TP1.1 U1.2 U1.6 U2.5 U2.11 U3.3 U3.4 U4.3 U4.17 U5.A1 U5.A16 U5.B4 U5.B13 U5.C5 U5.E7 U5.E10 U5.G5 U5.G12 U5.H8 U5.H9 U5.J8 U5.J9 U5.K5 U5.K12 U5.M7 U5.M10 U5.N2 U5.N15 U5.R13 U5.T1 U5.T16 U6.17 U6.21 U7.2 U8.4 U9.13 U9.25 U9.36 U9.48 U10.A3 U10.A7 U10.B2 U10.B8 U10.D2 U10.D8 U10.E3 U10.E7 U10.F2 U10.F8 U10.H2 U10.H8 U10.J3 U10.J7 U10.K9 U10.N1 U10.P9 U11.22 U11.25 U12.2 U12.9 U13.2 U13.9 U14.4 U15.4 U16.4 U17.4 U19.3 U20.3 U21.4 U22.4 U22.9 U23.4 U24.1 U24.13 U24.21 U24.28 U24.36 U24.37 U25.3 U26.3 U27.B2 U27.C3 U27.E2 U27.E5 U27.F6 U27.G6 U27.K3 U28.3 U28.7 U29.2 U30.2 U31.8 U31.15 U32.8 Y1.2 Y1.4 Y3.2 Y5.2 Y5.4 Y6.2 Y7.2 Y8.2 Y9.2 Y9.4 Y10.2 | length 368.9
  L1 - Top Layer w0.2: U28.7@8.9,67 9.2,67 U28.3@9.425,67 ; v4(69.225,77.55) v4@69.25,77.55 ; U5.M7@73.475,75.275 U5.M7@73.496,75.275
  L1 - Top Layer w0.22: Q7.2@128.325,103.287 128.687,103.287 129.8,104.4 C138.1@130.2,104.4 ; Q9.2@136.225,103.288 136.587,103.287 137.7,104.4 C137.1@138.1,104.4
  L1 - Top Layer w0.25: v1(35.65,68.45) 35.7,68.4 U9.25@36.25,68.4 ; v1(37.15,53.45) 37.65,52.95 U6.17@39.115,52.95 ; R117.1@39.3,90.15 39.3,90.7 v1(39.35,90.75) ; U9.48@47.75,68.4 48.3,68.4 v1(48.35,68.35) ; v4(71.2,75.6) v4@71.2,75.625
  L1 - Top Layer w0.3: J18.2@3.625,89.73 3.655,89.7 v1(6.7,89.7) ; v1(6.25,50.85) 6.3,50.9 Q3.2@7,50.9 ; C171.2@7,68.2 v1(7.9,68.2) v1(8.5,67.6) 8.9,67.2 8.9,67 U28.7@8.9,66.6 ; Q4.2@11.5,49.1 12.2,49.1 v1(12.25,49.15) ; Q5.2@11.5,52.7 12.2,52.7 v1(12.25,52.75) ; v1(15.4,38.6) U1.2@15.975,38.6 ; v1(17.45,55.65) 17.5,55.7 C22.2@18.2,55.7 ; v1(17.5,51.4) 17.55,51.45 C19.2@18.25,51.45 ; v1(17.5,52.5) 17.55,52.55 C17.2@18.25,52.55 ; v1(17.5,53.6) 17.55,53.65 C20.2@18.25,53.65 ; U1.6@17.825,39.1 v1@18.4,39.1 ; v1(18.075,91.725) 18.1,91.75 C148.1@18.875,91.75 ; v3(18.688,81.213) U27.B2@19.075,81.6 ; v3(21.075,84.4) U27.E5@21.475,84 ; C18.2@21.8,47.6 21.8,46.9 v1(21.85,46.85) ; v1(23.6,28.2) 24.2,28.8 C106.1@24.2,29.15 ; v3(25.075,82) U27.K3@25.475,82.4 ; v1(32.2,19.5) C7.2@33.05,19.5 ; R47.1@36.569,58.556 v1(36.569,59.256) ; R48.1@37.65,58.55 v1(37.65,59.25) ; v1(40.3,51.8) C53.2@40.3,52.45 ; R49.1@40.95,58.55 v1(40.95,59.25) ; C124.2@41.2,38.85 v1(41.2,39.7) ; C123.2@42.9,39.4 v1(42.9,40.4) ; U20.3@46.3,39.3 v1(46.3,40.3) ; R155.1@48.83,41.76 v1(49.68,41.76) ; C118.2@50.3,38.85 v1(50.3,39.7) ; C117.2@52,39.4 v1(52,40.4) ; U19.3@55.4,39.3 v1(55.4,40.3) ; R153.1@57.875,41.85 v1(58.725,41.85) ; v3(66.975,77.875) U5.T16@67.625,77.875 ; v3(67.325,67.825) U5.A16@67.625,68.125 ; v4(67.95,76.25) U5.N15@68.275,75.925 ; v4(69.25,68.45) U5.B13@69.575,68.775 ; v4@69.25,77.55 U5.R13@69.575,77.225 ; v4(69.9,71.7) U5.G12@70.225,72.025 ; v4(69.9,74.3) U5.K12@70.225,73.975 ; v1(71.15,105.35) 71.2,105.4 C23.2@71.2,106.8 ; v4(71.2,70.4) U5.E10@71.525,70.725 ; v4(71.2,75.6) U5.M10@71.525,75.275 ; v1(72.3,105.35) 72.35,105.4 C23.2@72.35,106.8 ; U11.22@72.735,26.75 74.435,26.75 v6(74.685,27) ; U5.H8@72.825,72.675 v4(73.15,73) U5.J8@72.825,73.325 ; v1(73.45,105.35) 73.5,105.4 C23.2@73.5,106.8 ; U5.E7@73.475,70.725 v4(73.8,70.4) ; U5.M7@73.496,75.275 v4(73.803,75.582) ; U5.C5@74.775,69.425 v4(75.1,69.1) ; U5.K5@74.775,73.975 v4(75.1,74.3) ; U5.B4@75.425,68.775 v4(75.75,68.45) ; U5.N2@76.725,75.925 v4(77.05,76.25) ; U5.A1@77.375,68.125 v3(77.675,67.825) ; U5.T1@77.375,77.875 v3(77.7,78.2) v3@77.725,78.225 ; SW1.4@80.05,1.95 81.35,1.95 v2(81.4,1.9) ; SW1.3@80.05,11.05 81.35,11.05 v2(81.4,11) ; v1@86.5,36.3 86.719,36.519 U21.4@87.475,36.519 ; v1(87.299,39.8) 87.386,39.886 U23.4@87.386,40.4 ; v2(87.5,52.35) U8.4@87.5,53.2 ; v1@88.4,39.2 88.45,39.15 C125.2@89.25,39.15 ; v1(89.099,44.1) 89.15,44.05 C129.2@89.15,43.2 ; SW2.4@90.15,1.95 91.45,1.95 v2(91.5,1.9) ; SW2.3@90.15,11.05 91.45,11.05 v2(91.5,11) ; v2(92.25,47.05) C55.2@93.1,47.05 ; Q15.2@95.35,27.85 95.35,28.8 R207.2@95.85,29.3 95.85,29.95 v1(95.799,30) ; U26.3@95.8,54 v2(96.65,54) ; Q13.2@99.15,27.85 99.15,28.8 R196.2@99.65,29.3 99.65,30.151 v1(99.699,30.2) ; SW3.4@100.25,1.95 101.55,1.95 v2(101.6,1.9) ; SW3.3@100.25,11.05 101.55,11.05 v2(101.6,11) ; Q14.2@102.95,27.85 102.95,28.8 R202.2@103.45,29.3 v1@103.45,30.151 ; v2(106.3,87.7) C105.2@106.3,88.55 ; v2(107.362,103.138) 107.35,103.15 C96.2@107.35,103.9 107.475,104.025 U12.2@107.475,105.15 ; U17.4@108.95,86.475 109.475,86.475 v2(109.5,86.5) ; v2(110.1,87.9) C103.2@110.1,88.55 ; SW4.4@110.35,1.95 111.65,1.95 v2(111.7,1.9) ; SW4.3@110.35,11.05 111.65,11.05 v2(111.7,11) ; U15.4@112.75,86.465 113.275,86.465 v2(113.3,86.49) ; v2(115.6,88.1) C102.2@115.6,88.75 ; v2(116.9,51.1) C56.2@116.9,50.25 119.775,50.25 J4.3@120.2,50.675 ; R118.1@117.95,37.4 v2(118.8,37.4) ; U14.4@118.25,86.675 118.775,86.675 v2(118.8,86.7) ; v2(118.75,103.1) C100.2@118.75,103.9 118.875,104.025 U13.2@118.875,105.15 ; Y8.2@118.85,14.3 v2(119.9,14.3) ; v2(118.9,43.975) J4.6@119.75,43.975 ; U22.4@118.95,29.5 118.95,28.75 119.3,28.4 U22.9@119.7,28 ; v2(119.6,88.1) C104.2@119.6,88.75 ; C136.2@120.15,11 120.15,10.25 v2(120.2,10.2) ; U16.4@122.25,86.675 122.775,86.675 v2(122.8,86.7) ; Y7.2@122.6,11.6 122.85,11.35 122.85,9.55 v2(122.9,9.5) ; U24.21@127.62,16.57 v2(129.1,16.57) v2@129.19,16.57 ; U24.28@133.2,11.63 v2(133.2,13.2) ; J4.12@142,63.95 v2(142.85,63.95) ; U24.36@142.8,11.63 v2(142.8,13.3) ; J4.12@143,36 v2(143.85,36) ; R174.2@143.55,28.2 144.15,28.2 v2(144.3,28.05) U24.1@144.3,27.2 ; U5.H9@72.175,72.675 v4(71.85,73) U5.J9@72.175,73.325 ; U5.H9@72.175,72.675 72.5,72.35 U5.H8@72.825,72.675 72.5,73 ; U5.H9@72.175,72.675 72.5,73 ; U5.J9@72.175,73.325 v4(72.5,73.65) U5.J8@72.825,73.325 ; U5.J9@72.175,73.325 72.5,73 ; 72.5,73 U5.J8@72.825,73.325
  L1 - Top Layer w0.35: U4.3@24.775,68.25 24.775,66.575 v1(25.1,66.25) ; C58.2@41.55,89.3 41.75,89.1 U9.13@41.75,87.6 ; C60.2@41.65,66.7 41.75,66.8 U9.36@41.75,68.4 ; U5.G5@74.775,72.025 v4(75.1,71.7) ; v1(130.2,105.3) C138.1@130.2,104.4 130.45,104.15 R179.1@131.9,104.15 v1(131.9,105.05) ; v1(138.1,105.3) C137.1@138.1,104.4 138.35,104.15 R183.1@139.8,104.15 v1(139.8,105.05)
  L1 - Top Layer w0.4: v1(12.575,86.5) C152.2@13.425,86.5 ; v1(13.825,88.6) 13.875,88.65 C149.1@14.675,88.65 ; Y9.4@14.325,81.45 15.975,81.45 v1(16,81.425) ; v3(19.475,82) U27.C3@19.875,82.4 ; U27.E2@21.475,81.6 v3(21.875,81.2) ; U27.F6@22.275,84.8 v3(22.675,85.2) ; U27.G6@23.075,84.8 v3(23.475,85.2) ; C6.1@24.85,40.7 v1(24.85,41.625) ; v1(27.1,106) 27.1,104.9 28.005,103.995 U31.15@28.75,103.995 ; U2.11@28.175,39.075 U2.11@28.2,39.1 ; U2.5@29.2,37.55 U2.11@29.2,38.525 ; v1(29.9,39.8) 28.9,39.8 28.85,39.75 U2.11@28.2,39.1 ; R6.2@30.7,39.05 30.175,38.525 v1(29.9,38.525) U2.11@29.2,38.525 ; J7.5@37.4,4.9 v1(37.4,6.2) ; v3@51.575,52.251 U10.P9@51.575,52.8 ; U10.N1@52.375,59.2 v3(52.375,59.75) ; U10.K9@54.775,52.8 v3(55.175,52.4) ; v3(54.775,61.85) C75.2@55.575,61.85 ; U10.J7@55.575,54.4 v3(55.575,55.625) ; v3(55.575,56.375) U10.J3@55.575,57.6 ; v3(55.975,58.8) U10.H2@56.375,58.4 ; v3(56.35,61.85) C70.2@57.175,61.85 ; U10.H8@56.375,53.6 v3(56.775,53.2) ; U10.F8@57.975,53.6 v3(58.375,53.2) ; U10.F2@57.975,58.4 v3(58.375,58.8) ; v3(57.975,61.85) C76.2@58.75,61.85 ; U10.E7@58.775,54.4 v3(59.175,54.8) ; v3(58.775,57.075) U10.E3@58.775,57.6 ; v3(59.175,58) U10.D2@59.575,58.4 ; U10.D8@59.575,53.6 v3@59.975,53.2 ; v3(59.575,61.85) C69.2@60.375,61.85 ; v3(61.075,61.9) 61.9,61.9 C77.2@61.95,61.85 ; U10.B8@61.175,53.6 v3@61.575,53.2 ; U10.B2@61.175,58.4 v3@61.575,58.8 ; v3(61.575,57.2) U10.A3@61.975,57.6 ; U10.A7@61.975,54.4 v3@62.375,54.799 ; U2.11@28.2,39.1 28.775,38.525 U2.11@29.2,38.525
  L1 - Top Layer w0.5: FB13.2@3.1,71.4 v1(3.1,72.4) ; J22.5@5.119,62.7 6.5,62.7 v1(7.4,62.7) ; v1(6.275,78.8) C151.2@7.125,78.8 ; v1(8.075,82.75) Y9.2@8.075,83.6 ; Y10.2@10.35,83.325 v1(10.35,84.175) ; v1(13.85,30.1) C8.2@15.1,30.1 ; v1(16.075,76.7) R240.1@16.075,77.55 ; v1(16.1,31.9) C9.2@17.35,31.9 ; v1(16.1,33.1) R5.1@17.35,33.1 ; v1(16.1,34.3) R3.1@17.35,34.3 ; v1(16.1,35.5) C3.2@17.35,35.5 ; v1(16.1,36.7) R2.1@17.35,36.7 ; C1.2@16.9,43.5 v1(16.9,44.35) ; v1(17.175,76.7) C150.2@17.175,77.55 ; C2.2@20.65,41.3 v1(20.65,42.15) ; v1@22.531,49 22.531,50.368 ; v1(22.85,99.245) U31.8@22.85,100.095 ; v1(24.05,39.5) C5.1@24.7,39.5 ; v1(27.8,82.7) 28.325,83.225 R250.2@28.325,83.5 ; C176.2@29.25,105.77 v1(29.25,106.62) ; C12.2@29.7,55.75 29.75,55.8 v1(30.65,55.8) v1(30.65,56.5) v1(30.65,57.3) v1(30.65,58.05) C11.2@29.7,58.05 ; v1(30.65,100.1) U32.8@31.5,100.1 ; R150.1@35,31.925 v1(35,32.575) ; C179.2@37.85,105.77 v1(37.85,106.62) ; v1(39.65,66.05) C61.2@39.65,66.7 ; C58.2@41.55,89.3 v1(41.55,89.95) ; v1(41.65,66.05) C60.2@41.65,66.7 ; C120.2@41.8,32.1 v1(41.8,32.75) ; C121.2@43.5,31.4 v1(43.5,32.05) ; v1(44.1,98.1) 44.15,98.05 Q12.2@45.25,98.05 ; v1(44.55,66.05) C59.2@44.55,66.7 ; v1(47.25,28.8) C119.2@47.9,28.8 ; v1(49.2,101.5) 49.25,101.45 Q11.2@49.25,100.75 ; Q10.2@49.25,97.05 49.25,97.75 v1(49.3,97.8) ; C114.2@51,32 v1(51,32.65) ; C115.2@52.7,31.4 v1(52.7,32.05) ; C113.2@57.9,29.1 v1(57.9,29.75) ; v1(63.383,87.333) Y3.2@62.435,87.333 ; C29.1@63.387,91.2 63.387,91.85 62.75,91.85 61.3,90.4 61.3,88.468 Y3.2@62.435,87.333 ; v1(63.438,91.9) 65.7,91.9 ; v1(65.5,85.9) C24.2@66.35,85.9 66.35,87.396 Y1.2@66.549,87.595 65.5,88.644 65.5,90.85 65.7,91.05 65.7,91.9 ; v1(67.1,82.1) 65.7,82.1 v1(62.435,85.365) Y3.2@62.435,87.333 ; C27.2@69.75,84.8 70,84.55 70,83.65 ; v1(71,81.6) 70,82.6 v1(70,82.75) 70,83.65 ; v1(71.3,22.099) 71.315,22.114 C85.2@71.315,22.9 ; C62.1@71.925,62.95 R119.1@72.825,62.95 73.65,62.95 v1(73.7,63) ; v1(72.6,21.949) 72.615,21.964 C86.2@72.615,22.75 ; C26.2@72.65,84.8 72.975,85.125 72.975,87.125 72.5,87.6 69.6,87.6 ; v1(73.7,21.949) 73.715,21.964 C88.2@73.715,22.75 ; v1(75.1,32) 75.115,31.985 R127.2@75.115,31.25 ; C90.2@76.5,31.25 v1@76.5,31.985 ; Y5.2@78.815,21.1 79.115,21.1 80.715,19.5 Y5.4@81.015,19.5 ; R124.1@78.865,27.2 v1(79.64,27.2) ; C92.2@79.715,17.725 v1(80.365,18.375) 81.015,19.025 Y5.4@81.015,19.5 ; C91.2@82.915,20.15 v1(82.265,19.5) Y5.4@81.015,19.5 ; Y6.2@83.325,25.125 84.3,25.125 C93.2@84.45,24.975 v1(85.55,24.975) ; v1(98.35,85.6) U7.2@99.2,85.6 ; v1(100.8,87.9) C54.2@101.55,87.9 ; R105.2@104.45,85.8 v1(105.3,85.8) ; R104.2@104.45,86.8 v1(105.3,86.8) ; v1(119,23.7) C128.1@119,24.35 ; C132.2@121,18.9 C131.2@123.6,18.9 v1(122.5,20) v1(121,20) ; v1(125.35,22) 125.8,21.55 C130.2@125.8,21.35 ; 65.7,91.9 66.957,91.9 69.6,89.257 69.6,87.6 ; 69.6,87.6 v1(69.6,86.9) 69.25,86.55 R28.2@69.25,83.7 69.3,83.65 70,83.65
  L1 - Top Layer w0.6: v1(37.4,6.2) v1(37.4,7.1) v1(37.4,8.1) v1@37.4,8.3
  L1 - Top Layer w1: v1@118.3,27.6 v1@122.6,27.6 ; v1@118.3,28.4 119.3,28.4 v1@122.6,28.4 ; C134.1@128.4,29.5 v2(128.4,28.5) 129.6,27.3 U24.13@129.6,26.31
  L4 - Bottom Layer w0.2: C42.2@69.513,74.3 C42.2@69.587,74.3 ; C41.2@73.8,70.012 v4(73.8,70.4)
  L4 - Bottom Layer w0.25: C50.2@73.8,75.962 73.8,75.586 v4(73.803,75.582) ; J15.50@101.5,100.659 v1(101.5,101.675)
  L4 - Bottom Layer w0.3: J18.3@3.625,90.73 5.67,90.73 v1(6.7,89.7) ; v1(15.2,85.9) 15.3,86 C158.1@16.325,86 ; C163.2@18.15,80.4 18.15,80.675 v3(18.688,81.213) ; C155.2@25.025,84.3 25.05,84.275 C155.2@25.075,84.25 ; C10.2@26.5,50.2 v1(27.7,50.2) ; v1(36.1,100.5) 36.85,101.25 Q16.2@37.45,101.25 ; v3@51.575,52.251 51.575,52.525 C68.1@51.9,52.85 ; C73.1@51.9,59.75 v3(52.375,59.75) ; C74.1@56.512,52.8 56.512,52.937 v3(56.775,53.2) ; C72.1@59.712,52.8 59.712,52.938 v3(59.975,53.2) ; C80.1@61.312,52.8 61.312,52.937 v3(61.575,53.2) ; C65.1@61.5,61.375 61.6,61.275 R121.1@61.6,60.562 C66.1@62.175,60.562 ; v3(65.45,66.35) 66.4,66.35 C64.2@66.45,66.3 ; C38.2@68.8,68.163 69.056,68.163 69.25,68.357 v4(69.25,68.45) ; C36.2@69.512,71.7 v4(69.9,71.7) ; C42.2@69.588,74.3 v4(69.9,74.3) ; C37.2@71.2,70.012 v4(71.2,70.4) ; v4(71.2,75.6) C51.2@71.2,75.988 ; C44.2@74.838,71.3 74.838,71.438 v4(75.1,71.7) ; C28.1@74.925,69.738 74.925,69.275 v4(75.1,69.1) v4@75.113,69.1 ; v4(75.75,68.45) 76.012,68.188 C46.2@76.15,68.188 76.987,67.35 C40.1@77,67.35 77.2,67.35 v3(77.675,67.825) ; v4(77.05,76.25) 78.15,77.35 C39.1@78.15,77.5 77.7,77.95 v3(77.7,78.2) ; J15.2@77.5,100.659 v1(77.5,101.7) ; v1(80,99.618) J15.7@80,100.659 ; v2(81.4,1.9) 81.4,1.55 C143.2@81.85,1.1 ; J15.12@82.5,100.659 v1(82.5,101.7) ; v1(85,99.7) J15.17@85,100.659 ; J15.22@87.5,100.659 v1(87.5,101.7) ; J15.27@90,100.659 v1(90,101.7) ; J15.32@92.5,100.659 v1(92.5,101.7) ; v2@93.1,50.8 93.15,50.85 C147.1@93.15,51.8 ; v2(96.8,10.6) C144.2@96.8,11.45 ; v2(102.9,14.4) C145.2@103.75,14.4
  L4 - Bottom Layer w0.35: C177.1@9.65,111.2 9.85,111 U30.2@9.85,109.625 ; C174.1@12.675,102.075 12.975,102.375 U29.2@14.275,102.375 ; v1(43.1,84.2) 43.125,84.175 U25.3@43.75,84.175 ; v1(46.2,84.9) C146.1@46.2,85.525 ; C47.1@68,78.118 68.182,78.118 68.75,77.55 v4(69.225,77.55) ; v4(75.1,74.3) C43.2@75.512,74.3
  L4 - Bottom Layer w0.4: v1(17.95,88.575) 17.975,88.55 C169.1@18.9,88.55 ; v3(19.475,82) 19.475,83.525 C164.2@19.55,83.6 ; C160.1@20.325,84.6 20.875,84.6 v3(21.075,84.4) ; C159.1@20.75,89.3 21.15,89.3 v1(21.875,88.575) 21.55,88.25 C161.1@20.9,88.25 ; v3(21.875,81.2) 22.4,80.675 C168.2@22.575,80.675 ; v3(22.675,85.2) 22.675,86.525 C167.2@22.85,86.7 ; v3(23.475,85.2) 23.475,84.575 C166.2@23.5,84.55 ; C82.1@54.7,51.7 54.7,51.925 v3(55.175,52.4) ; v3(55.575,55.625) C71.1@56.05,55.625 ; v3(55.575,56.375) C79.1@56.05,56.375 ; C81.1@57.725,52.4 57.725,52.55 v3(58.375,53.2) ; v3(58.775,57.075) C78.1@59.188,57.075 ; C67.1@59.125,55.4 59.175,55.35 v3(59.175,54.8) ; v3(61.075,61.9) 61.5,61.475 C65.1@61.5,61.375 ; v3(64.8,64.3) C35.1@64.8,65.15
  L4 - Bottom Layer w0.45: C170.1@14.025,81.3 15.875,81.3 v1(16,81.425) 16.35,81.425 C156.1@16.925,82 ; C157.1@23.45,82.7 23.45,82.075 v3@23.5,82.025
  L4 - Bottom Layer w0.5: v1(8.8,111.2) C177.1@9.65,111.2 ; v1(10.55,104.55) C178.1@10.55,105.4 ; v1(12.675,101.225) C174.1@12.675,102.075 ; v1(19.325,101.475) C175.1@19.325,102.325 ; C162.1@25.075,81.3 v3(25.075,82) 25.075,84.25 C155.2@25.075,84.3 ; C154.1@25.125,82.8 C153.2@26.075,82.8 ; C21.2@26.6,55.75 26.55,55.8 27.9,55.8 ; R131.1@66.7,14.1 v1(67.5,13.3) ; v3@67,77.9 67.218,78.118 C47.1@68,78.118 ; R23.1@69.7,80.35 69.7,82.45 v1(70,82.75) ; v1(71,81.6) 71.075,81.525 C52.2@71.075,79.85 ; C89.2@73.615,29.3 73.615,28.07 v6(73.923,27.762) ; v2(73.7,104.5) 73.759,104.559 J15.MNT@75.35,104.559 ; v2(101.6,104.5) 101.659,104.559 J15.MNT@103.15,104.559 ; v2(107.775,113.15) C94.1@107.775,113.775 ; v2(119.225,113.175) C98.1@119.225,113.8
  L4 - Bottom Layer w1: v1@27.5,2.5 FB5.2@28.7,2.5 ; FB7.2@48.5,9.6 v1(49.7,9.6) ; FB3.2@79,15.5 v1(80.3,15.5) ; C140.1@131.175,113.95 132.35,113.95 v2(132.4,113.9) ; C139.1@131.175,116.25 132.35,116.25 v2(132.4,116.2)
  other v1: 27.4,2.5 120.9,27.5 118.2,27.6 122.7,27.6 118.2,28.4 122.7,28.4 120.9,28.5 103.499,30.2 76.485,32 86.5,36.2 18.4,39.2 88.399,39.2 22.5,49 22.5,49.618 36.5,52.8 37.8,52.8 36.5,54.1 37.8,54.1 27.9,55.5 27.9,56.1 24.4,65.55 25.8,65.55 24.4,66.95 25.8,66.95 8.9,69.3
  other v2: 128.7,27.6 93.1,50.7 109.6,106.3 121,106.3 109.6,107.1 121,107.1
  other v3: 51.575,52.25 62.375,54.8 61.575,58.8 23.475,82 25.075,83.6
  other v5: 134.045,17.095 135.315,17.095 136.585,17.095 137.855,17.095 134.045,18.365 135.315,18.365 136.585,18.365 137.855,18.365 134.045,19.635 135.315,19.635 136.585,19.635 137.855,19.635 134.045,20.905 135.315,20.905 136.585,20.905 137.855,20.905
  other v6: 73.923,26.238 75.447,26.238 75.447,27.762
GND_ETH: C83.2 C84.2 R131.2 | length 2.5
  L4 - Bottom Layer w0.5: R131.2@66.7,14.95 C84.2@68,14.95 C83.2@69.215,14.95
GPIO17: J10.2 U24.29 | length 10
  L1 - Top Layer w0.125: J10.2@126.75,7.5 129.25,10 133.9,10 134.4,10.5 U24.29@134.4,11.63
GPIO18: J10.3 U24.30 | length 8.7
  L1 - Top Layer w0.125: J10.3@129.29,7.5 131.19,9.4 134.5,9.4 135.6,10.5 U24.30@135.6,11.63
GPIO19: J10.4 U24.31 | length 7.5
  L1 - Top Layer w0.125: J10.4@131.83,7.5 133.13,8.8 135.3,8.8 136.8,10.3 U24.31@136.8,11.63
GPIO20: J10.5 U24.32 | length 6.1
  L1 - Top Layer w0.125: J10.5@134.37,7.5 135.1,7.5 138,10.4 U24.32@138,11.63
ISI_D0: J17.18 R220.1 | length 36.4
  L1 - Top Layer w0.125: R220.1@78,101.109 75.691,101.109 75.2,101.6 75.2,102.6 75.7,103.1 76.9,103.1 77.3,103.5 77.3,104.3 76.9,104.7 75.7,104.7 75.2,105.2 75.2,107.3 74.2,108.3 71,108.3 69.4,109.9 69.4,113 71.4,115 75.2,115 v1(78,117.8)
  L4 - Bottom Layer w0.125: v1(78,117.8) 78.138,117.8 J17.18@80.868,120.53
ISI_D1: J17.19 R221.2 | length 35.7
  L1 - Top Layer w0.125: J17.19@78.328,123.07 77.1,121.842 75.042,121.842 74.5,121.3 74.5,119.4 75.1,118.8 77.9,118.8 78.5,118.2 78.5,116.9 75.6,114 72.1,114 71.1,113 71.1,109.6 71.9,108.8 74.6,108.8 78.5,104.9 R221.2@78.5,103.25
ISI_D2: J17.20 R222.1 | length 37.9
  L1 - Top Layer w0.125: J17.20@78.328,120.53 79,119.858 79,115.5 76.5,113 73.2,113 72.9,112.7 72.9,112.3 73.2,112 77.9,112 78.2,111.7 78.2,111.3 77.9,111 73.2,111 72.9,110.7 72.9,110.2 73.2,109.9 75.4,109.9 79,106.3 R222.1@79,101.109
ISI_D3: J17.21 R223.2 | length 34.2
  L1 - Top Layer w0.125: v1(71.3,124.4) 79.2,124.4 79.5,124.1 R223.2@79.5,103.25
  L4 - Bottom Layer w0.125: v1(71.3,124.4) 74.458,124.4 J17.21@75.788,123.07
ISI_D4: J17.22 R224.1 | length 34.2
  L1 - Top Layer w0.125: v1(80,118.6) 80,103.75 R224.1@80.5,103.25
  L4 - Bottom Layer w0.125: J17.22@75.788,120.53 75.788,118.912 77.5,117.2 78.6,117.2 79.4,118 85.1,118 85.5,118.4 85.5,118.8 85.3,119 84.9,119 84.5,118.6 v1(80,118.6)
ISI_D5: J17.23 R225.2 | length 36.3
  L1 - Top Layer w0.125: v1(80.5,117.3) 80.5,104.3 81,103.8 R225.2@81,101.109
  L4 - Bottom Layer w0.125: J17.23@73.248,123.07 74.5,121.818 74.5,119.2 77.1,116.6 84.3,116.6 84.5,116.8 84.5,117.1 84.3,117.3 v1(80.5,117.3)
ISI_D6: J17.24 R226.1 | length 34.2
  L1 - Top Layer w0.125: v1(81,116) 81,118.8 81.4,119.2 83.5,119.2 83.8,118.9 83.8,118.4 83.5,118.1 81.9,118.1 81.5,117.7 81.5,115.6 81,115.1 81,104.5 81.5,104 R226.1@81.5,103.25
  L4 - Bottom Layer w0.125: J17.24@73.248,120.53 73.248,119.3 76.548,116 v1(81,116)
ISI_D7: J17.25 R227.2 | length 36.4
  L1 - Top Layer w0.125: R227.2@82,101.109 v1(82,116)
  L4 - Bottom Layer w0.125: J17.25@70.708,123.07 72,121.778 72,119.3 75.9,115.4 84.4,115.4 84.6,115.6 84.6,115.8 84.4,116 v1(82,116)
ISI_D8: J17.26 R228.1 | length 36.3
  L1 - Top Layer w0.125: v1(82.5,114.8) 82.5,117.3 82.8,117.6 83.8,117.6 84.1,117.3 84.1,115.8 82.5,114.2 82.5,103.2 83,102.7 R228.1@83,101.109
  L4 - Bottom Layer w0.125: J17.26@70.708,120.53 70.708,119.24 75.148,114.8 v1(82.5,114.8)
ISI_D9: J17.27 R229.2 | length 34.2
  L1 - Top Layer w0.125: R229.2@83.5,103.25 83.5,107.1 83.2,107.4 83.2,108.2 83.4,108.4 83.4,109.2 83.1,109.5 83.1,110.1 83.5,110.5 83.5,111.1 83.1,111.5 83.1,112.1 83.5,112.5 83.5,113.1 83.1,113.5 83.1,114 v1(84,114.9)
  L4 - Bottom Layer w0.125: J17.27@68.168,123.07 69.5,121.738 69.5,119.3 74.6,114.2 83.3,114.2 v1(84,114.9)
ISI_D10: J17.28 R230.1 | length 34.3
  L1 - Top Layer w0.125: R230.1@84,101.109 84,113.7 84.5,114.2 v1(84.9,114.2)
  L4 - Bottom Layer w0.125: J17.28@68.168,120.53 68.168,119.3 73.868,113.6 84.3,113.6 v1(84.9,114.2)
ISI_D11: J17.29 R231.2 | length 34.3
  L1 - Top Layer w0.125: R231.2@84.5,103.25 v1(84.5,113)
  L4 - Bottom Layer w0.125: J17.29@65.628,123.07 66.9,121.798 66.9,119.3 73.2,113 v1(84.5,113)
ISI_EN: J17.6 R213.1 | length 35.6
  L1 - Top Layer w0.125: J17.6@96.108,120.53 96.108,118.892 96.5,118.5 97.5,118.5 97.8,118.2 97.8,117.9 97.5,117.6 96.408,117.6 96.108,117.3 96.108,116.8 96.408,116.5 98.3,116.5 98.6,116.2 98.6,115.9 98.3,115.6 96.408,115.6 96.108,115.3 96.108,114.8 96.408,114.5 98.3,114.5 98.6,114.2 98.6,113.9 98.3,113.6 96.408,113.6 96.108,113.3 96.108,112.8 96.408,112.5 98.3,112.5 98.6,112.2 98.6,111.9 98.3,111.6 96.408,111.6 96.108,111.3 96.108,110.8 96.408,110.5 97.5,110.5 97.8,110.2 97.8,109.9 97.5,109.6 96.5,109.6 96.108,109.208 96.108,103.742 R213.1@96.6,103.25
ISI_HSYNC: J17.14 R218.1 | length 35.7
  L1 - Top Layer w0.125: J17.14@85.948,120.53 87.2,121.782 87.2,123.8 87.7,124.3 89.3,124.3 89.8,123.8 89.8,118.5 89.5,118.2 88.5,118.2 88.2,117.9 88.2,117.6 88.5,117.3 89.8,117.3 90.1,117 90.1,116.6 89.8,116.3 88.5,116.3 88.2,116 88.2,115.7 88.5,115.4 89.8,115.4 90.1,115.1 90.1,105.8 89.3,105 87.6,105 86.5,103.9 R218.1@86.5,103.25
ISI_MCK: J17.10 R215.1 | length 37
  L1 - Top Layer w0.125: R215.1@87,101.109 87,103.5 87.9,104.4 89.828,104.4 91.028,105.6 91.028,108.1 91.328,108.4 92.3,108.4 92.6,108.7 92.6,109 92.3,109.3 91.328,109.3 91.028,109.6 91.028,110.1 91.328,110.4 92.628,110.4 92.928,110.7 92.928,111 92.628,111.3 91.328,111.3 91.028,111.6 91.028,112.1 91.328,112.4 92.628,112.4 92.928,112.7 92.928,113 92.628,113.3 91.328,113.3 91.028,113.6 91.028,114.1 91.328,114.4 92.628,114.4 92.928,114.7 92.928,115 92.628,115.3 91.328,115.3 91.028,115.6 91.028,116.1 91.328,116.4 92.628,116.4 92.928,116.7 92.928,117 92.628,117.3 91.328,117.3 91.028,117.6 J17.10@91.028,120.53
ISI_nRST: J17.5 R212.2 | length 28.9
  L1 - Top Layer w0.125: R212.2@88,103.25 89.85,103.25 93.6,107 93.6,117.8 92.4,119 92.4,123.9 92.7,124.2 94.978,124.2 J17.5@96.108,123.07
ISI_PCK: J17.16 R219.1 | length 35.7
  L1 - Top Layer w0.125: J17.16@83.408,120.53 82.1,121.838 82.1,123.8 82.6,124.3 84.2,124.3 84.7,123.8 84.7,119.3 85,119 86.6,119 86.8,118.8 86.8,118 86.6,117.8 84.9,117.8 84.7,117.6 84.7,116.9 84.9,116.7 86.5,116.7 86.7,116.5 86.7,116 86.5,115.8 85.7,115.8 85.5,115.6 85.5,115 85.7,114.8 86.5,114.8 86.7,114.6 86.7,114.1 86.5,113.9 85.7,113.9 85.5,113.7 R219.1@85.5,103.25
ISI_VSYNC: J17.12 R216.1 | length 36.3
  L1 - Top Layer w0.125: R216.1@86,101.109 86,105 86.3,105.3 87,105.3 87.8,106.1 89.1,106.1 89.4,106.4 89.4,106.7 89.1,107 87.8,107 87.5,107.3 87.5,107.7 87.8,108 89.1,108 89.4,108.3 89.4,108.6 89.1,108.9 87.8,108.9 87.5,109.2 87.5,109.6 87.8,109.9 89.1,109.9 89.4,110.2 89.4,110.5 89.1,110.8 87.8,110.8 87.5,111.1 87.5,111.5 87.8,111.8 89.1,111.8 89.4,112.1 89.4,112.4 89.1,112.7 87.8,112.7 87.5,113 87.5,113.5 87.8,113.8 89.1,113.8 89.4,114.1 89.4,114.4 89.1,114.7 87.8,114.7 87.5,115 v1(87.5,118)
  L4 - Bottom Layer w0.125: v1(87.5,118) 88.488,118.988 J17.12@88.488,120.53
JLINK_nRST: R234.2 U32.14 | length 33.2
  L1 - Top Layer w0.125: R234.2@22.925,91.3 v2(23.775,91.3) ; U32.14@37.35,103.323 39.077,103.323 v1(39.1,103.3)
  L4 - Bottom Layer w0.125: v2(23.775,91.3) 23.775,103.325 23.3,103.8 23.3,104.7 24,105.4 37,105.4 v1(39.1,103.3)
JLINK_RTCK_IN: R250.1 U27.F4 U32.6 | length 27.3
  L1 - Top Layer w0.125: U27.F4@22.275,83.2 22.675,82.8 v1(26.9,82.8) 27.425,83.325 R250.1@27.425,83.5 ; v1(30.6,101.4) 30.618,101.418 U32.6@32.05,101.418
  L4 - Bottom Layer w0.125: v1(26.9,82.8) 28.5,84.4 28.5,99.3 v1(30.6,101.4)
JLINK_TCK_IN: R244.2 U27.H4 U31.3 | length 22.8
  L1 - Top Layer w0.125: v1(21.6,103.3) 21.645,103.345 U31.3@22.85,103.345 ; U27.H4@23.875,83.2 v3(24.275,83.6)
  L4 - Bottom Layer w0.125: v1(21.6,103.3) 23.3,101.6 23.3,90.425 23.8,89.925 23.8,86.325 R244.2@24.525,85.6 ; v3@24.248,83.6 v3(24.275,83.6) 24.275,85.454 R244.2@24.422,85.6
JLINK_TDI_IN: R243.2 U27.H5 U31.6 | length 25.4
  L1 - Top Layer w0.125: U31.6@22.85,101.395 23.825,101.395 26.52,98.7 v1(27.8,98.7) ; U27.H5@23.875,84 23.875,84.025 24.25,84.4 27.625,84.4 v1(27.775,84.55) R243.2@28.475,85.25
  L4 - Bottom Layer w0.125: v1@27.775,98.7 v1(27.775,84.55) v1@27.825,84.5
JLINK_TDO_IN: U27.J8 U31.10 | length 16.7
  L1 - Top Layer w0.125: U27.J8@24.675,86.4 25.076,86.801 v3(25.084,86.801) ; v1(27.6,100.7) 27.645,100.745 U31.10@28.75,100.745
  L4 - Bottom Layer w0.125: v3(25.084,86.801) 26.6,88.316 26.6,99.7 v1(27.6,100.7)
JLINK_TMS_IN: R242.2 U27.H6 U31.13 | length 23.7
  L1 - Top Layer w0.125: U27.H6@23.875,84.8 24.275,85.2 25.85,85.2 26.05,85 v1(26.675,85) 27.125,85 R242.2@27.375,85.25 ; v1(27.6,102.7) 27.605,102.695 U31.13@28.75,102.695
  L4 - Bottom Layer w0.125: v1(26.675,85) 27.3,85.625 27.3,99 28.3,100 28.3,102 v1(27.6,102.7)
JLINK_UART_RX: U27.D9 U29.1 | length 18
  L1 - Top Layer w0.125: v1(19.895,90.027) 19.895,89.933 20.36,89.468 20.36,88.435 20.275,88.35 20.275,87.6 U27.D9@20.675,87.2
  L2 - GND w0.125: v1@19.873,90.027 v1(19.895,90.027)
  L4 - Bottom Layer w0.125: U29.1@14.275,101.875 15.225,101.875 15.4,101.7 15.4,98.649 16.249,97.8 18.7,95.349 18.7,91.221 v1(19.895,90.027)
JLINK_UART_TX: U27.D10 U29.8 | length 16.8
  L1 - Top Layer w0.125: U27.D10@20.675,88 v1(20.675,90.025)
  L2 - GND w0.125: v1@20.625,89.839 v1@20.675,89.889
  L4 - Bottom Layer w0.125: U29.8@16.925,101.875 16.075,101.875 15.9,101.7 15.9,98.9 19.3,95.5 19.3,91.4 v1(20.675,90.025)
JLINK_USBHS_N: J22.2 R247.1 U27.D2 | length 29.5
  L1 - Top Layer w0.125: J22.2@5.119,64.65 5.55,64.65 5.712,64.488 10.062,64.488 19.363,73.788 v1@19.363,75.837 ; U27.D2@20.675,81.6 v3(21.075,81.2)
  L4 - Bottom Layer w0.125: v1@19.225,75.85 19.362,75.987 19.362,76.335 20,76.972 20,77.3 19.8,77.5 19.3,77.5 19.1,77.7 19.1,77.9 19.272,78.072 21.1,78.072 21.55,78.522 21.55,79.75 R247.1@21.05,80.25 ; v3(21.075,81.2) 21.075,80.375 R247.1@21.2,80.25
  other v1: 19.175,75.85
JLINK_USBHS_P: J22.3 R248.1 U27.C2 | length 30.4
  L1 - Top Layer w0.125: J22.3@5.119,64 5.6,64 5.763,64.163 10.197,64.163 19.688,73.653 v1@19.688,75.837 ; U27.C2@19.875,81.6 v3(20.275,81.2)
  L4 - Bottom Layer w0.125: v1@19.825,75.85 19.725,75.95 19.687,75.987 19.687,76.2 21.875,78.388 21.875,79.95 21.575,80.25 21.575,80.675 21.475,80.775 21.475,81.35 21.175,81.65 20.725,81.65 v3(20.275,81.2) 20.275,80.325 R248.1@20.2,80.25
  other v1: 19.875,75.85
JTAG_CONN_nRST: R260.1 R265.1 U32.11 | length 11.4
  L1 - Top Layer w0.125: R265.1@33.95,109.6 34.7,109.6 ; R260.1@35.05,109.6 34.7,109.6 ; U32.11@37.35,101.418 35.682,101.418 34.7,102.4 34.7,109.6
JTAG_CONN_RTCK: J23.11 R259.2 U32.3 | length 15.5
  L1 - Top Layer w0.125: J23.11@27.9,111.73 29.17,113 31.4,113 31.7,112.7 31.7,110.9 31.95,110.65 R259.2@31.95,109.6 ; R259.2@31.9,109.6 31.9,107.4 33.3,106 33.3,103.7 32.923,103.323 U32.3@32.05,103.323
JTAG_CONN_TCK: J23.9 R258.2 U31.2 | length 14.5
  L1 - Top Layer w0.125: U31.2@22.85,103.995 21.705,103.995 21.3,104.4 21.3,110.5 21.5,110.7 21.5,112.3 22.2,113 24.09,113 J23.9@25.36,111.73 ; J23.9@25.46,111.83 J23.9@25.56,111.73
JTAG_CONN_TDI: J23.5 R256.1 U31.5 | length 11.3
  L1 - Top Layer w0.125: J23.5@20.48,111.73 20.48,103.32 21.755,102.045 U31.5@22.85,102.045
JTAG_CONN_TDO: J23.13 U31.11 | length 11.8
  L1 - Top Layer w0.125: U31.11@28.725,101.37 U31.11@28.75,101.395 29.795,101.395 30,101.6 30,111.09 J23.13@30.64,111.73
JTAG_CONN_TMS: J23.7 R257.1 U31.14 | length 11.3
  L1 - Top Layer w0.125: J23.7@23.02,111.73 23.45,111.3 R257.1@23.45,109.6 23.45,107.65 27.755,103.345 U31.14@28.75,103.345
JTAG_nRST: R191.1 U32.10 U32.13 | length 90.5
  L1 - Top Layer w0.125: U32.10@37.35,100.783 38.883,100.783 39.4,101.3 39.4,102.4 ; U32.13@37.35,102.688 39.112,102.688 39.4,102.4 ; v1@60.2,108.9 45.9,108.9 39.4,102.4 ; v2(100.5,111.2) 100.5,101.775 102.875,99.4 R191.1@102.875,91.883
  L4 - Bottom Layer w0.125: v1(60.3,108.9) 62.6,111.2 v2(100.5,111.2)
JTAG_RTCK: U5.T2 U32.4 U32.7 | length 129.3
  L1 - Top Layer w0.125: U32.7@32.05,100.783 33.883,100.783 ; U32.4@32.05,102.688 33.412,102.688 33.9,102.2 33.9,100.8 33.883,100.783 ; v1(59.2,108.3) 47.1,108.3 38.4,99.6 35.065,99.6 33.883,100.783 ; U5.T2@76.725,77.875 76.725,78.625 77.4,79.3 85.7,79.3 88.7,82.3 89.3,82.3 90.2,83.2 90.2,86.1 92,87.9 97.7,87.9 101.7,91.9 101.7,92.3 102.4,93 102.4,99.125 99.8,101.725 v2(99.8,110.6)
  L4 - Bottom Layer w0.125: v1(59.2,108.3) 63.7,108.3 66,110.6 v2(99.8,110.6)
JTAG_TCK: U5.R3 U31.4 | length 131.4
  L1 - Top Layer w0.125: U31.4@22.85,102.695 23.605,102.695 27.1,99.2 28.9,99.2 29.7,98.4 40.2,98.4 48.1,106.3 v1(60.3,106.3) ; U5.R3@76.075,77.225 76.4,77.55 76.4,79 77.3,79.9 85.1,79.9 88,82.8 89,82.8 89.7,83.5 89.7,86.4 91.6,88.3 97.5,88.3 99.6,90.4 99.6,98.801 97.6,100.801 97.6,101.8 97.3,102.1 v2(97.3,108.8)
  L4 - Bottom Layer w0.125: v1(60.3,106.3) 64.7,106.3 67.2,108.8 v2(97.3,108.8)
JTAG_TDI: U5.F3 U31.7 | length 155.7
  L1 - Top Layer w0.125: U31.7@22.85,100.745 23.755,100.745 26.568,97.933 40.733,97.933 48.5,105.7 v1(59.2,105.7) ; U5.F3@76.075,71.375 v4(76.4,71.05) ; v3(83,68.3) 83.8,67.5 85.9,67.5 90.4,63 v2(101,63) ; v2(98,108.2) 98,101.201 100.1,99.101 100.1,93.4 v2(101,92.5)
  L4 - Bottom Layer w0.125: v1(59.2,105.7) 64.8,105.7 67.3,108.2 v2(98,108.2) ; v4(76.4,71.05) 80.25,71.05 v3(83,68.3) ; v2(101,63) 101,87 101.3,87.3 101.3,88.4 101,88.7 v2(101,92.5)
JTAG_TDO: U5.H5 U31.9 | length 152.7
  L1 - Top Layer w0.125: U31.9@28.75,100.095 29.305,100.095 30.2,99.2 39,99.2 47.4,107.6 v1(60.3,107.6) ; U5.H5@74.775,72.675 v4(75.1,72.35) ; v3(83,69) 83.8,68.2 85.9,68.2 90.6,63.5 v2(100.1,63.5) ; v2(99.3,110) 99.3,101.501 101.05,99.751 101.05,94.977 v2(101.727,94.3)
  L4 - Bottom Layer w0.1: 75.659,72.025 75.9,72.025 76.011,71.914
  L4 - Bottom Layer w0.125: v1(60.3,107.6) 64.1,107.6 66.5,110 v2(99.3,110) ; v4(75.1,72.35) 75.425,72.025 75.659,72.025 ; 76.011,71.914 76.3,71.625 80.375,71.625 v3(83,69) ; v2(100.1,63.5) 100.1,85.2 100.2,85.3 100.2,92.773 v2(101.727,94.3)
JTAG_TMS: U5.F5 U31.12 | length 161.3
  L1 - Top Layer w0.125: U31.12@28.75,102.045 27.745,102.045 27.1,101.4 27.1,99.9 27.48,99.52 29.18,99.52 29.9,98.8 39.5,98.8 47.7,107 v1(59.2,107) ; U5.F5@74.775,71.375 74.775,70.9 77.225,68.45 77.95,68.45 81.036,65.364 85.336,65.364 89.7,61 v2(101.9,61) ; v2(98.6,109.4) 98.6,101.401 100.6,99.401 100.6,94.6 v2(101.8,93.4)
  L4 - Bottom Layer w0.125: v1(59.2,107) 64.7,107 67.1,109.4 v2(98.6,109.4) ; v2(101.8,93.4) 101.8,92.227 102,92.027 102,61.1 v2(101.9,61)
LCD_D0_ISI_D0_PC00: J15.3 R220.2 U5.M4 | length 45.1
  L1 - Top Layer w0.125: U5.M4@75.425,75.275 v4@75.758,75.608 ; v1(78,97.2) 79.088,96.112 79.088,89.312 v1(79.9,88.5) ; v1(78,99.618) R220.2@78,100.209
  L4 - Bottom Layer w0.1: 76.309,75.925 77.141,75.925
  L4 - Bottom Layer w0.125: v4(75.75,75.608) 76.067,75.925 76.309,75.925 ; 77.141,75.925 77.625,75.925 78.7,77 87.3,77 87.475,77.175 87.475,77.425 87.3,77.6 80.1,77.6 79.9,77.8 v1(79.9,88.5) ; v1(78,97.2) v1(78,99.618) J15.3@78,100.659
LCD_D1_ISI_D1_PC01: J15.4 R221.1 U5.P4 | length 45.7
  L1 - Top Layer w0.125: U5.P4@75.431,76.575 U5.P4@75.425,76.575 v4(75.75,76.9) ; v1(78.4,88.1) 77.1,88.1 76.925,88.275 76.925,88.525 77.1,88.7 78.225,88.7 78.4,88.875 78.4,89.125 78.225,89.3 77.1,89.3 76.925,89.475 76.925,89.725 77.1,89.9 77.275,89.9 78.225,89.9 78.4,90.075 78.4,90.325 78.225,90.5 77.1,90.5 76.925,90.675 76.925,90.925 77.1,91.1 77.275,91.1 78.225,91.1 78.4,91.275 78.4,91.525 78.225,91.7 77.1,91.7 76.925,91.875 76.925,92.125 77.1,92.3 78.225,92.3 78.4,92.475 78.4,92.725 78.225,92.9 77.1,92.9 76.925,93.075 76.925,93.325 77.1,93.5 78.225,93.5 78.4,93.675 78.4,93.925 78.225,94.1 77.1,94.1 76.925,94.275 76.925,94.525 77.1,94.7 78.225,94.7 78.4,94.875 78.4,95.125 78.225,95.3 77.1,95.3 76.925,95.475 76.925,95.725 77.1,95.9 77.7,95.9 77.875,96.075 77.875,96.325 77.7,96.5 77.2,96.5 77,96.7 77,97.375 77.525,97.9 v1(78.5,97.9) ; v1(78.5,101.7) R221.1@78.5,102.35
  L4 - Bottom Layer w0.125: v4(75.75,76.9) 75.75,77.95 78.4,80.6 v1(78.4,88.1) ; v1(78.5,97.9) J15.4@78.5,100.159 ; J15.4@78.5,100.659 v1(78.5,101.7)
LCD_D2_ISI_D2_PC02: J15.5 R222.2 U5.N5 | length 45.1
  L1 - Top Layer w0.125: U5.N5@74.781,75.925 U5.N5@74.775,75.925 v4(75.1,76.25) ; v1(77.9,87.6) 75.5,87.6 75.125,87.975 75.125,88.525 75.3,88.7 76.225,88.7 76.4,88.875 76.4,89.125 76.225,89.3 75.1,89.3 74.925,89.475 74.925,89.725 75.1,89.9 75.275,89.9 76.225,89.9 76.4,90.075 76.4,90.325 76.225,90.5 75.1,90.5 74.925,90.675 74.925,90.925 75.1,91.1 75.275,91.1 76.225,91.1 76.4,91.275 76.4,91.525 76.225,91.7 75.1,91.7 74.925,91.875 74.925,92.125 75.1,92.3 76.225,92.3 76.4,92.475 76.4,92.725 76.225,92.9 75.1,92.9 74.925,93.075 74.925,93.325 75.1,93.5 76.225,93.5 76.4,93.675 76.4,93.925 76.225,94.1 75.1,94.1 74.925,94.275 74.925,94.525 75.1,94.7 76.225,94.7 76.4,94.875 76.4,97.7 77.2,98.5 v1(79,98.5) ; v1(79,99.618) R222.2@79,100.209
  L4 - Bottom Layer w0.1: 75.425,76.809 75.425,77
  L4 - Bottom Layer w0.125: v4(75.1,76.25) 75.425,76.575 75.425,76.809 ; 75.425,77 75.425,78.125 77.9,80.6 v1(77.9,87.6) ; v1(79,98.5) v1(79,99.618) J15.5@79,100.659
LCD_D3_ISI_D3_PC03: J15.6 R223.1 U5.P5 | length 45.7
  L1 - Top Layer w0.125: U5.P5@74.775,76.575 v4(75.1,76.9) ; v1(77.4,87.1) 75.175,87.1 74.3,87.975 74.3,95.325 74.475,95.5 74.65,95.5 75.6,95.5 75.775,95.675 75.775,95.925 75.6,96.1 73.8,96.1 73.625,96.275 73.625,96.525 73.8,96.7 75.6,96.7 75.775,96.875 75.775,97.125 75.6,97.3 73.8,97.3 73.625,97.475 73.625,97.725 73.8,97.9 75.6,97.9 75.775,98.075 75.775,98.325 75.6,98.5 73.8,98.5 73.625,98.675 73.625,98.925 73.8,99.1 v1(79.5,99.1) ; v1(79.5,101.7) R223.1@79.5,102.35
  L4 - Bottom Layer w0.125: v4(75.1,76.9) 75.1,78.3 77.4,80.6 v1(77.4,87.1) ; v1(79.5,99.1) J15.6@79.5,100.159 ; J15.6@79.5,100.659 v1(79.5,101.7)
LCD_D4_ISI_D4_PC04: J15.8 R224.2 U5.L5 | length 48.7
  L1 - Top Layer w0.1: 75.3,75.629 76.421,76.75
  L1 - Top Layer w0.125: U5.L5@74.775,74.625 74.775,75.104 75.3,75.629 ; 76.421,76.75 76.425,76.75 77.225,77.55 77.6,77.55 77.65,77.6 85.9,77.6 88.275,79.975 88.275,80.225 88.1,80.4 87.8,80.4 85.6,78.2 v3(80.5,78.2) ; v1(80.5,101.7) R224.2@80.5,102.35
  L4 - Bottom Layer w0.125: v3(80.5,78.2) J15.8@80.5,100.159 ; J15.8@80.5,100.659 v1(80.5,101.7)
LCD_D5_ISI_D5_PC05: J15.9 R225.1 U5.R4 | length 48.6
  L1 - Top Layer w0.125: U5.R4@75.425,77.225 75.75,77.55 75.75,79.75 77.1,81.1 v1(81.5,81.1) ; v1(81,99.618) R225.1@81,100.209
  L4 - Bottom Layer w0.125: v1(81,99.618) J15.9@81,100.659 ; J15.9@81,100.159 81,89.3 81.275,89.025 81.825,89.025 82,88.85 82,88.6 81.825,88.425 81.175,88.425 81,88.25 81,88 81.175,87.825 81.825,87.825 82,87.65 82,87.4 81.825,87.225 81.675,87.225 81.175,87.225 81,87.05 81,86.8 81.175,86.625 81.825,86.625 82,86.45 82,86.2 81.825,86.025 81.175,86.025 81,85.85 81,85.6 81.175,85.425 81.825,85.425 82,85.25 82,85 81.825,84.825 81.675,84.825 81.175,84.825 81,84.65 81,84.4 81.175,84.225 81.825,84.225 82,84.05 82,83.8 81.825,83.625 81.175,83.625 81,83.45 81,83.2 81.175,83.025 81.825,83.025 82,82.85 82,82.6 81.825,82.425 81.175,82.425 81,82.25 81,82 81.175,81.825 81.825,81.825 82,81.65 82,78.6 81.5,78.1 81.125,78.1 80.95,78.275 80.95,78.525 81.125,78.7 81.375,78.7 81.55,78.875 81.55,79.125 81.375,79.3 81.125,79.3 80.95,79.475 80.95,79.725 81.125,79.9 81.375,79.9 81.55,80.075 81.55,80.325 81.375,80.5 81.125,80.5 80.95,80.675 80.95,80.925 81.125,81.1 v1@81.45,81.1
LCD_D6_ISI_D6_PC06: J15.10 R226.2 U5.M6 | length 48.7
  L1 - Top Layer w0.1: 75.1,75.8 75.11,75.8 76.2,76.89
  L1 - Top Layer w0.125: U5.M6@74.125,75.275 74.575,75.275 75.1,75.8 ; 76.2,76.89 77.054,77.745 77.054,78.254 77.5,78.7 v3(82.5,78.7) ; v1(81.5,101.7) R226.2@81.5,102.35
  L4 - Bottom Layer w0.125: J15.10@81.5,100.159 81.5,90 82.5,89 82.5,80.175 82.775,79.9 86.375,79.9 86.7,79.575 86.7,78.275 86.525,78.1 86.275,78.1 86.1,78.275 86.1,79.125 85.925,79.3 85.675,79.3 85.5,79.125 85.5,78.275 85.325,78.1 85.075,78.1 84.9,78.275 84.9,79.125 84.725,79.3 84.475,79.3 84.3,79.125 84.3,78.275 84.125,78.1 83.875,78.1 83.7,78.275 83.7,79.125 83.525,79.3 83.275,79.3 83.1,79.125 83.1,78.275 82.925,78.1 82.675,78.1 82.5,78.275 v3(82.5,78.7) ; J15.10@81.5,100.659 v1(81.5,101.7)
LCD_D7_ISI_D7_PC07: J15.11 R227.1 U5.T3 | length 48.1
  L1 - Top Layer w0.125: U5.T3@76.075,77.875 76.075,79.375 77.2,80.5 81.95,80.5 82.55,81.1 84.875,81.1 85.05,80.925 85.05,80.675 84.875,80.5 v1(83,80.5) ; v1(82,99.618) R227.1@82,100.209
  L4 - Bottom Layer w0.125: J15.11@82,100.659 v1(82,99.618) 82,90.175 83,89.175 83,81.45 83.35,81.1 87.325,81.1 87.9,80.525 87.9,78.375 87.725,78.2 87.475,78.2 87.3,78.375 87.3,79.85 86.65,80.5 v1(83,80.5)
LCD_D8_ISI_D8_PC08: J15.13 R228.2 U5.N8 | length 45.6
  L1 - Top Layer w0.125: v4(72.5,75.6) U5.N8@72.825,75.925 ; v1(79.9,94.8) 80.8,95.7 v1(82.5,95.7) ; v1(83,99.618) R228.2@83,100.209
  L4 - Bottom Layer w0.125: v4(72.5,75.6) 72.6,75.7 72.6,77.225 72.7,77.325 72.7,80.6 73.45,81.35 73.45,88.35 v1(79.9,94.8) ; v1(82.5,95.7) 82.45,95.65 82.45,90.35 82.625,90.175 82.875,90.175 83.05,90.35 83.05,96.125 82.875,96.3 82.625,96.3 82.45,96.475 82.45,96.725 82.625,96.9 82.875,96.9 83.05,97.075 83.05,97.325 82.875,97.5 82.625,97.5 82.45,97.675 82.45,97.925 82.625,98.1 82.875,98.1 83.05,98.275 83.05,98.525 82.875,98.7 82.625,98.7 82.45,98.875 82.45,99.125 82.625,99.3 82.875,99.3 83.05,99.475 83.05,100.109 ; v1(83,99.618) J15.13@83,100.659 J15.13@83.05,100.609
LCD_D9_ISI_D9_PC09: J15.14 R229.1 U5.T4 | length 48.6
  L1 - Top Layer w0.125: U5.T4@75.425,77.875 75.425,80.125 77,81.7 v1(83.5,81.7) ; v1(83.5,101.7) R229.1@83.5,102.35
  L4 - Bottom Layer w0.125: v1(83.5,81.7) 83.5,82.125 83.675,82.3 84.6,82.3 84.625,82.3 84.8,82.475 84.8,82.725 84.625,82.9 83.675,82.9 83.5,83.075 83.5,83.325 83.675,83.5 84.6,83.5 84.625,83.5 84.8,83.675 84.8,83.925 84.625,84.1 83.675,84.1 83.5,84.275 83.5,84.525 83.675,84.7 84.625,84.7 84.8,84.875 84.8,85.125 84.625,85.3 83.675,85.3 83.5,85.475 83.5,85.725 83.675,85.9 84.6,85.9 84.625,85.9 84.8,86.075 84.8,86.325 84.625,86.5 83.675,86.5 83.5,86.675 83.5,86.925 83.675,87.1 84.6,87.1 84.625,87.1 84.8,87.275 84.8,87.525 84.625,87.7 83.675,87.7 83.5,87.875 83.5,88.125 83.675,88.3 84.6,88.3 84.625,88.3 84.8,88.475 84.8,88.725 84.625,88.9 83.675,88.9 83.5,89.075 83.5,89.325 83.675,89.5 84.6,89.5 84.625,89.5 84.8,89.675 84.8,89.925 84.625,90.1 83.675,90.1 83.5,90.275 83.5,90.525 83.675,90.7 84.625,90.7 84.8,90.875 84.8,91.125 84.625,91.3 83.675,91.3 83.5,91.475 J15.14@83.5,100.159 ; J15.14@83.5,100.659 v1(83.5,101.7)
LCD_D10_ISI_D10_PC10: J15.15 R230.2 U5.P6 | length 45.1
  L1 - Top Layer w0.125: U5.P6@74.125,76.575 74.125,76.59 74.435,76.9 v4(74.45,76.9) ; v1(79.9,91.3) 80.3,91.3 80.5,91.1 87.975,91.1 88.15,91.275 88.15,91.525 87.975,91.7 81.175,91.7 81,91.875 81,92.125 81.175,92.3 83.6,92.3 v1(84,92.7) ; v1(84,99.618) R230.2@84,100.209
  L4 - Bottom Layer w0.125: v4(74.45,76.9) 74.45,78.65 76.45,80.65 76.45,87.85 v1(79.9,91.3) ; v1(84,92.7) v1(84,99.618) J15.15@84,100.659
LCD_D11_ISI_D11_PC11: J15.16 R231.1 U5.N6 | length 45.7
  L1 - Top Layer w0.125: U5.N6@74.125,75.925 v4(74.45,76.25) ; v1(79.9,90.6) 88.6,90.6 88.775,90.775 88.775,91.275 89.1,91.6 90.4,91.6 90.975,92.175 90.975,92.425 90.8,92.6 90.5,92.6 90.1,92.2 v1(84.5,92.2) ; v1(84.5,101.7) R231.1@84.5,102.35
  L4 - Bottom Layer w0.1: 74.775,76.809 74.775,76.991
  L4 - Bottom Layer w0.125: v4(74.45,76.25) 74.775,76.575 74.775,76.809 ; 74.775,76.991 74.775,78.475 76.925,80.625 76.925,87.625 v1(79.9,90.6) ; v1(84.5,92.2) J15.16@84.5,100.159 ; J15.16@84.5,100.659 v1(84.5,101.7)
LCD_D12_ISI_PCK_PC12: J15.18 R219.2 U5.R5 | length 48.7
  L1 - Top Layer w0.125: U5.R5@74.775,77.225 75.1,77.55 75.1,80.5 76.9,82.3 v1(85.5,82.3) ; v1(85.5,101.7) R219.2@85.5,102.35
  L4 - Bottom Layer w0.125: v1(85.5,82.3) 85.875,82.3 86.05,82.475 86.05,82.725 85.875,82.9 85.5,82.9 85.325,83.075 85.325,83.325 85.5,83.5 85.875,83.5 86.05,83.675 86.05,83.925 85.875,84.1 85.5,84.1 85.325,84.275 85.325,84.525 85.5,84.7 85.875,84.7 86.05,84.875 86.05,85.125 85.875,85.3 85.5,85.3 85.325,85.475 85.325,85.725 85.5,85.9 85.875,85.9 86.05,86.075 86.05,86.325 85.875,86.5 85.5,86.5 85.325,86.675 85.325,86.925 85.5,87.1 85.875,87.1 86.05,87.275 86.05,87.525 85.875,87.7 85.5,87.7 85.325,87.875 85.325,88.125 85.5,88.3 85.875,88.3 86.05,88.475 86.05,88.725 85.875,88.9 85.4,88.9 85.225,89.075 85.225,89.325 85.4,89.5 85.875,89.5 86.05,89.675 86.05,89.925 85.875,90.1 85.4,90.1 85.225,90.275 85.225,90.525 85.4,90.7 85.875,90.7 86.05,90.875 86.05,91.125 85.875,91.3 85.4,91.3 85.225,91.475 85.225,91.725 85.4,91.9 85.875,91.9 86.05,92.075 86.05,92.325 85.875,92.5 85.2,92.5 84.95,92.75 84.95,93 85.125,93.175 85.375,93.175 85.55,93.35 85.55,93.6 85.375,93.775 85.125,93.775 84.95,93.95 84.95,94.2 85.125,94.375 85.375,94.375 85.55,94.55 85.55,94.8 85.375,94.975 85.125,94.975 84.95,95.15 84.95,95.4 85.125,95.575 85.375,95.575 85.55,95.75 85.55,96 85.375,96.175 85.125,96.175 84.95,96.35 84.95,96.6 85.125,96.775 85.375,96.775 85.55,96.95 85.55,97.2 85.375,97.375 85.125,97.375 84.95,97.55 84.95,97.8 85.125,97.975 85.375,97.975 85.55,98.15 85.55,98.4 85.375,98.575 85.125,98.575 84.95,98.75 84.95,99 85.125,99.175 85.375,99.175 85.55,99.35 85.55,100.109 ; v1(85.5,101.7) J15.18@85.5,100.659 J15.18@85.55,100.609
LCD_D13_ISI_VSYNC_PC13: J15.19 R216.2 U5.L7 | length 45.1
  L1 - Top Layer w0.125: U5.L7@73.475,74.625 v4(73.8,74.95) ; v1(79.9,92) 81.1,93.2 84.6,93.2 85.1,92.7 89.7,92.7 90.575,93.575 90.575,93.825 90.4,94 90.1,94 89.3,93.2 v1(86,93.2) ; v1(86,99.618) R216.2@86,100.209
  L4 - Bottom Layer w0.1: 74.125,76.075 74.125,77.075 74.175,77.125
  L4 - Bottom Layer w0.125: v4(73.8,74.95) 74.2,75.35 74.2,76 74.125,76.075 ; 74.175,77.125 74.175,78.975 75.975,80.775 75.975,88.075 v1(79.9,92) ; v1(86,93.2) v1(86,99.618) J15.19@86,100.659
LCD_D14_ISI_HSYNC_PC14: J15.20 R218.2 U5.T5 | length 48.6
  L1 - Top Layer w0.125: U5.T5@74.775,77.875 74.775,80.875 76.8,82.9 v1(86.5,82.9) ; v1(86.5,101.7) R218.2@86.5,102.35
  L4 - Bottom Layer w0.125: v1(86.5,82.9) 88.6,80.8 88.6,80.5 88.775,80.325 89.025,80.325 89.2,80.5 89.2,81.2 87.3,83.1 87.3,83.6 87.075,83.825 86.675,83.825 86.5,84 86.5,84.25 86.675,84.425 87.325,84.425 87.5,84.6 87.5,84.85 87.325,85.025 86.675,85.025 86.5,85.2 86.5,85.45 86.675,85.625 87.325,85.625 87.5,85.8 87.5,86.05 87.325,86.225 86.675,86.225 86.5,86.4 86.5,86.65 86.675,86.825 87.325,86.825 87.5,87 87.5,87.25 87.325,87.425 86.675,87.425 86.5,87.6 86.5,87.85 86.675,88.025 87.325,88.025 87.5,88.2 87.5,88.45 87.325,88.625 86.675,88.625 86.5,88.8 J15.20@86.5,100.159 ; J15.20@86.5,100.659 v1(86.5,101.7)
LCD_D15_ISI_MCK_PC15: J15.21 R215.2 U5.J7 | length 45.6
  L1 - Top Layer w0.125: U5.J7@73.475,73.325 v4(73.8,73.65) ; v1(79.9,89.2) v1(87,89.2) ; v1(87,99.618) R215.2@87,100.209
  L4 - Bottom Layer w0.1: 74.125,73.975 74.125,74.475 76.5,76.85
  L4 - Bottom Layer w0.125: v4(73.8,73.65) 74.125,73.975 ; 76.5,76.85 76.5,77.646 77.554,78.7 78.4,78.7 78.8,78.3 78.8,77.9 78.975,77.725 79.225,77.725 79.4,77.9 79.4,88.7 v1(79.9,89.2) ; 86.95,100.109 86.95,99.475 87.125,99.3 87.375,99.3 87.55,99.125 87.55,98.875 87.375,98.7 87.125,98.7 86.95,98.525 86.95,98.275 87.125,98.1 87.375,98.1 87.55,97.925 87.55,97.675 87.375,97.5 87.125,97.5 86.95,97.325 86.95,97.075 87.125,96.9 87.375,96.9 87.55,96.725 87.55,96.475 87.375,96.3 87.125,96.3 86.95,96.125 86.95,95.875 87.125,95.7 87.375,95.7 87.55,95.525 87.55,95.275 87.375,95.1 87.125,95.1 86.95,94.925 86.95,94.675 87.125,94.5 87.375,94.5 87.55,94.325 87.55,94.075 87.375,93.9 87.125,93.9 86.95,93.725 86.95,93.475 87.125,93.3 87.375,93.3 87.55,93.125 87.55,92.875 87.375,92.7 87.125,92.7 86.95,92.525 86.95,89.25 v1(87,89.2) ; J15.21@86.95,100.609 J15.21@87,100.659 v1(87,99.618)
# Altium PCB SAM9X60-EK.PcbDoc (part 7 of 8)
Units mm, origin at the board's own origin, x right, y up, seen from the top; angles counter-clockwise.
Board outline 150 x 125 mm, 4 copper layers (L1 - Top Layer, L2 - GND, L3 - PWR, L4 - Bottom Layer), stack 1.52 mm thick; 566 components, 500 nets, 2132 pads, 1038 vias.

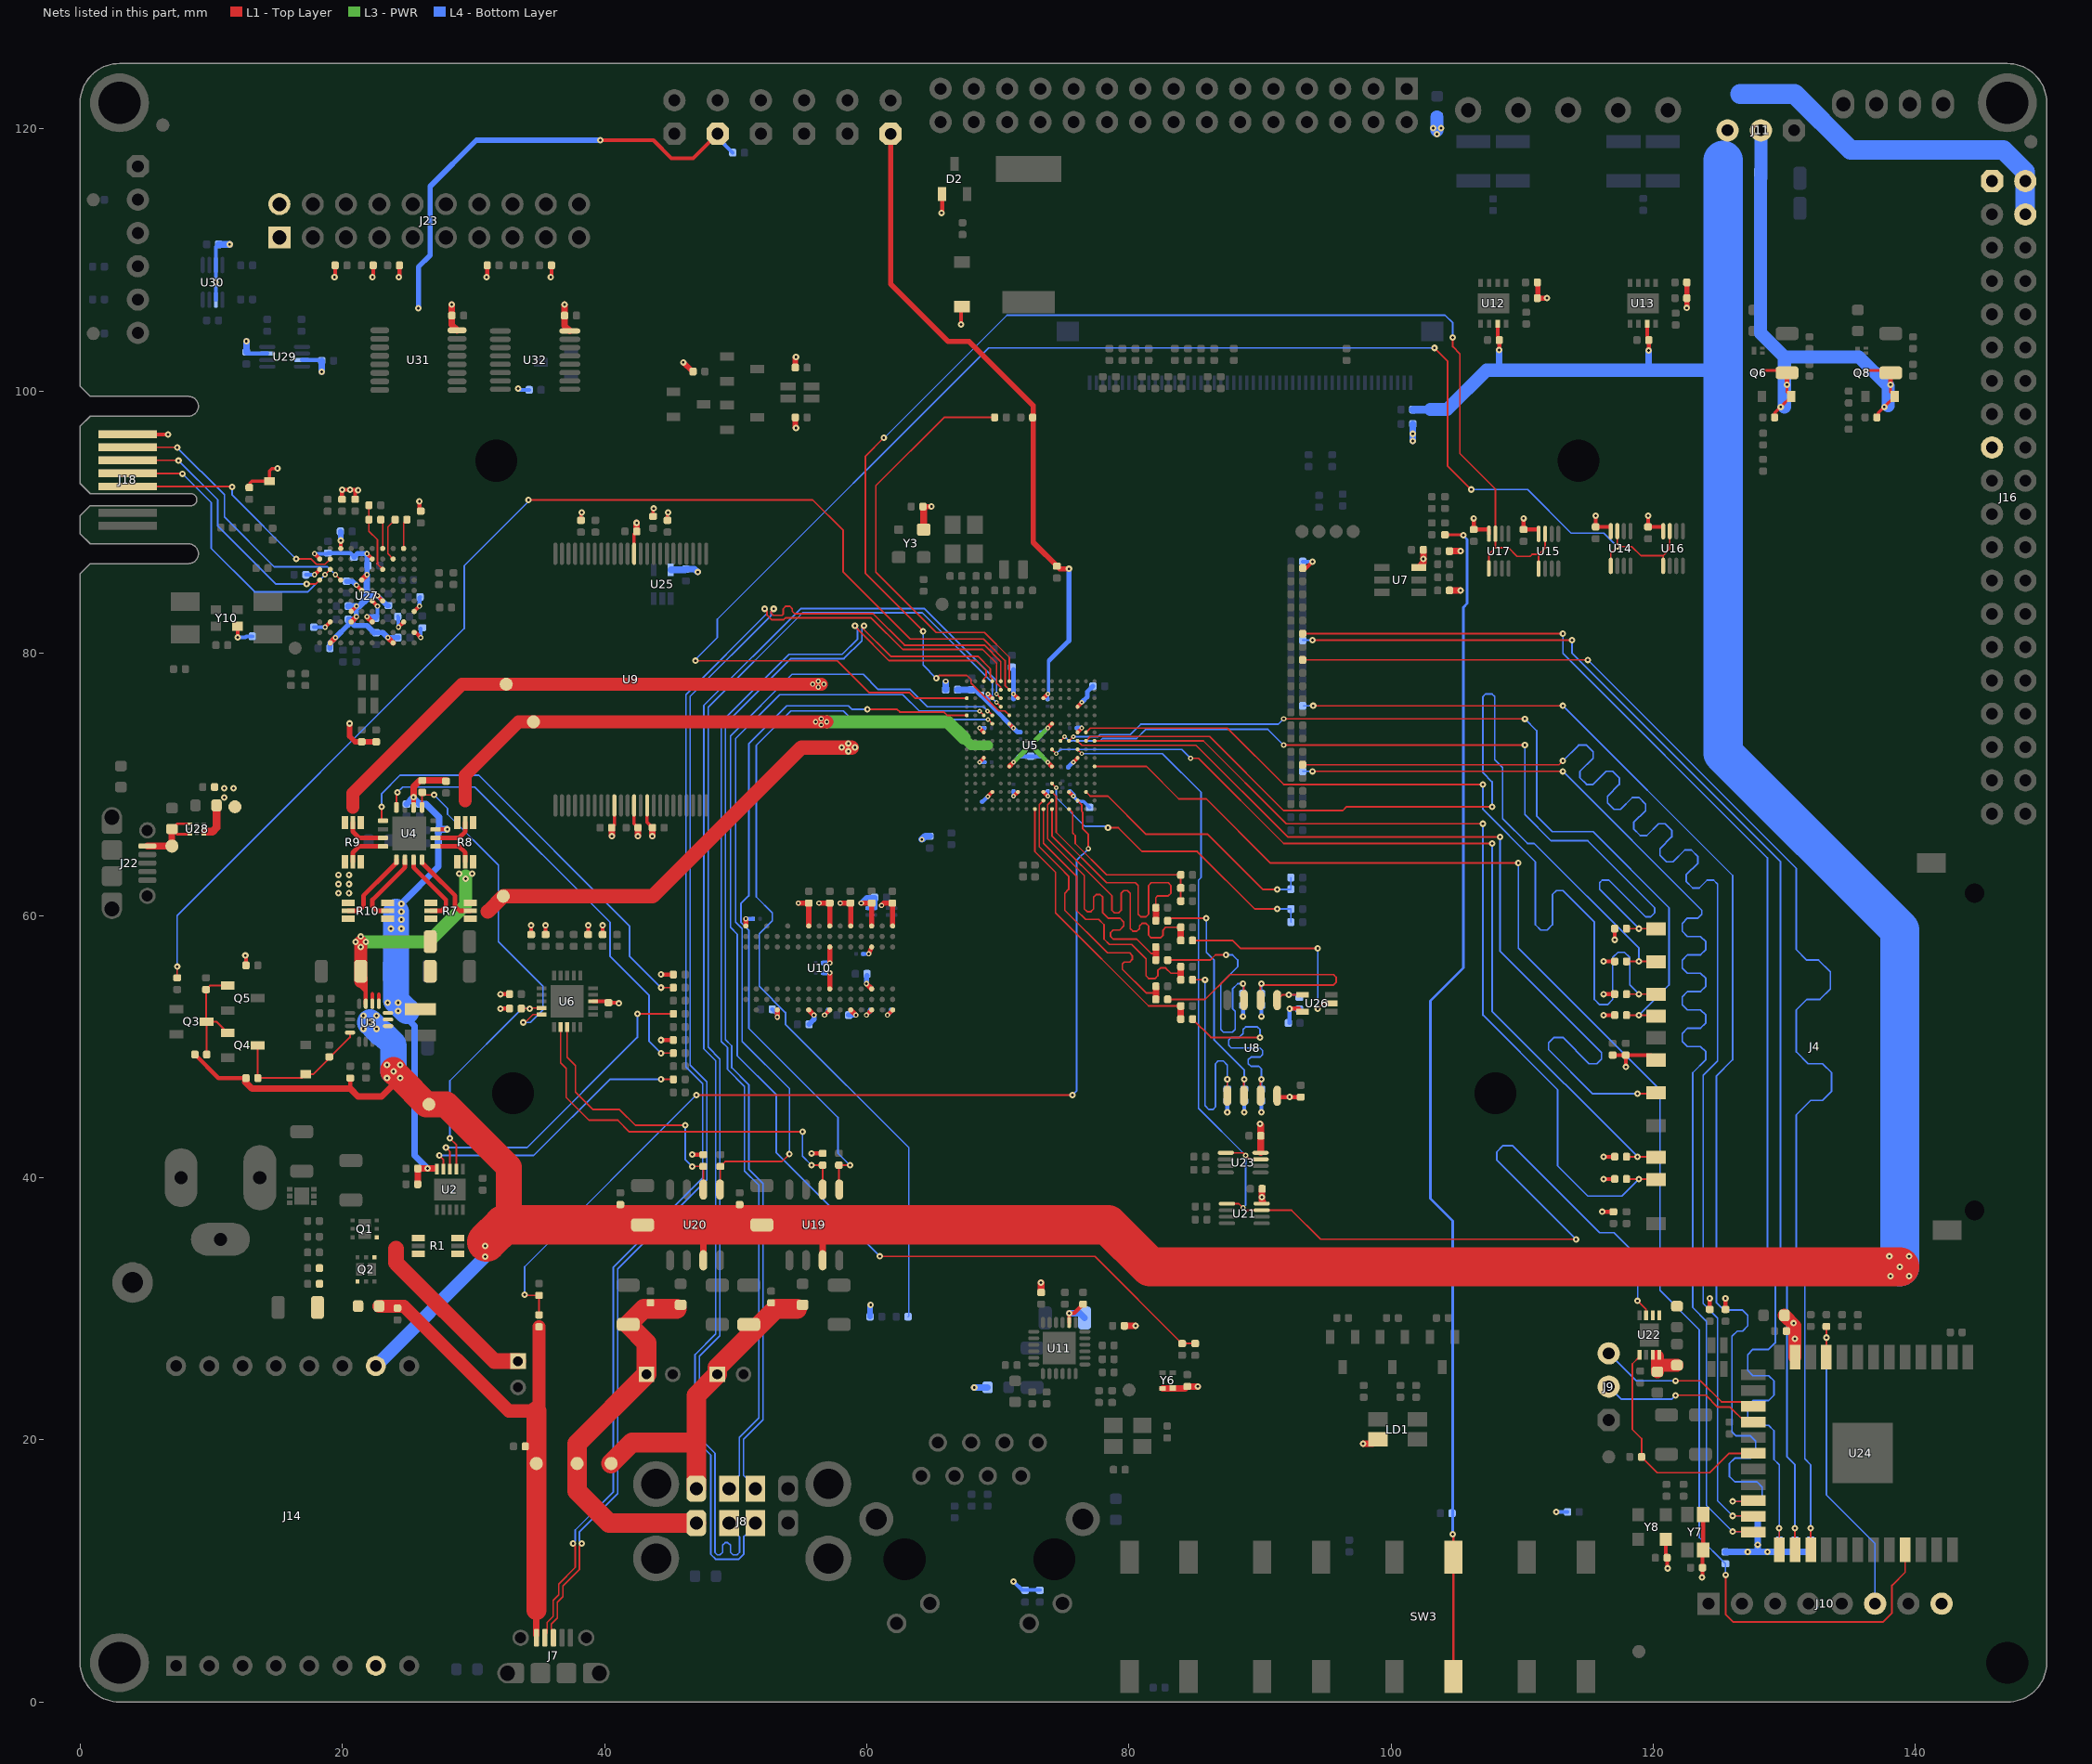
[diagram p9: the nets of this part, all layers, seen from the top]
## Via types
v1: diameter 0.5, hole 0.2, L1 - Top Layer to L4 - Bottom Layer, tented both sides, 483 vias
v2: diameter 0.5, hole 0.2, L1 - Top Layer to L4 - Bottom Layer, 268 vias
v3: diameter 0.4, hole 0.2, L1 - Top Layer to L4 - Bottom Layer, tented both sides, 145 vias
v4: diameter 0.35, hole 0.15, L1 - Top Layer to L4 - Bottom Layer, tented both sides, 121 vias
v5: diameter 0.55, hole 0.3, L1 - Top Layer to L4 - Bottom Layer, tented bottom, 16 vias
v6: diameter 0.559, hole 0.305, L1 - Top Layer to L4 - Bottom Layer, 5 vias

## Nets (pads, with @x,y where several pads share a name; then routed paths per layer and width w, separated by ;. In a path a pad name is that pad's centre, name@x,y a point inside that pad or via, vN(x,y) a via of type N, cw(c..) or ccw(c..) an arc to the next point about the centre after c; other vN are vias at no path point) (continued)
PAC1710_INT: R4.1 U2.7 U6.9 | length 16.9
  L1 - Top Layer w0.125: v1(28.2,43) 28.7,42.5 U2.7@28.7,40.65 ; R4.1@33.65,52.9 v1(34.3,52.9) 34.35,52.95 U6.9@35.185,52.95
  L4 - Bottom Layer w0.125: v1(28.2,43) 28.2,47.4 33.7,52.9 v1(34.3,52.9)
PAC1710_TWCK: R94.2 U2.9 | length 21.4
  L1 - Top Layer w0.125: v1(27.4,41.7) 27.7,41.4 U2.9@27.7,40.65 ; v2(44.3,47.5) R94.2@45.25,47.5
  L4 - Bottom Layer w0.125: v1(27.4,41.7) 34.6,41.7 40.4,47.5 v2(44.3,47.5)
PAC1710_TWD: R89.2 U2.8 | length 24.4
  L1 - Top Layer w0.125: v1(27.9,42.3) 28.2,42 U2.8@28.2,40.65 ; v2(42.5,52.5) R89.2@45.25,52.5
  L4 - Bottom Layer w0.125: v1(27.9,42.3) 34.1,42.3 42.5,50.7 v2(42.5,52.5)
PAC1934_INT: R12.1 U4.1 U6.10 | length 25.5
  L1 - Top Layer w0.125: U4.1@26.075,68.25 26.075,69.375 26.25,69.2 v1(27,69.2) v1@27,69.175 ; v1(33.803,51.847) 33.936,51.847 34.539,52.45 U6.10@35.185,52.45
  L4 - Bottom Layer w0.125: v1(27,69.2) 28.025,68.175 28.025,67.725 31.9,63.85 31.9,58 35.3,54.6 35.3,52.8 34.347,51.847 v1(33.803,51.847)
PAC1934_TWCK: R93.2 U4.4 | length 34.4
  L1 - Top Layer w0.125: U4.4@24.125,68.25 24.125,69.325 v2(24.2,69.4) ; v2(44.3,49.5) R93.2@45.25,49.5
  L4 - Bottom Layer w0.125: v2(24.2,69.4) 24.6,69.8 30.1,69.8 40.425,59.475 40.425,56.875 43.4,53.9 43.4,50.4 v2(44.3,49.5)
PAC1934_TWD: R87.2 U4.5 | length 33
  L1 - Top Layer w0.125: v2@23,68.3 23,67.325 U4.5@23.1,67.225 ; v2(44.3,54.5) R87.2@45.25,54.5
  L4 - Bottom Layer w0.125: v2(23,68.3) 23,69.3 24.4,70.7 30.4,70.7 41.9,59.2 41.9,56.9 v2(44.3,54.5)
PB11: R60.1 R206.1 U5.D6 | length 23.6
  L1 - Top Layer w0.125: U5.D6@74.125,70.075 v4(74.45,69.75) ; v1(78.4,66.7) 79.189,66.7 81,64.889 85.211,64.889 89.6,60.5 v2(91.3,60.5)
  L4 - Bottom Layer w0.125: v4(74.45,69.75) 74.45,69 76.65,66.8 78.3,66.8 v1(78.4,66.7) ; v2(91.3,60.5) R60.1@92.35,60.5 R206.1@92.35,59.5
PB12: R63.1 R200.1 U5.C2 | length 19.6
  L1 - Top Layer w0.125: U5.C2@76.725,69.425 77.045,69.105 78.395,69.105 81.3,66.2 86,66.2 90.2,62 v2(91.3,62)
  L4 - Bottom Layer w0.125: v2(91.3,62) R63.1@92.35,62 R200.1@92.35,62.9
PB13: R65.1 R66.1 R195.1 U5.A4 | length 13.9
  L1 - Top Layer w0.125: U5.A4@75.425,68.125 75.7,67.85 75.7,66.3 75.9,66.1 75.9,65.5 78.3,63.1 R66.1@83.95,63.1 R65.1@83.95,61.1
PB19: R69.2 R70.2 U5.C6 | length 22
  L1 - Top Layer w0.125: U5.C6@74.125,69.425 74.45,69.1 74.45,66.35 78.3,62.5 80.5,62.5 80.7,62.3 80.7,60.1 80.9,59.9 81.3,59.9 81.5,60.1 81.5,62.3 81.7,62.5 83,62.5 83.2,62.3 83.2,61.7 83,61.5 82.2,61.5 82.05,61.35 R69.2@82.05,60.6
  L1 - Top Layer w0.5: R70.2@82.05,59.6 R69.2@82.05,60.6
PB20: R71.2 R72.2 U5.A6 | length 22.1
  L1 - Top Layer w0.125: U5.A6@74.125,68.125 74.125,66.075 78.7,61.5 78.7,60.4 78.9,60.2 79.2,60.2 79.4,60.4 79.4,61.7 79.6,61.9 79.9,61.9 80.1,61.7 80.1,59 80.3,58.8 80.6,58.8 80.8,59 80.8,59.2 81,59.4 81.3,59.4 81.5,59.2 81.5,58.5 81.7,58.3 82.4,58.3 82.6,58.5 82.6,58.9 82.8,59.1 R71.2@83.95,59.1
  L1 - Top Layer w0.5: R72.2@83.95,58.1 R71.2@83.95,59.1
PB21: R74.2 R75.2 U5.A7 | length 22
  L1 - Top Layer w0.125: U5.A7@73.475,68.125 73.475,65.525 76,63 76,60.4 76.7,59.7 77.7,59.7 78.1,59.3 78.1,58.2 78.5,57.8 80.2,57.8 81.3,56.7 81.3,55.4 81.5,55.2 82,55.2 82.2,55.4 82.2,55.8 82.4,56 82.8,56 83.2,55.6 83.95,55.6
  L1 - Top Layer w0.5: R75.2@83.95,55.1 83.95,55.6 R74.2@83.95,56.1
PB22: R77.2 R79.2 U5.B7 | length 22
  L1 - Top Layer w0.125: U5.B7@73.475,68.775 73.15,68.45 73.15,65.25 74.7,63.7 75.4,63 75.4,62 75.1,61.7 75.1,60.4 78.35,57.15 80.05,57.15 80.25,56.95 80.25,56.65 80.05,56.45 79.65,56.45 79.5,56.3 79.5,55.9 81.3,54.1 82.05,54.1
  L1 - Top Layer w0.5: R79.2@82.05,53.6 82.05,54.1 R77.2@82.05,54.6
PB23: R80.2 R81.2 U5.B6 | length 22.1
  L1 - Top Layer w0.125: U5.B6@74.125,68.775 73.8,68.45 73.8,65.85 76.6,63.05 76.6,60.5 76.8,60.3 77.1,60.3 77.3,60.5 77.3,61.4 77.5,61.6 77.8,61.6 78,61.4 78,60.2 78.4,59.8 79.3,59.8 79.6,59.5 79.6,59.2 79.3,58.9 78.8,58.9 78.6,58.7 78.6,58.4 78.8,58.2 80.6,58.2 81.7,57.1 82.05,57.1
  L1 - Top Layer w0.5: R81.2@82.05,56.6 82.05,57.1 R80.2@82.05,57.6
PB24: R82.2 R85.2 U5.A8 | length 22.1
  L1 - Top Layer w0.125: U5.A8@72.825,68.125 72.825,64.875 74.4,63.3 74.4,60.2 81.5,53.1 R82.2@83.95,53.1
  L1 - Top Layer w0.5: R85.2@83.95,52.1 R82.2@83.95,53.1
PC31: R86.2 R88.2 U5.M13 | length 94.4
  L1 - Top Layer w0.125: v1(60.999,34) 77.4,34 R88.2@84.05,27.35 ; v4(69.22,75.6) 69.25,75.6 U5.M13@69.575,75.275 ; R88.2@84.05,27.35 R86.2@85.05,27.35
  L4 - Bottom Layer w0.1: 67.859,75.925 68.895,75.925
  L4 - Bottom Layer w0.125: v1(60.999,34) 53.1,41.9 53.1,46.325 50.125,49.3 50.125,58.575 49.6,59.1 49.6,73.7 54.3,78.4 59.725,78.4 60.875,77.25 63.3,77.25 64.625,75.925 67.859,75.925 ; 68.895,75.925 v4(69.22,75.6)
POWER_EN: D1.2 Q4.3 R11.1 R16.1 U3.16 | length 11.2
  L1 - Top Layer w0.15: Q4.3@13.55,50.1 R16.1@13.55,47.6 16.915,47.6 D1.2@17.2,47.885 17.766,47.885 20.581,50.7 U3.16@20.581,51.068
QSPI_CS_PB20: R72.1 U26.2 | length 15.7
  L1 - Top Layer w0.125: R72.1@84.85,58.1 87.9,58.1 88.5,57.5 v2@94.5,57.5 ; v2(94.4,52.9) 94.8,53.3 U26.2@95.425,53.3
  L4 - Bottom Layer w0.125: v2(94.4,52.9) v2(94.4,57.5)
QSPI_CS_PB20_enabled: R106.1 U8.1 U26.4 | length 3
  L1 - Top Layer w0.125: U8.1@91.305,53.55 91.705,53.95 v2(92.2,53.95) U26.4@93.225,53.95
  L4 - Bottom Layer w0.125: v2(92.2,53.95) 92.95,53.95 R106.1@93.1,53.8
QSPI_IO0_PB21: R75.1 R103.1 U8.5 | length 19.1
  L1 - Top Layer w0.125: R75.1@84.85,55.1 v2(85.8,55.1) ; U8.5@87.495,46.25 87.495,47.495 v2(87.5,47.5)
  L4 - Bottom Layer w0.125: v2(85.8,55.1) 85.8,45.5 86.1,45.2 86.4,45.2 86.6,45.4 86.6,48.6 86.6,48.7 86.8,48.9 87.2,48.9 87.5,48.6 R103.1@87.5,46.75
QSPI_IO1_PB22: R79.1 R102.1 U8.2 | length 22
  L1 - Top Layer w0.125: R79.1@82.95,53.6 85.8,53.6 87.7,55.5 95.6,55.5 95.8,55.3 95.8,54.9 95.6,54.7 90.2,54.7 v2(90.1,54.8) 90.035,54.735 U8.2@90.035,53.55
  L4 - Bottom Layer w0.125: R102.1@90.1,54.05 v2(90.1,54.8)
QSPI_IO2_PB23: R81.1 R101.1 U8.3 | length 19
  L1 - Top Layer w0.125: R81.1@82.95,56.6 86.2,56.6 86.6,57 v2(87.4,57) ; v2(88.7,54.8) 88.765,54.735 U8.3@88.765,53.55
  L4 - Bottom Layer w0.125: v2(87.4,57) 87.9,57 88.3,56.6 88.3,56.1 87,54.8 87,51.3 87.2,51.1 87.9,51.1 88.1,51.3 88.1,52.7 87.9,52.9 87.9,54.4 88.3,54.8 v2(88.7,54.8) R101.1@88.7,54.05
QSPI_IO3_PB24: R85.1 R100.1 U8.7 | length 18.4
  L1 - Top Layer w0.125: R85.1@84.85,52.1 86.25,50.7 v2(90,50.7) ; U8.7@90.035,46.25 90.035,47.435 v2(90.1,47.5)
  L4 - Bottom Layer w0.125: v2(90,50.7) 90,51.3 89.8,51.5 88.9,51.5 88.7,51.3 88.7,51 88.4,50.7 87.8,50.7 87.6,50.5 87.6,50.1 87.8,49.9 90,49.9 90.2,49.7 90.2,49.4 90,49.2 89.3,49.2 89.1,49 89.1,48.7 89.3,48.5 89.9,48.5 90.1,48.3 v2(90.1,47.5) R100.1@90.1,46.75
QSPI_SCK_PB19: R70.1 R99.1 U8.6 | length 18.5
  L1 - Top Layer w0.125: R70.1@82.95,59.6 83.15,59.8 v2(85.9,59.8) ; U8.6@88.765,46.25 88.765,47.465 v2(88.8,47.5)
  L4 - Bottom Layer w0.125: v2(85.9,59.8) 85.9,57.2 86.5,56.6 86.5,50.5 88.8,48.2 R99.1@88.8,46.75
RTS/SDA: J10.6 R171.1 U24.10 | length 24.2
  L1 - Top Layer w0.125: U24.10@133.2,26.31 R171.1@133.2,28.65
  L4 - Bottom Layer w0.125: v2(133.2,27.8) 133.2,15.8 136.91,12.09 J10.6@136.91,7.5
SDMMC0_CD_PA23: J4.10 R108.1 U5.J4 | length 67.7
  L1 - Top Layer w0.125: U5.J4@75.425,73.343 U5.J4@75.425,73.325 v4(75.75,73.65) ; v3(91.8,75) v2(110.2,75) ; R108.1@117.95,52.4 120.125,52.4 J4.10@120.2,52.325
  L4 - Bottom Layer w0.125: v4(75.75,73.65) 77.65,73.65 77.8,73.8 80.1,73.8 80.9,74.6 91.4,74.6 v3(91.8,75) ; v2(110.2,75) 111.1,74.1 111.1,67.6 112.3,66.4 115.4,66.4 121.2,60.6 121.2,54.7 v2(118.9,52.4)
SDMMC0_CLK_PA17: J4.5 U5.J3 | length 70.4
  L1 - Top Layer w0.125: U5.J3@76.075,73.325 76.408,72.992 85.108,72.992 92.1,66 108,66 ; v2(118.8,46.4) 120.125,46.4 J4.5@120.2,46.475
  L4 - Bottom Layer w0.125: v2(108.3,66) 108.3,57.3 116.05,49.55 116.05,49.05 115.7,48.7 115.1,48.7 113.1,50.7 112.425,50.7 112,50.275 112,49.775 115.375,46.4 v2(118.8,46.4)
SDMMC0_CMD_PA16: J4.2 R109.1 U5.K2 | length 70.6
  L1 - Top Layer w0.125: U5.K2@76.725,73.975 77.05,74.3 87.5,74.3 91.8,70 v2(107,70) ; R109.1@117.95,54 120.175,54 J4.2@120.2,53.975
  L4 - Bottom Layer w0.125: v2(107,70) 107,68.1 111,64.1 111,59.3 111.4,58.9 111.9,58.9 112.3,59.3 112.3,61.6 112.6,61.9 113.1,61.9 115.5,59.5 115.5,53.6 115.9,53.2 116.5,53.2 116.9,53.6 116.9,56.8 117.3,57.2 117.8,57.2 118.2,56.8 118.2,54.7 v2(118.9,54)
SDMMC0_DAT0_PA15: J4.7 R111.1 U5.H6 | length 67.6
  L1 - Top Layer w0.125: U5.H6@74.125,72.675 v4(74.45,72.35) ; v3(84.7,72) 85.3,72 91.8,65.5 v2(107.7,65.5) ; R111.1@117.95,41.6 v2(118.8,41.6) 120.15,41.6 J4.7@120.2,41.55
  L4 - Bottom Layer w0.1: v4(74.45,72.35) 74.775,72.675 81.9,72.675
  L4 - Bottom Layer w0.125: 81.9,72.675 84.025,72.675 v3(84.7,72) ; v2(107.7,65.5) 107.7,52.7 v2(118.8,41.6)
SDMMC0_DAT1_PA18: J4.8 R110.1 U5.J1 | length 70.7
  L1 - Top Layer w0.125: U5.J1@77.375,73.325 85.675,73.325 92,67 v2(107,67) ; R110.1@117.95,39.9 v2(118.9,39.9) 120.15,39.9 J4.8@120.2,39.85
  L4 - Bottom Layer w0.125: v2(107,67) 107,52.4 112.7,46.7 112.7,40.9 115,38.6 117.6,38.6 v2(118.9,39.9)
SDMMC0_DAT2_PA19: J4.9 R113.1 U5.J5 | length 67.7
  L1 - Top Layer w0.125: U5.J5@74.775,73.325 v4(75.1,73.65) ; v3(91.8,73) v2(110.2,73) ; R113.1@117.95,59 v2(118.9,59) 120.175,59 J4.9@120.2,58.975
  L4 - Bottom Layer w0.1: 75.659,73.325 75.841,73.325
  L4 - Bottom Layer w0.125: v4(75.1,73.65) 75.425,73.325 75.659,73.325 ; 75.841,73.325 77.8,73.325 77.975,73.5 80.575,73.5 81.275,74.2 90.6,74.2 v3(91.8,73) ; v2(110.2,73) 110.2,67.7 112.2,65.7 115,65.7 120.1,60.6 120.1,60.2 119.8,59.9 119.4,59.9 116.6,62.7 116.1,62.7 115.9,62.5 115.9,62 v2(118.9,59)
SDMMC0_DAT3_PA20: J4.1 R112.1 U5.J2 | length 70.5
  L1 - Top Layer w0.125: U5.J2@76.725,73.325 77.052,73.652 86.148,73.652 91.787,68.013 96.313,68.013 96.6,68.3 v2(107.7,68.3) ; R112.1@118.05,56.5 v2(118.9,56.5) 120.175,56.5 J4.1@120.2,56.475
  L4 - Bottom Layer w0.125: v2(107.7,68.3) 107.7,70.2 107,70.9 107,76.7 107.2,76.9 107.7,76.9 107.9,76.7 107.9,71.9 108.5,71.3 108.5,67.4 110.4,65.5 110.9,65.5 118.9,57.5 v2(118.9,56.5)
SDMMC1_WILC3000_CK_PA13: R55.1 U24.22 | length 96.7
  L1 - Top Layer w0.125: v2(94.051,76.001) v2@113.1,76.001 ; v2(126.05,15.3) U24.22@126.9,15.3
  L4 - Bottom Layer w0.125: R55.1@93.301,76 v2@94.051,76 ; v2(113.1,76) 126.05,63.05 126.05,49 124.8,47.75 124.8,30.5 125.4,29.9 126.8,29.9 127.2,29.5 127.2,28.7 126.8,28.3 126.4,28.3 126,27.9 126,20.6 126.3,20.3 127.4,20.3 127.8,19.9 127.8,19 127.4,18.6 126.2,18.6 125.8,18.2 125.8,17.2 126.2,16.8 127.9,16.8 128.3,16.4 128.3,15.7 127.9,15.3 v2(126.05,15.3)
SDMMC1_WILC3000_CMD_PA12: R52.1 R167.1 U24.23 | length 103.8
  L1 - Top Layer w0.125: R52.1@93.251,71.5 112.8,71.5 v2(113.1,71.8) ; v2(126.05,14.2) U24.23@126.9,14.2
  L4 - Bottom Layer w0.125: v2(113.1,71.8) 114.3,73 114.9,73 115.4,72.5 115.4,72 114.4,71 114.4,70.5 114.9,70 115.4,70 116.4,71 116.9,71 117.4,70.5 117.4,70 116.5,69.1 116.5,68.6 117,68.1 117.5,68.1 118.4,69 118.9,69 119.4,68.5 119.4,68 118.5,67.1 118.5,66.6 119,66.1 119.5,66.1 120.4,67 120.9,67 121.4,66.5 121.4,66 120.5,65.1 120.5,64.6 121,64.1 121.5,64.1 122.4,65 122.9,65 123.4,64.5 123.4,64 122.5,63.1 122.5,62.6 123,62.1 123.5,62.1 124.1,62.7 124.6,62.7 124.9,62.4 124.9,57.9 124.9,48.9 123.8,47.8 123.8,30.4 124.9,29.3 124.9,20.4 124.9,15.35 v2(126.05,14.2) R167.1@127.05,14.2
SDMMC1_WILC3000_DAT0_PA11: R46.1 R166.1 U24.24 | length 96.2
  L1 - Top Layer w0.125: v2(94,71) v2(113.1,71) ; v2(126.05,13) U24.24@126.9,13
  L4 - Bottom Layer w0.125: R46.1@93.25,71 v2(94,71) ; v2(113.1,71) 123.7,60.4 123.7,60.1 123.4,59.8 122.6,59.8 122.2,59.4 122.2,58.8 122.6,58.4 123.6,58.4 124,58 124,57.4 123.6,57 122.6,57 122.2,56.6 122.2,56 122.6,55.6 123.6,55.6 124,55.2 124,54.6 123.6,54.2 122.6,54.2 122.2,53.8 122.2,53.2 122.6,52.8 123.6,52.8 124,52.4 124,51.8 123.6,51.4 122.6,51.4 122.2,51 122.2,50.4 122.6,50 123.6,50 124,49.6 124,49 123,48 123,30.1 124.05,29.05 124.05,15 v2(126.05,13) R166.1@127.05,13
SDMMC1_WILC3000_DAT1_PA02: R31.1 R165.1 U24.25 | length 102.9
  L1 - Top Layer w0.125: R31.1@93.25,81.5 v2(113.1,81.5) ; U24.25@129.6,12.4 v2(129.6,13.25)
  L4 - Bottom Layer w0.125: v2(113.1,81.5) 113.1,80 128.7,64.4 128.7,33.6 129.3,33 129.3,27.4 128.8,26.9 127.6,26.9 127.2,26.5 127.2,25.3 127.6,24.9 128.8,24.9 129.2,24.5 129.2,23.4 128.8,23 127.6,23 127.2,22.6 127.2,21.5 127.6,21.1 128.8,21.1 129.2,20.7 129.2,18.5 129.6,18.1 v2(129.6,13.25) R165.1@129.6,12.35
SDMMC1_WILC3000_DAT2_PA03: R38.1 R164.1 U24.26 | length 97.1
  L1 - Top Layer w0.125: v2(94,81) v2(113.8,81) ; U24.26@130.8,12.4 v2(130.8,13.25)
  L4 - Bottom Layer w0.125: R38.1@93.25,81 v2(94,81) ; v2(113.8,81) 113.8,80 129.7,64.1 129.7,62.9 129.7,34.3 130.2,33.8 130.2,18.7 130.8,18.1 v2(130.8,13.25) R164.1@130.8,12.35
SDMMC1_WILC3000_DAT3_PA04: R40.1 R163.1 U24.27 | length 103.5
  L1 - Top Layer w0.125: R40.1@93.25,79.5 v2(115,79.5) ; U24.27@132,12.4 v2(132,13.25)
  L4 - Bottom Layer w0.125: v2(115,79.5) 130.9,63.6 130.9,57.4 131.7,56.6 132.6,56.6 133.5,55.7 133.5,54.4 132.7,53.6 131.7,53.6 130.9,52.8 130.9,49.6 131.8,48.7 132.9,48.7 133.6,48 133.6,46.6 132.9,45.9 132,45.9 130.9,44.8 130.9,34.5 131.55,33.85 131.55,18.55 132,18.1 v2(132,13.25) R163.1@132,12.35
SEL_FNCT1_PD19: U5.P16 U14.1 U14.7 U16.1 U16.7 | length 123.4
  L1 - Top Layer w0.125: v1(46.938,79.438) 57.762,79.438 60.2,77 63.275,77 63.7,76.575 U5.P16@67.625,76.575 ; v1(103.3,103.3) 104.3,102.3 104.3,94.3 v2(106.1,92.5) ; U14.1@116.75,86.675 116.75,87.65 v2(117.25,88.15) ; U14.7@117.25,89.325 v2(117.25,88.15) ; U16.1@120.75,86.675 120.75,87.45 ; U16.7@121.25,89.325 121.25,87.95 120.75,87.45 ; v2(117.25,88.15) 118.35,88.15 119.05,87.45 120.75,87.45
  L4 - Bottom Layer w0.125: v1(46.938,79.438) 46.938,79.538 48.6,81.2 48.6,82.6 69.3,103.3 v1(103.3,103.3) ; v2(106.1,92.5) 110.4,92.5 113.725,89.175 116.225,89.175 v2(117.25,88.15)
SEL_FNCT2_PD20: U5.M11 U15.1 U15.7 U17.1 U17.7 | length 102.6
  L1 - Top Layer w0.125: v1(61.3,96.45) 59.9,95.05 59.9,86.1 64.3,81.7 v1(64.3,81.675) ; v1(65.3,78.1) 65.525,78.325 67.617,78.325 67.945,77.997 67.945,77.723 70.068,75.6 70.55,75.6 U5.M11@70.875,75.275 ; v2(104.7,104.1) 104.7,103.397 105.25,102.848 105.25,95.242 107.95,92.542 U17.7@107.95,89.125 107.95,88.06 ; U17.1@107.45,86.475 107.45,87.56 107.95,88.06 ; U15.1@111.25,86.465 111.25,87.55 ; U15.7@111.75,89.115 111.75,88.05 111.25,87.55 ; 107.95,88.06 108.94,88.06 109.6,87.4 110.6,87.4 110.75,87.55 111.25,87.55
  L4 - Bottom Layer w0.125: v1(61.3,96.45) 61.35,96.45 70.7,105.8 104.1,105.8 104.7,105.2 v2(104.7,104.1) ; v1(64.3,81.675) 64.3,79.1 v1(65.3,78.1)
SENSE1_N: R7.4 U4.12 | length 5.9
  L1 - Top Layer w0.35: U4.12@26.075,64.25 26.075,64.025 26.675,63.425 28.6,61.5 28.6,60.7 28.95,60.35 R7.4@29.75,60.35
SENSE1_P: R7.3 U4.11 | length 5.9
  L1 - Top Layer w0.35: U4.11@25.425,64.25 25.425,63.675 27.9,61.2 27.9,60.7 27.55,60.35 R7.3@26.75,60.35
SENSE2_N: R8.4 U4.14 | length 3.2
  L1 - Top Layer w0.35: U4.14@27.1,65.925 28.9,65.925 29.375,66.4 R8.4@29.375,67.1
SENSE2_P: R8.3 U4.13 | length 3.2
  L1 - Top Layer w0.35: U4.13@27.1,65.275 28.9,65.275 29.375,64.8 R8.3@29.375,64.1
SENSE3_N: R9.4 U4.7 | length 3.2
  L1 - Top Layer w0.35: R9.4@20.8,67.1 20.8,66.4 21.275,65.925 U4.7@23.1,65.925
SENSE3_P: R9.3 U4.8 | length 3.2
  L1 - Top Layer w0.35: R9.3@20.8,64.1 20.8,64.8 21.275,65.275 U4.8@23.1,65.275
SENSE4_N: R10.4 U4.9 | length 5.9
  L1 - Top Layer w0.35: R10.4@20.45,60.35 21.25,60.35 21.6,60.7 21.6,61.5 23.525,63.425 24.125,64.025 U4.9@24.125,64.25
SENSE4_P: R10.3 U4.10 | length 5.9
  L1 - Top Layer w0.35: R10.3@23.45,60.35 22.65,60.35 22.3,60.7 22.3,61.2 24.775,63.675 U4.10@24.775,64.25
SHDN: R19.2 U5.R11 | length 93.2
  L1 - Top Layer w0.125: R19.2@7.4,55.25 v2(7.4,56.1) ; v2(34.2,91.7) 55.875,91.7 58.2,89.375 58.2,86.2 63.3,81.1 68.9,81.1 70.55,79.45 70.55,77.55 U5.R11@70.875,77.225
  L4 - Bottom Layer w0.125: v2(7.4,56.1) 7.4,60 29.3,81.9 29.3,86.7 34.2,91.6 v2(34.2,91.7)
STARTB: Q3.3 Q4.1 Q5.1 R15.1 R18.2 | length 8.7
  L1 - Top Layer w0.15: R15.1@9.65,49.4 Q3.3@9.65,51.9 ; Q4.1@11.25,51.05 10.4,51.9 Q3.3@9.65,51.9 ; Q5.1@11.25,54.65 9.9,54.65 R18.2@9.6,54.35 9.6,51.95 Q3.3@9.65,51.9
TCK_3U: J18.12 U27.A7 | length 19.9
  L1 - Top Layer w0.125: J18.12@3.625,94.73 7.47,94.73 v1(7.5,94.7) ; v1(17.275,85.3) 17.975,85.3 U27.A7@18.275,85.6
  L4 - Bottom Layer w0.125: v1(7.5,94.7) 10.5,91.7 10.5,89.7 14.9,85.3 v1(17.275,85.3)
TDI_3U: J18.8 U27.B9 | length 18.6
  L1 - Top Layer w0.125: J18.8@3.625,92.73 11.57,92.73 v1(11.6,92.7) ; v1(16.475,87.2) 17.621,87.2 18.021,86.8 18.675,86.8 U27.B9@19.075,87.2
  L4 - Bottom Layer w0.125: v1(11.6,92.7) 11.6,92.075 v1(16.475,87.2) v1@16.35,87.2
TDO_3U: J18.10 U27.B8 | length 21.9
  L1 - Top Layer w0.125: J18.10@3.625,93.73 7.77,93.73 v1(7.8,93.7) ; v3(18.675,86) U27.B8@19.075,86.4
  L4 - Bottom Layer w0.125: v1(7.8,93.7) 10,91.5 10,88 13.3,84.7 17.382,84.7 18.675,85.993 v3(18.675,86)
TMS_3U: J18.14 U27.C7 | length 21.4
  L1 - Top Layer w0.125: J18.14@3.625,95.73 7.37,95.73 v1(7.4,95.7) ; v3(19.475,86) U27.C7@19.875,85.6
  L4 - Bottom Layer w0.125: v1(7.4,95.7) 11,92.1 11,90.4 14.8,86.6 18.875,86.6 v3(19.475,86)
TRESIN: R234.1 R236.2 U27.G8 | length 5.4
  L1 - Top Layer w0.125: R234.1@22.075,91.35 R234.1@22.025,91.3 R236.2@22.025,90.2 22.025,89.325 22.675,88.675 22.675,86.8 U27.G8@23.075,86.4
TRESOUT: R236.1 U27.G10 | length 2.3
  L1 - Top Layer w0.125: R236.1@22.925,90.2 23.075,90.05 U27.G10@23.075,88
TRSTIN: R233.2 U27.J10 | length 2.3
  L1 - Top Layer w0.125: U27.J10@24.675,88 24.675,89.95 R233.2@24.925,90.2
TRSTOUT: R233.1 U27.H9 | length 3.4
  L1 - Top Layer w0.125: U27.H9@23.875,87.2 23.475,87.6 23.475,89.65 R233.1@24.025,90.2
UART_RXD: J9.2 U24.17 | length 12.4
  L1 - Top Layer w0.125: v1(121.7,23.4) 124,23.4 124.9,22.5 125.85,22.5 126.98,21.37 U24.17@127.62,21.37
  L4 - Bottom Layer w0.125: J9.2@116.6,24.06 117.56,23.1 121.4,23.1 v1(121.7,23.4)
UART_TXD: J9.3 U24.16 | length 12.7
  L1 - Top Layer w0.125: v1(121.7,24.5) 123.6,24.5 125.2,22.9 127.29,22.9 U24.16@127.62,22.57
  L4 - Bottom Layer w0.125: J9.3@116.6,26.6 118.7,24.5 v1(121.7,24.5)
USB_5V: C8.1 C9.1 FB1.2 Q2.1 R5.2
USBA_N: J7.2 U5.R12 | length 108.4
  L1 - Top Layer w0.125: J7.2@35.45,5.125 35.612,5.287 35.612,6.072 36.075,6.535 36.075,7.76 36.5,8.185 36.5,9 37.763,10.263 37.763,11.938 v2(37.6,12.1) ; v2(52.2,83.4) 52.387,83.213 52.387,82.925 52.738,82.575 53.66,82.575 53.785,82.7 60.34,82.7 62.74,80.3 68.84,80.3 69.9,79.24 69.9,77.738 70.225,77.413 U5.R12@70.225,77.225
  L4 - Bottom Layer w0.125: v2(37.6,12.1) 37.763,12.263 37.763,13.122 40.675,16.035 40.675,33.175 47.475,39.975 47.475,47.165 46.2,48.44 46.2,76.86 52.387,83.047 52.387,83.213 v2(52.2,83.4)
USBA_P: J7.3 U5.T12 | length 108.4
  L1 - Top Layer w0.125: J7.3@36.1,5.125 35.937,5.287 35.937,5.937 36.4,6.4 36.4,7.625 36.825,8.05 36.825,8.865 38.088,10.128 38.088,11.938 v2(38.25,12.1) ; v2(52.9,83.4) 52.713,83.213 52.713,83.06 52.872,82.9 53.525,82.9 53.625,83 53.625,83.4 53.825,83.6 54.125,83.6 54.325,83.4 54.325,83.2 54.5,83.025 60.475,83.025 62.875,80.625 68.975,80.625 70.225,79.375 U5.T12@70.225,77.875
  L4 - Bottom Layer w0.125: v2(38.25,12.1) 38.088,12.263 38.088,12.988 41,15.9 41,33.04 47.8,39.84 47.8,47.3 46.525,48.575 46.525,76.725 52.713,82.912 52.713,83.213 v2(52.9,83.4)
USBA_VBUS_5V: C7.1 C106.2 FB1.1 J7.1 R148.1 VBUS_USBA.1 | length 38.8
  L1 - Top Layer w0.5: J7.1@34.8,5.125 34.8,7
  L1 - Top Layer w1: FB1.1@22.8,30.2 24.7,30.2 32.7,22.2 34.7,22.2 35,22.5 R148.1@35,28.625
  L1 - Top Layer w1.5: 34.8,7 VBUS_USBA.1@34.8,18.2 34.8,22.2
USBA_VBUSDETECT_PB16: R148.2 R150.2 U5.B3 | length 75.3
  L1 - Top Layer w0.125: v1(33.9,31.075) 33.95,31.025 R150.2@35,31.025 R148.2@35,29.525 ; v1(47,46.3) v1(75.7,46.3) ; U5.B3@76.075,68.775 76.394,68.456 76.394,67.95 76.475,67.869 76.475,66.625 76.9,66.2 v3(76.9,65.1)
  L4 - Bottom Layer w0.125: v1(33.9,31.075) 33.9,33.2 v1(47,46.3) ; v1(75.7,46.3) 76,46.6 76,64.2 v3(76.9,65.1)
USBB_EN_5V_PD15: R153.2 U5.M16 U19.1 | length 56.7
  L1 - Top Layer w0.125: U19.1@57.905,39.1 57.875,39.13 R153.2@57.875,40.95 v1(58.725,40.95) ; v1(60.05,75.725) 62.325,75.725 62.525,75.525 65.875,75.525 66.125,75.275 U5.M16@67.625,75.275
  L4 - Bottom Layer w0.125: v1(58.725,40.95) 57.8,41.875 57.8,44.6 51,51.4 51,58.9 50.4,59.5 50.4,60.9 51,61.5 51,73.1 53.9,76 58.6,76 58.875,75.725 v1(60.05,75.725)
USBB_N: J8.2 U5.T14 | length 87
  L1 - Top Layer w0.125: v2@59.275,82.1 59.275,81.865 61.69,79.45 68.35,79.45 69.1,78.7 69.1,78.238 68.925,78.063 U5.T14@68.925,77.875
  L4 - Bottom Layer w0.125: J8.2@49.5,16.28 49.5,16.5 50.275,17.275 50.275,20.175 51.77,21.67 51.77,39.43 50.675,40.525 50.675,46.965 49.375,48.265 49.375,49.925 48.9,50.4 48.9,74.76 54.065,79.925 58.125,79.925 59.3,81.1 59.3,81.9 v2(59.1,82.1)
USBB_OVCUR: R152.1 U6.12 U19.2 | length 30.2
  L1 - Top Layer w0.125: U6.12@36.65,51.485 36.65,48.75 37.075,48.325 37.075,46.125 38.812,44.388 41.013,44.388 41.9,43.5 v1(55.1,43.5) ; v1(55.786,40.954) R152.1@56.636,40.954 56.636,39.201 56.635,39.2 U19.2@56.635,39.1
  L4 - Bottom Layer w0.125: v1(55.1,43.5) 55.1,41.64 v1(55.786,40.954)
USBB_P: J8.3 U5.T13 | length 87
  L1 - Top Layer w0.125: v2@59.6,82.1 59.6,82 61.825,79.775 68.485,79.775 69.425,78.835 69.425,78.213 69.575,78.063 U5.T13@69.575,77.875
  L4 - Bottom Layer w0.125: J8.3@51.5,16.28 51.5,16.4 50.6,17.3 50.6,20.04 52.095,21.536 52.095,39.564 51,40.66 51,47.1 49.7,48.4 49.7,50.06 49.225,50.535 49.225,74.625 54.2,79.6 58.26,79.6 59.625,80.965 59.625,81.925 v2(59.8,82.1)
USBB_VBUS_5V: C114.1 C115.1 C116.1 FB6.2 J8.1 VBUS_USBB.1 | length 25
  L1 - Top Layer w1.5: VBUS_USBB.1@40.5,18.2 42.1,19.8 47,19.8 ; J8.1@47,16.28 47,19.8 ; FB6.2@54.7,30 53.082,30 48.6,25.518 C116.1@48.6,25 47,23.4 47,19.8
USBC_EN_5V_PD16: R155.2 U5.M14 U20.1 | length 61.8
  L1 - Top Layer w0.125: U20.1@48.805,39.1 48.83,39.125 R155.2@48.83,40.86 49.205,41.235 53.535,41.235 v1(54.1,41.8) ; v4(68.6,75.6) U5.M14@68.925,75.275
  L4 - Bottom Layer w0.125: v1(54.1,41.8) 54.1,46.8 50.5,50.4 50.5,59 50,59.5 50,73.5 53.35,76.85 62.75,76.85 64,75.6 v4(68.6,75.6)
USBC_N: J8.6 U5.N12 | length 101
  L1 - Top Layer w0.1: v4(69.9,76.25) U5.N12@70.225,75.925
  L4 - Bottom Layer w0.1: 69.575,77.325 69.575,76.575 v4(69.9,76.25)
  L4 - Bottom Layer w0.125: J8.6@49.5,13.66 49.5,13.4 50.3,12.6 50.3,11.419 50.1,11.219 49.8,11.219 49.6,11.419 49.6,11.96 49.4,12.16 49.2,12.16 49,11.96 49,11.419 48.8,11.219 48.6,11.219 48.425,11.394 48.425,18.975 47.23,20.17 47.23,26.37 48.8,27.94 48.8,49.06 47.9,49.96 47.9,75.888 55.113,83.1 64.24,83.1 69.575,77.765 69.575,77.325
USBC_OVCUR: R154.1 U6.13 U20.2 | length 20.6
  L1 - Top Layer w0.125: U6.13@37.15,51.485 37.15,49.2 37.787,48.562 37.787,46.538 39.125,45.2 41.15,45.2 42.35,44 v1(46.15,44) ; v1(46.68,40.86) R154.1@47.53,40.86 47.535,40.855 U20.2@47.535,39.1
  L4 - Bottom Layer w0.125: v1(46.15,44) 46.15,41.39 v1(46.68,40.86)
USBC_P: J8.7 U5.P12 | length 101
  L1 - Top Layer w0.1: v4(69.9,76.9) U5.P12@70.225,76.575
  L4 - Bottom Layer w0.1: v4(69.9,76.9) v4@69.902,76.902
  L4 - Bottom Layer w0.125: J8.7@51.5,13.66 51.5,13.5 50.625,12.625 50.625,11.285 50.235,10.894 48.465,10.894 48.1,11.26 48.1,18.84 46.905,20.036 46.905,26.505 48.475,28.075 48.475,48.925 47.575,49.825 47.575,76.022 54.978,83.425 64.375,83.425 69.9,77.9 v4(69.9,76.9)
USBC_VBUS_5V: C120.1 C121.1 C122.1 FB8.2 J8.5 VBUS_USBC.1 | length 29.8
  L1 - Top Layer w1.5: FB8.2@45.5,30 43,30 C120.1@41.8,28.8 43.2,27.4 C122.1@43.2,25 37.9,19.7 VBUS_USBC.1@37.9,18.2 37.9,16.1 40.34,13.66 J8.5@47,13.66
USER_BUTTON_PD18: R192.1 U5.L13 | length 68.7
  L1 - Top Layer w0.125: v4(69.25,74.95) U5.L13@69.575,74.625
  L4 - Bottom Layer w0.125: R192.1@63.15,29.4 63.2,29.45 63.2,42.3 53.8,51.7 53.8,52.6 51.8,54.6 51.8,58.6 52.8,59.6 52.8,60.2 51.575,61.425 51.575,72.975 54.2,75.6 58.2,75.6 58.85,74.95 v4(69.25,74.95)
USER_nRST: C145.1 R190.1 SW3.1 SW3.2 | length 90.5
  L1 - Top Layer w0.2: R190.1@104.1,89.05 105.45,89.05 v2(105.5,89) ; v2(104.7,12.8) 104.75,12.75 SW3.1@104.75,11.05 SW3.2@104.75,1.95
  L4 - Bottom Layer w0.2: v2(104.7,12.8) 104.7,36.7 103,38.4 103,53.5 105.5,56 105.5,83.5 105.8,83.8 105.8,88.7 v2(105.5,89)
VBUS_JLINK: C171.1 J22.1 U28.4 U28.6 VBUS_JLINK.1 | length 6.3
  L1 - Top Layer w0.2: U28.6@8.375,66.2 7.4,66.2 C171.1@7,66.6 7.4,67 U28.4@8.375,67
  L1 - Top Layer w0.5: J22.1@5.119,65.3 VBUS_JLINK.1@7,65.3 C171.1@7,66.6
VDD_1V8: C11.1 C12.1 L1.2 R7.1 U3.9 U3.10 | length 1.4
  L1 - Top Layer w0.3: U3.10@22.281,53.268 22.281,54 ; U3.9@22.781,53.268 22.781,53.963
VDD_1V15: C22.1 R8.1 U3.11 | length 16.9
  L1 - Top Layer w0.3: 21.4,54.6 21.781,54.219 ; U3.11@21.781,53.268 21.781,54.219 ; C22.1@21.781,55.253 21.781,54.219
  L1 - Top Layer w1: C22.1@21.4,55 C22.1@21.4,55.75 21.4,58
  L3 - PWR w1: 21.4,58 v1(21.8,58) 26.575,58 29.4,60.825 v1(29.4,62.8) v1@29.4,63
  other v1: 21.4,57.6 21,58 21.4,58.4 28.9,63.2 29.9,63.2
VDD_3V3: C29.2 C53.1 C54.1 C55.1 C56.1 C57.2 C58.1 C59.1 C60.1 C61.1 C89.1 C90.1 C93.1 C95.1 C99.1 C102.1 C103.1 C104.1 C105.1 C125.1 C129.1 C133.1 C134.2 C135.1 C136.1 C146.2 C147.2 C174.2 C176.1 C177.2 C179.1 D2.1 D3.1 FB2.2 FB12.1 J4.4 J10.8 J14.7 J16.1 J16.17 J23.1 J23.2 LD1.2 R4.2 R9.1 R10.2 R17.2 R33.2 R34.2 R35.2 R36.2 R37.2 R61.2 R62.2 R83.2 R84.2 R97.2 R98.2 R99.2 R100.2 R101.2 R102.2 R103.2 R106.2 R107.2 R108.2 R109.2 R110.2 R111.2 R112.2 R113.2 R114.2 R115.2 R116.2 R122.1 R123.1 R125.1 R129.1 R135.1 R138.1 R152.2 R154.2 R160.2 R161.2 R163.2 R164.2 R165.2 R166.2 R167.2 R168.2 R186.1 R187.1 R188.1 R189.2 R204.2 R217.2 R256.2 R257.2 R258.1 R259.1 R260.2 R270.1 U6.18 U7.6 U8.8 U9.12 U9.34 U9.37 U9.39 U11.14 U14.8 U15.8 U16.8 U17.8 U21.8 U23.8 U24.12 U25.5 U26.5 U29.3 U30.3 U30.6 U31.16 U32.16 Y3.4 Y6.1 Y6.4 Y7.3 Y7.4 Y8.4 | length 126.9
  L1 - Top Layer w0.25: R116.2@38.2,90.15 38.2,90.7 v1(38.25,90.75) ; C61.1@40.55,66.7 40.75,66.9 U9.34@40.75,68.4 ; U9.37@42.25,68.4 42.25,67 C60.1@42.55,66.7 ; U9.12@42.25,87.6 42.25,89.1 C58.1@42.45,89.3 ; U9.39@43.25,68.4 43.25,67.1 C59.1@43.65,66.7 ; R114.2@43.7,90.45 43.7,91 v1(43.75,91.05) ; R115.2@44.8,90.15 44.8,90.7 v1(44.85,90.75)
  L1 - Top Layer w0.3: v1(12.6,56.95) 12.65,56.9 R17.2@12.65,56.2 ; v1(19.4,108.7) 19.45,108.75 R256.2@19.45,109.6 ; v1(22.3,108.7) 22.35,108.75 R258.1@22.35,109.6 ; v1(24.3,108.7) 24.35,108.75 R257.2@24.35,109.6 ; v1(31,108.7) 31.05,108.75 R259.1@31.05,109.6 ; v1(32.05,52.9) R4.2@32.75,52.9 ; v1(32.05,54) R33.2@32.75,54 ; R34.2@34.4,58.55 v1(34.4,59.25) ; R35.2@35.5,58.55 v1(35.5,59.25) ; v1(35.9,108.7) 35.95,108.75 R260.2@35.95,109.6 ; R36.2@38.75,58.55 v1(38.75,59.25) ; U6.18@39.115,53.45 40.2,53.45 C53.1@40.3,53.35 41.05,53.35 v1(41.1,53.3) ; R37.2@39.85,58.55 v1(39.85,59.25) ; v2(44.3,50.5) R83.2@45.25,50.5 ; v2(44.3,55.5) R84.2@45.25,55.5 ; v1(46.68,41.76) R154.2@47.53,41.76 ; v1(55.786,41.854) R152.2@56.636,41.854 ; v1(65.7,113.6) 65.75,113.65 D2.1@65.75,115.05 ; v1@67.2,105.2 D3.1@67.2,106.6 ; U11.14@75.435,28.95 v2(75.435,29.665) 75.815,29.665 C90.1@76.5,30.35 ; U8.8@91.305,46.25 91.405,46.15 v2(92.25,46.15) C55.1@93.1,46.15 ; v2(92.25,52.9) 92.975,52.9 U26.5@93.225,52.65 ; R62.2@93.25,86.5 93.5,86.5 v2(94,87) ; v2(106.3,90.3) C105.1@106.3,89.45 107.45,89.45 U17.8@107.45,89.125 ; v2(110.1,90.3) C103.1@110.1,89.45 111.15,89.45 U15.8@111.2,89.4 ; v2(115.6,90.5) C102.1@115.6,89.65 116.65,89.65 U14.8@116.7,89.6 ; v2(116.1,37.4) R107.2@116.95,37.4 ; v2(116.2,39.9) R110.2@117.05,39.9 ; v2(116.2,41.6) R111.2@117.05,41.6 ; v2(116.2,52.4) R108.2@117.05,52.4 ; v2(116.2,54) R109.2@117.05,54 ; v2(116.2,56.5) R112.2@117.05,56.5 ; C56.1@116.9,49.35 C57.2@117.9,49.35 119.825,49.35 J4.4@120.2,48.975 ; v2(117.05,58.15) R113.2@117.05,59 ; v2(117.9,48.45) C57.2@117.9,49.3 ; v2(119.6,90.5) C104.1@119.6,89.65 120.65,89.65 U16.8@120.7,89.6 ; Y8.4@120.95,12.4 120.95,11.1 C136.1@121.05,11 121.05,10.25 v2(121.1,10.2) ; v2(123.7,9.5) 123.75,9.55 123.75,11.55 Y7.3@123.8,11.6 Y7.4@123.8,14.3 ; R160.2@124.3,29.95 v2(124.3,30.8) ; R161.2@125.5,29.95 v2(125.5,30.8)
  L1 - Top Layer w0.4: v2(46,102.2) 46.7,101.5 R189.2@46.75,101.5 ; R188.1@54.55,101.8 54.55,102.55 v1(54.6,102.6) ; R187.1@54.55,98 54.55,97.25 v1(54.6,97.2) ; C29.2@64.287,91.2 v1(64.937,91.2) ; R135.1@111.2,108.3 111.2,107.1 v2(111.875,107.1) ; v2(122.55,106.35) C99.1@122.55,107.1 R138.1@122.55,108.3
  L1 - Top Layer w0.5: v1(28.35,106.62) C176.1@28.35,105.77 28.35,105.045 U31.16@28.75,104.645 ; v1(36.95,106.62) C179.1@36.95,105.77 36.95,104.992 U32.16@37.35,104.593 ; v1(40.55,66.05) C61.1@40.55,66.7 ; C58.1@42.45,89.3 v1(42.45,89.95) ; v1(42.55,66.05) C60.1@42.55,66.7 ; v1(43.65,66.05) C59.1@43.65,66.7 ; C29.2@64.287,91.2 64.34,91.147 Y3.4@64.34,89.442 ; v1(73.285,32) 73.3,31.985 R122.1@73.3,31.25 ; R123.1@79.65,28.7 v1(80.5,28.7) ; Y6.4@82.575,23.925 84.3,23.925 C93.1@84.45,24.075 v1(85.25,24.075) ; v1(89.999,44.1) 90.05,44.05 U23.8@90.05,41.925 ; C125.1@90.15,39.15 90.15,38.25 90.2,38.2 ; v1(97.85,19.7) LD1.2@98.6,19.7 ; U7.6@102.1,86.55 102.45,86.9 v1(102.45,87.2) C54.1@102.45,87.9 ; R97.2@104.45,84.8 v1(105.3,84.8) ; R98.2@104.45,87.8 v1(105.3,87.8)
  L1 - Top Layer w1: C134.2@130,29.5 130.8,28.7 U24.12@130.8,26.31
  L4 - Bottom Layer w0.3: U30.6@10.35,106.975 v1(10.35,108.3) U30.3@10.35,109.625 10.35,111 C177.2@10.55,111.2 ; C174.2@12.675,102.975 12.775,102.875 U29.3@14.275,102.875 ; v1(33.4,100.2) 33.5,100.1 R270.1@34.25,100.1 ; v1(71.2,9.2) 71.85,8.55 R125.1@73.2,8.55 ; v2(87.5,45) R103.2@87.5,45.85 ; v2(88.7,52.3) R101.2@88.7,53.15 ; v2(88.8,45) R99.2@88.8,45.85 ; v2(90.1,45) R100.2@90.1,45.85 ; v2(90.1,52.3) R102.2@90.1,53.15 ; C147.2@92.25,51.8 v2(92.25,52.9) R106.2@93.1,52.9 ; R61.2@93.25,87 v2(94,87) ; v2(112.6,14.5) R204.2@113.45,14.5
  L4 - Bottom Layer w0.4: R186.1@60.25,29.4 60.25,30.25 v1(60.3,30.3)
  L4 - Bottom Layer w0.5: C177.2@10.55,111.2 v1(11.4,111.2) ; C174.2@12.675,102.975 v1(12.675,103.825) ; U25.5@45.05,86.375 46.15,86.375 C146.2@46.2,86.425 46.875,86.425 v1(47.1,86.2) ; v1@68.2,24 FB2.2@69.215,24 ; v2(75.435,29.665) 76.18,29.665 76.215,29.7 C89.1@76.615,29.3 ; v2(101.65,96.2) v2(101.65,96.75) R217.2@101.65,97.5 ; R168.2@125.5,11.45 v2(127.2,11.45) 127.9,11.45 ; R167.2@127.95,14.2 R166.2@127.95,13 v2(127.95,12) 127.95,11.5 127.9,11.45 ; R163.2@132,11.45 v2(128.7,11.45) 127.9,11.45
  L4 - Bottom Layer w1: 103.5,119.9 FB12.1@103.5,120.9
  other v1: 68.199,24 90.149,38.5 19.7,61.7 20.5,61.7 19.7,62.4 20.5,62.4 19.7,63.1 20.5,63.1 67.2,105.1 103.5,119.6 103.2,120.075 103.8,120.075
  other v2: 130.8,27.7 130.7,28.9
VDD_3V3_3U: C153.1 C154.2 C155.1 C156.2 C157.2 C158.2 C159.2 C160.2 C170.2 C172.2 C173.2 C175.2 D8.2 J18.16 J19.1 R232.1 R237.1 R239.1 R241.1 R245.1 R246.1 R249.1 U27.A8 U27.B3 U27.C10 U27.E6 U27.F3 U27.F5 U27.J3 U27.K2 U27.K4 U28.1 U28.2 U29.7 VDD_3V3_3U.1 Y10.4 | length 68.2
  L1 - Top Layer w0.25: R237.1@12.95,92.55 12.95,93 13.09,93.14 D8.2@14.45,93.14 14.45,93.925 14.625,94.1 v1(15.05,94.1)
  L1 - Top Layer w0.3: J18.16@3.655,96.7 v1(6.7,96.7) ; Y10.4@12,82.075 12.025,82.05 v1(12.025,81.225) ; v3(17.875,86) U27.A8@18.275,86.4 ; v3@18.701,82.026 U27.B3@19.075,82.4 ; U27.C10@19.875,88 v1(19.875,88.604) ; R239.1@19.975,91.75 v1(19.975,92.475) v1(20.575,92.475) 21.05,92.475 20.975,92.4 R245.1@20.975,91.75 ; v3(21.075,85.2) U27.E6@21.475,84.8 ; U27.F5@22.275,84 v3(22.675,83.6) ; v3@24.275,82 U27.J3@24.675,82.4 ; U27.K2@25.475,81.6 25.575,81.6 v3(25.975,81.2) ; U27.K4@25.475,83.2 v3(25.875,83.6) ; R241.1@25.875,90.95 v1(25.875,91.6) ; v1(39.675,119.15) 43.725,119.15 45.1,117.775 46.75,117.775 J19.1@48.625,119.65
  L1 - Top Layer w0.4: v1(20.55,74.65) 20.55,73.675 20.975,73.25 R249.1@21.475,73.25 R246.1@22.575,73.25 ; v3(21.875,82.8) U27.F3@22.275,82.4
  L1 - Top Layer w0.6: 9.5,66.4 10.1,66.4 10.4,66.7 C172.2@10.4,68.4
  L4 - Bottom Layer w0.3: v1(12.025,81.225) 12.6,81.225 12.675,81.3 C170.2@13.125,81.3 ; U29.7@16.925,102.375 C175.2@18.175,102.375 ; C158.2@17.225,86 v3(17.875,86) ; C156.2@17.825,82 v3(18.684,82) ; C157.2@22.55,82.7 22.675,82.825 v3(22.675,83.6) ; C154.2@24.225,82.8 24.275,82.75 v3(24.275,82) ; v3(25.875,83.6) 25.875,84.25 C155.1@25.925,84.3 ; v3(25.975,81.2) C153.1@25.975,81.9 ; J19.1@48.625,119.65 48.625,119.345 R232.1@49.775,118.195
  L4 - Bottom Layer w0.4: C159.2@19.85,89.3 19.875,89.275 v1(19.875,88.604) v1@19.879,88.6 ; C160.2@20.325,85.5 20.775,85.5 v3(21.075,85.2) ; v3(21.875,82.8) 22.45,82.8 C157.2@22.55,82.7 ; v1(25.8,106.325) 25.8,109.475 26.7,110.375 26.7,115.625 30.225,119.15 v1(39.675,119.15)
  L4 - Bottom Layer w0.5: v1(18.425,101.475) C175.2@18.425,102.325
  other v1: 11,69 11,69.7 11.7,69.7 21.2,92.45
VDD_3V3_LDO: C5.2 C6.2 C13.2 C14.2 C15.2 C16.2 C21.1 R10.1 R12.2 R13.2 U2.10 U3.8 U4.2 U4.15 | length 40.9
  L1 - Top Layer w0.35: U4.2@25.425,68.25 v1(25.425,69.025) ; U4.15@27.1,66.575 v1(28,66.575)
  L1 - Top Layer w0.5: v1(25.425,69.025) 25.425,69.825 25.9,70.3 R12.2@26.1,70.3 R13.2@27.9,70.3 ; C5.2@25.75,39.5 C6.2@25.75,40.7 v1(26.5,40.7) 27,40.7
  L4 - Bottom Layer w0.5: C21.1@23.45,55.6 C21.1@23.6,55.75 ; v1(24.25,52.725) 24.9,52.725 24.975,52.725 24.975,52.1 25.5,51.575 25.5,41.7 v1(26.5,40.7) ; v1(24.5,60.9) 27.325,63.725 C16.2@27.325,65.525 C15.2@27.325,66.5 C15.2@27.375,66.55 ; C13.2@24.9,68.5 v1(25.425,69.025) 25.425,68.975 C14.2@25.9,68.5 26.375,68.5 27.375,67.5 C15.2@27.375,66.55 ; v1(28,66.575) 27.4,66.575 C15.2@27.375,66.55
  L4 - Bottom Layer w2: 24.1,60.3 24.1,59 24.1,53.525 24.9,52.725
  other v1: 23.45,53.35 24.25,53.35 23.7,59 24.5,59 24.5,59.7 24.5,60.3
VDD_3V3_MPU: C39.2 C40.2 C41.1 C42.1 C43.1 C44.1 C45.1 C46.1 R9.2 R25.2 R30.1 U5.C4 U5.C7 U5.G3 U5.K3 U5.K14 U5.N3 VDD_3V3.1 | length 48.9
  L1 - Top Layer w0.15: U5.K3@76.075,73.975 U5.K3@76.082,73.975
  L1 - Top Layer w0.3: v4(68.6,74.3) U5.K14@68.925,73.975 ; U5.C7@73.475,69.425 v4(73.8,69.1) ; U5.C4@75.425,69.425 v4(75.75,69.1) ; v4(75.75,71.7) U5.G3@76.075,72.025 ; U5.N3@76.076,75.925 v4@76.394,76.243 ; U5.K3@76.082,73.975 v4@76.394,74.287
  L1 - Top Layer w1: 20.8,68.275 20.8,69.325 29.125,77.65 v3@56.525,77.65
  L4 - Bottom Layer w0.15: v4@76.381,74.3 v4@76.394,74.287
  L4 - Bottom Layer w0.25: v4(73.8,69.1) C41.1@73.8,69.488 ; v4(75.75,69.1) 75.762,69.1 C46.1@76.15,68.712 76.537,68.712 C40.2@77,68.25
  L4 - Bottom Layer w0.3: v4(68.6,74.3) C42.1@68.95,74.3
  L4 - Bottom Layer w0.35: C44.1@75.362,71.3 75.362,71.312 v4(75.75,71.7) ; R25.2@75.5,69.463 75.75,69.212 v4(75.75,69.1) ; C43.1@76.037,74.3 v4@76.381,74.3 ; v4(76.4,76.25) 76.4,76.262 C45.1@76.838,76.7 76.838,77.088 C39.2@77.25,77.5
  L4 - Bottom Layer w0.5: R30.1@66.025,77.225 v3@66.025,77.825
  other v3: 56.3,77.425 55.875,77.65 56.725,77.65 56.3,77.875 66.025,77.875
  other v4: 76.4,74.3
VDD_3V3_WILC: C127.2 FB9.1 U22.7 U22.8 | length 2.6
  L1 - Top Layer w1: FB9.1@120.3,25.2 120.3,25.7 ; U22.8@120.3,26.35 120.3,25.7 ; C127.2@121.8,25.7 120.3,25.7
VDD_AUDIO: C137.2 C138.2 C139.2 C140.2 D5.2 D6.2 J11.2 Q6.2 Q8.2 R176.2 R180.2 | length 44.2
  L1 - Top Layer w0.22: Q6.2@128.325,101.588 130.012,101.588 C138.2@130.2,101.4 ; R176.2@129.25,98 129.25,98.335 v1(129.715,98.8) D5.2@130.515,99.6 130.2,99.915 v1(130.2,100.5) ; Q8.2@136.225,101.587 137.912,101.588 C137.2@138.1,101.4 ; R180.2@137.15,98 137.15,98.335 v1(137.615,98.8) D6.2@138.415,99.6 138.1,99.915 v1(138.1,100.5)
  L1 - Top Layer w0.35: v1(130.2,100.5) C138.2@130.2,101.4 ; v1(138.1,100.5) C137.2@138.1,101.4
  L4 - Bottom Layer w1: J11.2@128.2,119.9 128.2,116.275 C139.2@128.175,116.25 C140.2@128.175,113.95 128.175,104.438 130,102.612 ; 130,98.8 130,102.612 ; 137.9,98.9 137.9,100.4 135.688,102.612 130,102.612
VDD_MAIN_5V: C10.1 C96.1 C100.1 C117.1 C118.1 C123.1 C124.1 C126.1 J11.3 J14.10 J16.2 J16.4 R1.2 R15.2 R16.2 R29.2 R214.2 U3.6 U3.7 U12.3 U13.3 U19.7 U20.7 U22.1 U22.2 VDD_MAIN_5V.1 | length 316.8
  L1 - Top Layer w0.3: R15.2@8.75,49.4 10.55,47.6 R16.2@12.65,47.6 ; R29.2@20.6,47.6 20.6,46.9 20.65,46.85 ; U12.3@108.125,105.15 108.125,104.025 C96.1@108.25,103.9 108.25,103.15 v2(108.238,103.138) ; U13.3@119.525,105.15 119.525,104.025 C100.1@119.65,103.9 119.65,103.125 v2(119.638,103.113)
  L1 - Top Layer w0.5: R16.2@12.65,47.6 12.65,47.35 12.6,47.3 13.1,46.8 20.6,46.8 21.2,46.2 23,46.2 v1(24.4,47.6) ; 38.435,36.235 38.6,36.4 ; U20.7@47.535,33.7 47.535,36.135 47.8,36.4 ; 56.4,36.4 56.635,36.165 U19.7@56.635,33.7
  L1 - Top Layer w2: v1@23.9,48.2 v1(23.9,48.1) v1(24.4,47.6) 26.4,45.6 VDD_MAIN_5V.1@26.6,45.6 27.9,45.6 32.7,40.8 32.7,36.4
  L1 - Top Layer w3: 31,35.1 32.3,36.4 ; 32.7,36.4 38.6,36.4 41.2,36.4 C123.1@42.9,36.4 47.8,36.4 56.4,36.4 78.4,36.4 81.6,33.2 v2(138.8,33.2)
  L4 - Bottom Layer w0.5: 108.238,101.6 v2(108.238,103.138) ; 119.638,101.575 v2(119.638,103.113)
  L4 - Bottom Layer w0.6: R214.2@101.675,98.6 103,98.6
  L4 - Bottom Layer w1: J14.10@22.55,25.63 v1(30.9,33.98) v1(30.9,34.8) ; 103,98.6 104.275,98.6 107.275,101.6 108.238,101.6 125.325,101.6
  L4 - Bottom Layer w1.5: 126.625,122.675 130.775,122.675 135.05,118.4 146.7,118.4 148.37,116.73 J16.2@148.37,116.03 J16.4@148.37,113.49
  L4 - Bottom Layer w2: v1(22.1,51.85) v1(22.6,51.35) 22.957,50.993 23.07,50.993 23.875,50.188 23.875,50.075 23.9,50.05 v1(23.9,48.1)
  L4 - Bottom Layer w3: 125.325,117.6 125.325,101.6 125.325,72.375 138.8,58.9 v2(138.8,33.2)
  other v1: 138.1,32.5 139.5,32.5 138,34 139.5,34 23.4,47.6 23.4,48.6 24.4,48.6 21.6,51.35 21.6,52.35 22.6,52.35
VDD_MAIN_5V_: C4.1 Q1.4 Q2.4 R1.1 | length 13.5
  L1 - Top Layer w1.2: 24.1,34.6 24.1,33.5 31.6,26 C4.1@33.4,26
VDDBU: C50.1 J2.1 R22.1 R194.2 U5.P7 | length 51.3
  L1 - Top Layer w0.3: U5.P7@73.475,76.575 v4(73.8,76.9)
  L1 - Top Layer w0.4: J2.1@61.825,119.63 61.825,108.175 66.2,103.8 67.8,103.8 72.7,98.9 72.7,88.463 74.713,86.45 v1(75.425,86.45)
  L4 - Bottom Layer w0.25: C50.1@73.8,76.487 v4(73.8,76.9) v4@73.825,76.925 ; v4@73.85,76.9 73.85,79.35 73.9,79.4
  L4 - Bottom Layer w0.35: 73.9,79.4 73.9,79.45 75.425,80.975
  L4 - Bottom Layer w0.4: 75.425,80.975 v1(75.425,86.45)
VDDCORE: C31.2 C32.1 C33.1 C34.1 R8.2 U5.F6 U5.F11 U5.L6 VDDCORE.1 | length 52.9
  L1 - Top Layer w0.35: U5.F11@70.875,71.375 v4(71.2,71.7) ; v4(73.8,71.7) U5.F6@74.125,71.375 ; v4(73.8,74.3) U5.L6@74.125,74.625
  L1 - Top Layer w1: 29.375,68.775 29.375,70.7 33.45,74.775 v3(56.1,74.775) v3(56.95,74.775)
  L3 - PWR w0.35: v4(71.2,71.7) 72.075,72.575 ; 72.89,73.425 72.925,73.425 v4(73.8,74.3) ; 72.925,72.575 v4(73.8,71.7)
  L3 - PWR w0.75: 67.425,73.525 67.95,73 69.25,73
  L3 - PWR w1: v3(56.95,74.775) 66.175,74.775 67.425,73.525
  L4 - Bottom Layer w0.3: v4(71.2,71.7) C32.1@71.569,72.105 ; C32.1@71.6,72.138 C33.1@73.4,72.138 73.4,72.1 v4(73.8,71.7)
  L4 - Bottom Layer w0.35: C34.1@73.3,73.962 73.462,73.962 v4(73.8,74.3)
  other v3: 56.525,74.55 56.525,75
VDDIN33: C47.2 C48.1 C49.1 R30.2 U5.L11 U5.P13 | length 7.7
  L1 - Top Layer w0.3: v4(69.25,76.9) U5.P13@69.575,76.575 ; U5.L11@70.875,74.625 v4(71.2,74.3)
  L4 - Bottom Layer w0.35: C47.2@68,77.218 68.282,77.218 69.25,76.25 ; v4(69.25,76.9) 69.25,76.25 ; C48.1@71.725,73.987 71.513,73.987 69.25,76.25
  L4 - Bottom Layer w0.5: R30.2@66.925,77.225 67.993,77.225 C47.2@68,77.218
VDDIOM: C35.2 C36.1 C37.1 C38.1 C63.2 C65.2 C67.2 C68.2 C69.1 C70.1 C71.2 C72.2 C73.2 C74.2 C75.1 C76.1 C77.1 C78.2 C79.2 C80.2 C81.2 C82.2 R7.2 R120.2 U5.C10 U5.C13 U5.G14 U10.A1 U10.A9 U10.C1 U10.C3 U10.C7 U10.C9 U10.E1 U10.E9 U10.G1 U10.G3 U10.G7 U10.G9 U10.J1 U10.J9 U10.M9 U10.R1 VDDIOM.1 | length 65.5
  L1 - Top Layer w0.3: v3(56.775,52.4) U10.G9@57.175,52.8 ; v3(59.975,52.4) U10.C9@60.375,52.8 ; v3(61.575,52.4) U10.A9@61.975,52.8 ; v4(68.6,71.7) U5.G14@68.925,72.025 ; v4(69.23,69.08) U5.C13@69.575,69.425 ; v4(71.2,69.1) U5.C10@71.525,69.425
  L1 - Top Layer w0.35: v3(60.15,57.075) U10.C3@60.375,57.6
  L1 - Top Layer w0.4: U10.R1@50.775,59.2 v3(50.775,59.75) ; v3@53.175,52.251 U10.M9@53.175,52.8 ; v3@54.8,60.95 C75.1@55.575,60.95 ; U10.J9@55.575,52.8 v3(55.975,52.4) ; U10.J1@55.575,59.2 C75.1@55.575,60.9 ; v3@56.4,60.95 C70.1@57.175,60.95 ; U10.G7@57.175,54.4 v3(57.175,55.625) ; U10.G1@57.175,59.2 C70.1@57.175,60.9 ; v3(57.175,56.375) U10.G3@57.175,57.6 ; v3(57.975,60.95) C76.1@58.75,60.95 58.75,60.925 58.775,60.9 U10.E1@58.775,59.2 ; U10.E9@58.775,52.8 v3(59.175,52.4) ; v3(59.575,60.95) C69.1@60.375,60.95 U10.C1@60.375,59.2 ; v3@59.975,54.8 U10.C7@60.375,54.4 ; v3(61.125,60.775) 61.3,60.95 C77.1@61.975,60.95 ; U10.A1@61.975,59.2 C77.1@61.975,60.9
  L1 - Top Layer w1.1: 31.1,60.3 VDDIOM.1@32.275,61.475 43.675,61.475 55.025,72.825 58.85,72.825
  L4 - Bottom Layer w0.1: C63.2@60.6,60.612 C63.2@60.65,60.563 ; v4@69.213,69.1 v4@69.25,69.1
  L4 - Bottom Layer w0.3: v3(50.775,59.75) C73.2@51.3,59.75 ; C68.2@52.8,52.85 53.175,52.475 v3(53.175,52.25) ; v3(56.775,52.4) 57.037,52.662 C74.2@57.037,52.8 ; C78.2@59.713,57.075 v3(60.15,57.075) ; v3(59.975,52.4) 60.237,52.662 C72.2@60.237,52.8 ; R120.2@60.05,60.562 C63.2@60.65,60.563 ; v3(61.575,52.4) 61.837,52.662 C80.2@61.837,52.8 ; v4(68.6,71.7) C36.1@68.988,71.7 ; C38.1@68.8,68.688 68.838,68.688 v4(69.23,69.08) v4@69.25,69.1 ; v4(71.2,69.1) C37.1@71.2,69.488
  L4 - Bottom Layer w0.4: C82.2@55.6,51.7 55.975,52.075 v3(55.975,52.4) ; C71.2@56.7,55.625 v3(57.175,55.625) ; C79.2@56.7,56.375 v3(57.175,56.375) ; C81.2@58.625,52.4 v3(59.175,52.4) ; v3(59.575,60.95) 60,61.375 C65.2@60.6,61.375 C63.2@60.6,60.612 ; v3(59.975,54.8) 59.975,55.35 C67.2@60.025,55.4
  L4 - Bottom Layer w0.5: v3(64.2,65.8) 64.45,66.05 C35.2@64.8,66.05
  other v1: 58.6,72.525 58.1,72.825 59.1,72.825 58.6,73.125
  other v3: 54.775,60.95 56.35,60.95
VDDout: C161.2 C162.2 C163.1 C164.1 C165.1 C166.1 C167.1 C168.1 C169.2 U27.A9 U27.B1 U27.D3 U27.D4 U27.E7 U27.F9 U27.G5 U27.H1 | length 24.4
  L1 - Top Layer w0.3: v3(17.875,87.6) U27.A9@18.275,87.2 ; U27.D4@20.675,83.2 v3(21.075,83.6) ; v3(21.875,87.6) U27.F9@22.275,87.2 ; v3(22.675,84.4) U27.G5@23.075,84
  L1 - Top Layer w0.4: U27.B1@19.075,80.8 v3(19.475,81.2) ; U27.D3@20.675,82.4 v3(21.075,82.8) ; U27.E7@21.475,85.6 v3(21.875,86) ; v3(23.475,81.2) U27.H1@23.875,80.8
  L4 - Bottom Layer w0.3: v3(17.875,87.6) 18.85,87.6 C169.2@18.9,87.65 20.6,87.65 C161.2@20.9,87.35
  L4 - Bottom Layer w0.4: C163.1@19.05,80.4 19.05,80.775 v3(19.475,81.2) 20.45,82.175 C165.1@20.45,82.6 ; C161.2@20.9,87.35 21.15,87.6 v3(21.875,87.6) v3(21.875,86) ; 21.3,83.6 21.075,83.375 v3(21.075,82.8) 20.875,82.6 C165.1@20.45,82.6 ; 21.875,84.175 22.1,84.4 v3(22.675,84.4) 23.425,83.65 C166.1@23.5,83.65 ; C168.1@22.425,81.575 C168.1@22.413,81.587 ; C162.2@24.25,81.2 v3(23.475,81.2) 23.088,81.587 C168.1@22.413,81.587 ; C165.1@20.45,82.6 20.925,82.125 21.875,82.125 C168.1@22.413,81.587
  L4 - Bottom Layer w0.5: C164.1@20.45,83.6 v3(21.075,83.6) ; 21.3,83.6 21.875,84.175 v3(21.875,86)
VDDOUT25: C51.1 C52.1 U5.P10 | length 2.7
  L1 - Top Layer w0.3: v4(71.2,76.9) U5.P10@71.525,76.575
  L4 - Bottom Layer w0.35: 71.199,78.449 C52.1@71.199,78.777 ; C51.1@71.2,76.512 v4(71.2,76.9) 71.2,78.45
WAKE_UP: R197.1 U5.T11 | length 32.5
  L1 - Top Layer w0.125: R197.1@69.75,98 65.9,98 60.7,92.8 60.7,86.2 65.3,81.6 68.975,81.6 70.875,79.7 U5.T11@70.875,77.875
WILC3000_ENABLE: R162.1 U22.5 U24.19 | length 17.9
  L1 - Top Layer w0.125: U22.5@118.95,26.5 118.95,26.35 118.4,25.8 118.4,20.8 119.1,20.1 R162.1@119.1,18.7 120.3,17.5 124.3,17.5 125.77,18.97 U24.19@127.62,18.97
WILC3000_ENABLE_PA29: U5.H3 U21.1 U21.7 U22.3 U23.1 U23.7 | length 103.1
  L1 - Top Layer w0.125: U5.H3@76.075,72.675 v4(76.4,72.35) ; U23.1@87.386,41.9 88.7,41.9 v3(88.9,41.7) 89.2,41.4 U23.7@90.036,41.4 ; U21.1@87.475,38.019 88.381,38.019 v3(88.7,37.7) 88.881,37.519 U21.7@90.125,37.519 92.4,37.519 94.619,35.3 v1(114.1,35.3) ; v1(118.8,30.6) 119.45,29.95 U22.3@119.45,29.5
  L4 - Bottom Layer w0.125: v4(76.4,72.35) 82.55,72.35 85.5,69.4 85.5,62.9 85.3,62.7 85.3,45.3 v3(88.9,41.7) 88.9,37.9 v3(88.7,37.7) ; v1(114.1,35.3) 108.05,41.35 108.05,41.95 108.55,42.45 109.25,42.45 115.9,35.8 117,35.8 118.8,34 v1(118.8,30.6)
WILC3000_INTERRUPT_PA28: R168.1 U5.F1 U24.33 | length 117.7
  L1 - Top Layer w0.125: U5.F1@77.375,71.375 81.325,71.375 83.8,68.9 85.9,68.9 90.8,64 v2(109.7,64) ; v2(125.51,9.7) 125.51,6.69 126.1,6.1 137.5,6.1 138.2,6.8 138.2,8.9 139.2,9.9 U24.33@139.2,11.63
  L4 - Bottom Layer w0.125: v2(109.7,64) 109.7,57.5 120.5,46.7 120.5,31.4 123.5,28.4 123.5,12.55 R168.1@125.5,10.55 125.5,9.71 v2(125.51,9.7)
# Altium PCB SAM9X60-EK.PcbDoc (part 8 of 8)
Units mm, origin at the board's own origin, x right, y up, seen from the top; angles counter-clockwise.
Board outline 150 x 125 mm, 4 copper layers (L1 - Top Layer, L2 - GND, L3 - PWR, L4 - Bottom Layer), stack 1.52 mm thick; 566 components, 500 nets, 2132 pads, 1038 vias.

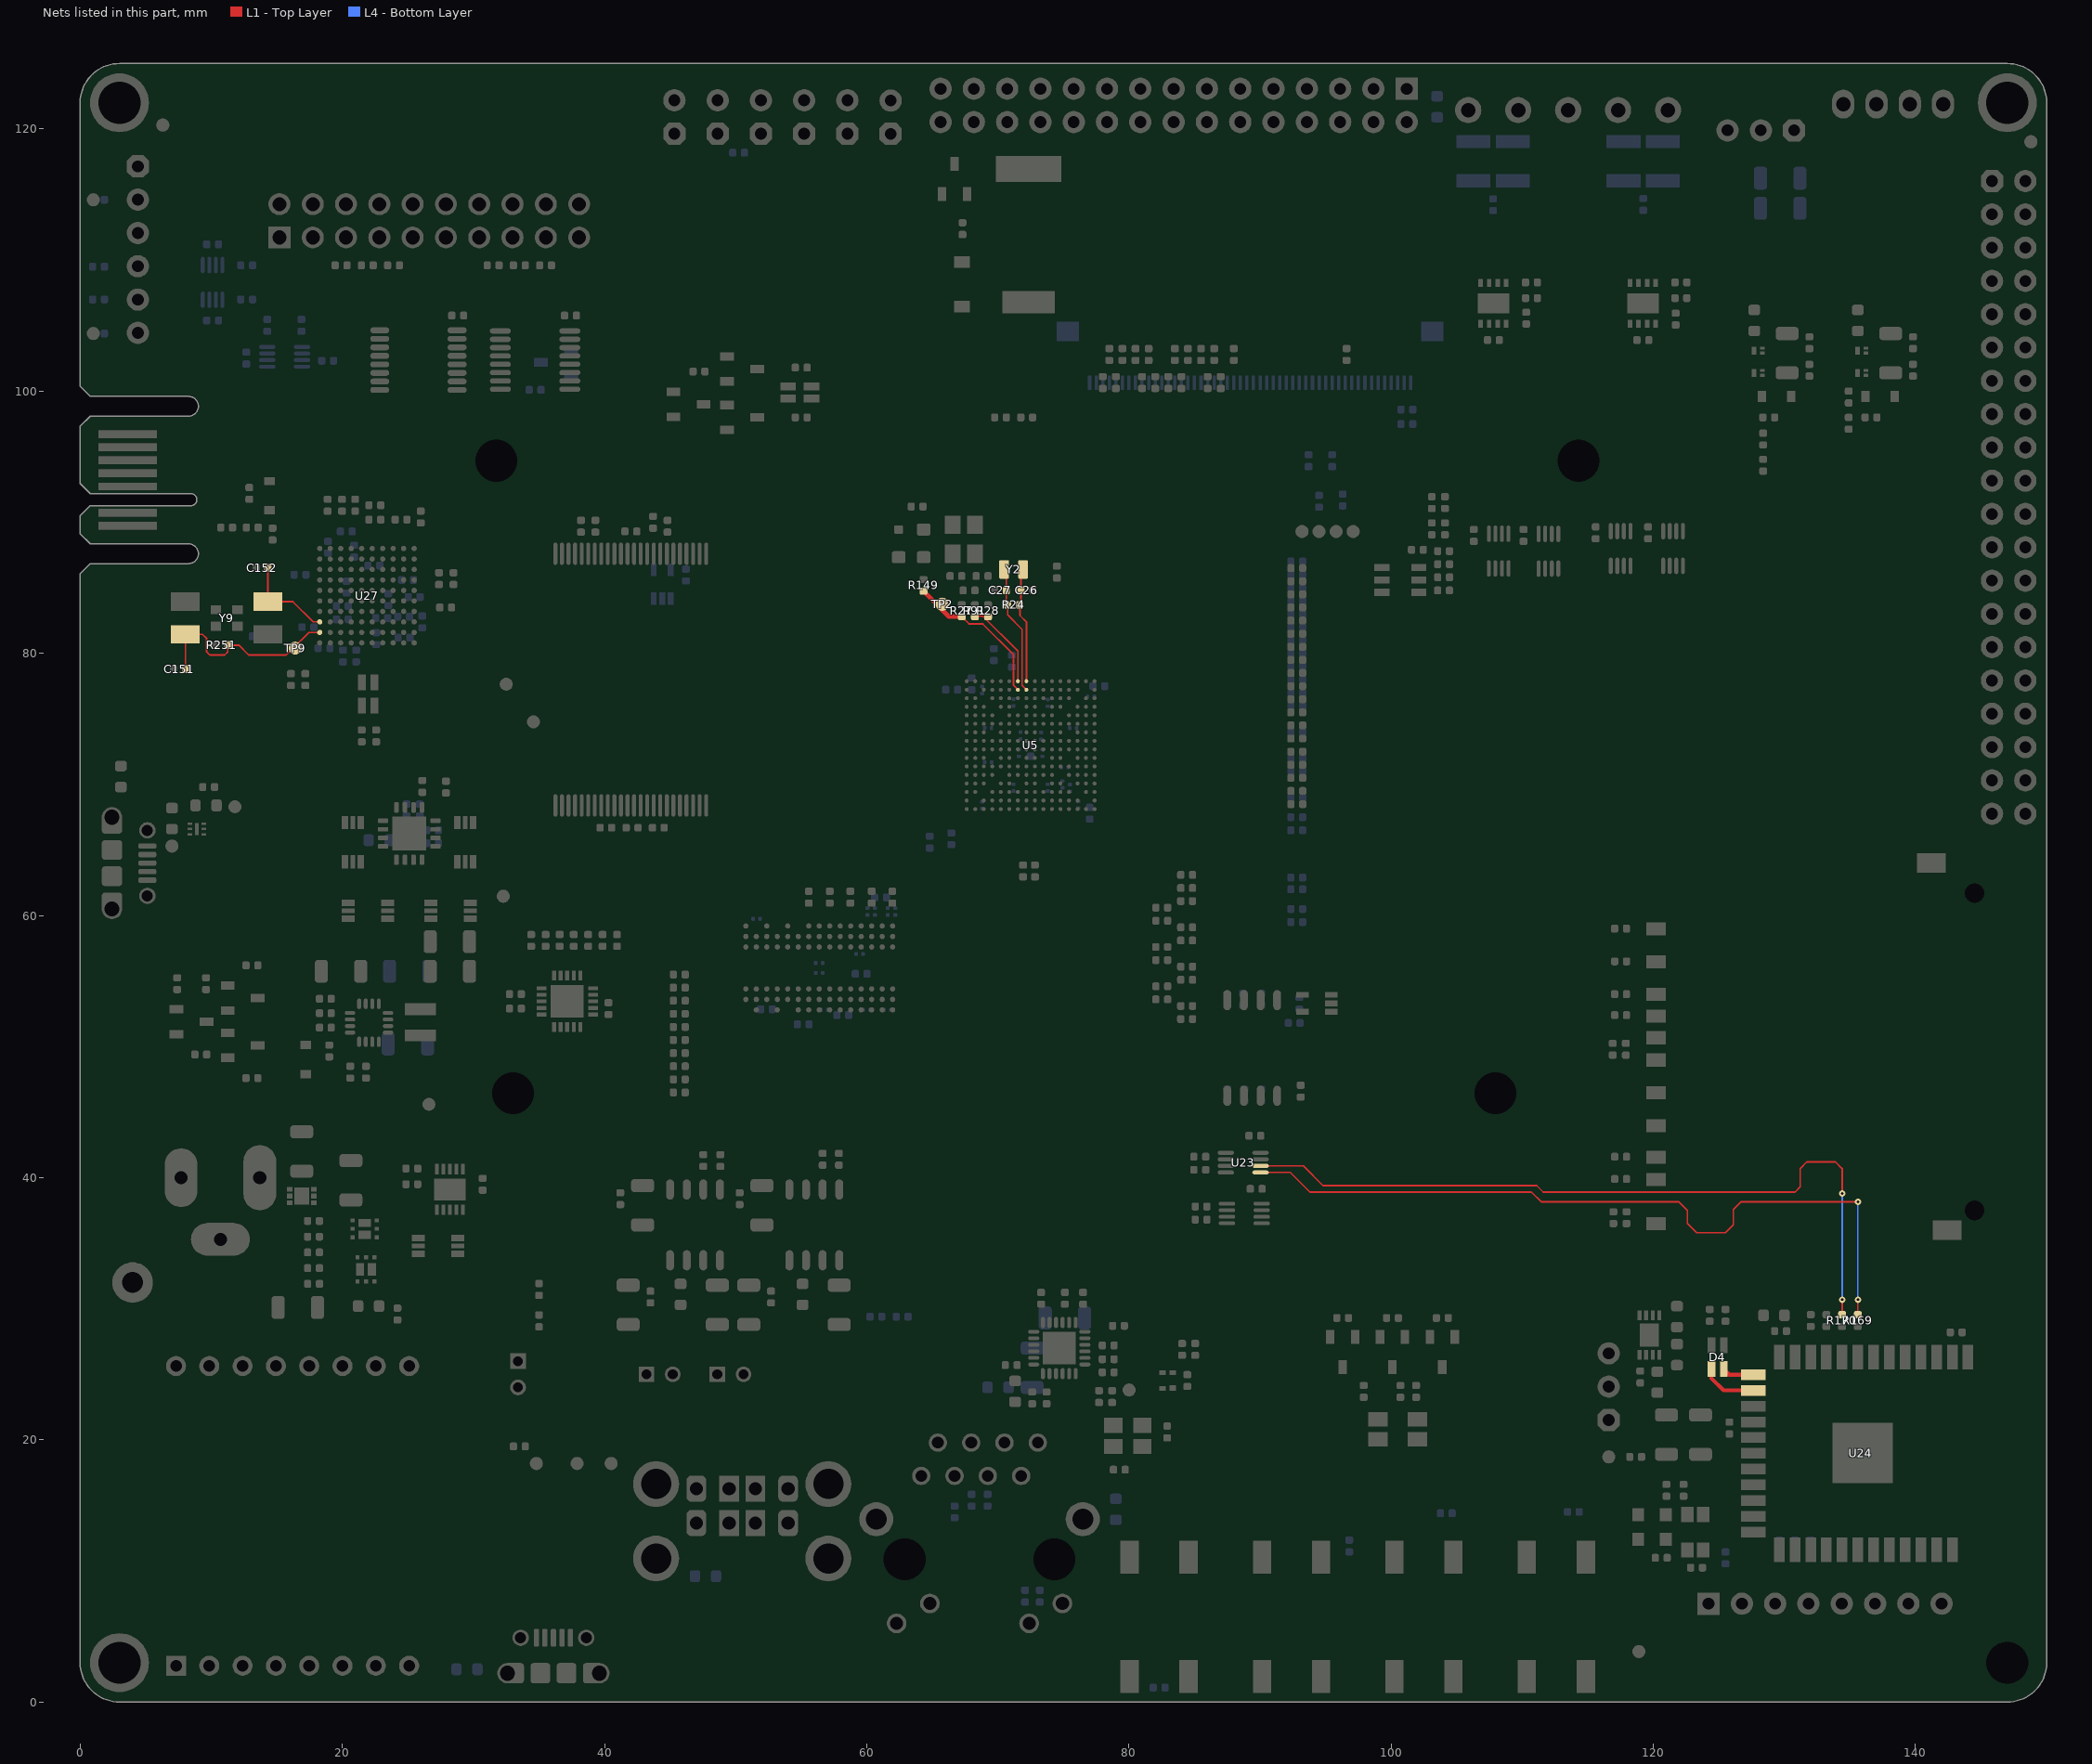
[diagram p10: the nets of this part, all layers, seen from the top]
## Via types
v1: diameter 0.5, hole 0.2, L1 - Top Layer to L4 - Bottom Layer, tented both sides, 483 vias
v2: diameter 0.5, hole 0.2, L1 - Top Layer to L4 - Bottom Layer, 268 vias
v3: diameter 0.4, hole 0.2, L1 - Top Layer to L4 - Bottom Layer, tented both sides, 145 vias
v4: diameter 0.35, hole 0.15, L1 - Top Layer to L4 - Bottom Layer, tented both sides, 121 vias
v5: diameter 0.55, hole 0.3, L1 - Top Layer to L4 - Bottom Layer, tented bottom, 16 vias
v6: diameter 0.559, hole 0.305, L1 - Top Layer to L4 - Bottom Layer, 5 vias

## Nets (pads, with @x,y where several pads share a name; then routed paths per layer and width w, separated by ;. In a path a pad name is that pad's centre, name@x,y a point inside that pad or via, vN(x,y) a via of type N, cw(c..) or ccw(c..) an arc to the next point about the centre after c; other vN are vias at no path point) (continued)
WILC_BT_RX: R170.2 U23.6 | length 58.3
  L1 - Top Layer w0.125: U23.6@90.036,40.9 93.3,40.9 94.8,39.4 111.1,39.4 111.6,38.9 130.8,38.9 131.2,39.3 131.2,40.7 131.7,41.2 133.9,41.2 134.4,40.7 v2(134.4,38.8) ; R170.2@134.4,29.55 134.4,30.4 v2(134.4,30.7)
  L4 - Bottom Layer w0.125: v2(134.4,30.7) v2(134.4,38.8)
WILC_BT_TX: R169.2 U23.5 | length 58.3
  L1 - Top Layer w0.125: U23.5@90.036,40.4 92.3,40.4 93.8,38.9 110.7,38.9 111.436,38.164 121.936,38.164 122.6,37.5 122.6,36.5 123.3,35.8 125.5,35.8 126.1,36.4 126.1,37.564 126.7,38.164 v2(135.6,38.164) ; R169.2@135.6,29.55 135.6,30.4 v2(135.6,30.7)
  L4 - Bottom Layer w0.125: v2(135.6,30.7) v2(135.6,38.164)
WILC_LED_GREEN: D4.3 U24.14 | length 2.4
  L1 - Top Layer w0.3: D4.3@125.375,25.4 125.805,24.97 U24.14@127.62,24.97
WILC_LED_RED: D4.2 U24.15 | length 4.3
  L1 - Top Layer w0.3: D4.2@124.425,25.4 124.425,24.7 125.355,23.77 U24.15@127.62,23.77
XIN: R27.1 R149.1 TP2.1 U5.R10 | length 11.7
  L1 - Top Layer w0.125: R27.1@67.25,82.8 67.8,82.25 68.85,82.25 71.2,79.9 71.2,77.55 U5.R10@71.525,77.225
  L1 - Top Layer w0.35: R149.1@64.337,84.738 66.275,82.8 R27.1@67.25,82.8
XIN32: C26.1 R24.2 U5.T9 Y2.2 | length 8.9
  L1 - Top Layer w0.125: R24.2@71.65,83.7 R24.2@71.688,83.738 ; Y2.2@71.925,86.4 71.75,86.225 C26.1@71.75,84.8 71.75,83.8 R24.2@71.688,83.738 ; U5.T9@72.175,77.875 72.175,82.4 71.688,82.888 R24.2@71.688,83.738
Xin_SAM3: C151.1 R251.2 TP9.1 U27.A2 Y9.1 | length 15.9
  L1 - Top Layer w0.125: C151.1@8.025,78.8 Y9.1@8.025,81.45 9.325,81.45 9.65,81.125 9.65,80.1 9.875,79.875 11.025,79.875 11.25,80.1 R251.2@11.25,80.625 12.1,80.625 12.85,79.875 15.725,79.875 TP9.1@16.25,80.4 ; TP9.1@16.195,80.35 17.445,81.6 U27.A2@18.275,81.6
XOUT: R28.1 R91.1 U5.T10 | length 6.6
  L1 - Top Layer w0.125: R91.1@68.3,82.85 68.85,82.85 71.525,80.175 U5.T10@71.525,77.875
XOUT32: C27.1 R24.1 U5.R9 Y2.1 | length 9.9
  L1 - Top Layer w0.125: Y2.1@70.475,86.4 70.65,86.225 C27.1@70.65,84.8 70.65,83.8 R24.1@70.75,83.7 70.75,82.925 71.85,81.825 71.85,77.55 U5.R9@72.175,77.225
Xout_SAM3: C152.1 U27.A3 Y9.3 | length 7.1
  L1 - Top Layer w0.125: C152.1@14.325,86.5 Y9.3@14.325,83.95 16.226,83.95 17.776,82.4 U27.A3@18.275,82.4
pads on no net: J1.3 J4.1.5mm J5.7 J5.9 J5.10 J5.MH1 J5.MH2 J7.4 J16.27 J16.28 J18.1 J18.7 J18.9 J18.11 J18.13 J18.15 J22.4 J23.3 J23.17 J23.19 LCD1.1 U1.3 U2.3 U2.4 U5.A10 U5.A11 U5.B10 U5.E8 U5.F12 U5.F15 U5.G16 U5.H14 U5.L14 U6.5 U6.6 U6.8 U6.11 U9.1 U9.2 U9.3 U9.4 U9.5 U9.6 U9.10 U9.11 U9.14 U9.15 U9.20 U9.21 U9.22 U9.23 U9.24 U9.26 U9.27 U9.28 U9.33 U9.35 U9.38 U9.40 U9.45 U9.46 U9.47 U10.A2 U10.E2 U10.R3 U10.R7 U19.4 U19.5 U20.4 U20.5 U24.3 U24.4 U24.5 U24.6 U24.34 U24.35 U27.A4 U27.A5 U27.A6 U27.A10 U27.B4 U27.B5 U27.B6 U27.B10 U27.C4 U27.C5 U27.C6 U27.D5 U27.D7 U27.E4 U27.E8 U27.E9 U27.E10 U27.F1 U27.F2 U27.F7 U27.F8 U27.F10 U27.G1 U27.G2 U27.G3 U27.G4 U27.G7 U27.G9 U27.H2 U27.H3 U27.H10 U27.J1 U27.J2 U27.J4 U27.J5 U27.J6 U27.J7 U27.K5 U27.K6 U28.5 U32.1 U32.9 Y3.1 Y8.3 Y10.1

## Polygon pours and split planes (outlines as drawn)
EARTH_JLINK on L1 - Top Layer "full" (solid, remove dead copper, pour order 1622): 0,60 5.326,60 5.326,67.999 3.525,69.8 0,69.8
EARTH_USB_A on L1 - Top Layer "full" (solid, remove dead copper, pour order 1616): 30.9,0 30.9,6.3 41.3,6.3 41.3,0
EARTH_USB_B on L1 - Top Layer "full" (solid, remove dead copper, pour order 1614): 42.6,0 42.6,15.2 58.4,15.2 58.4,0
VDD_3V3_MPU on L3 - PWR "full" (solid, remove dead copper, pour order 1612): 73.5,68.4 73.5,73.4 67.6,73.4 66.525,74.475 58.325,74.475 55.525,77.275 55.525,78.025 55.752,78.252 66.819,78.252 77.8,78.252 77.8,68.4
VDD_3V3 on L3 - PWR "full" (solid, remove dead copper, pour order 1626): 0,0 150,0 150,125 0,125
VDD_3V3_3U on L3 - PWR "full" (solid, remove dead copper, pour order 1624): 0,59.225 5.825,59.225 28.875,82.275 28.875,96.525 31.125,98.775 31.125,106.9 15.625,106.9 6.825,98.1 0.775,98.1 0,97.325
VDDIOM on L3 - PWR "full" (solid, remove dead copper, pour order 1608): 73.4,71.835 73.4,51.186 73.012,50.8 49.964,50.8 49.6,51.164 49.6,64.775 58.9,74.075 71.16,74.075
VDDCORE on L3 - PWR "full" (solid, remove dead copper, pour order 1606): 68.35,73.375 68.35,72.625 70.925,72.625 71.575,71.975 73.525,71.975 73.525,74.025 71.975,74.025 71.325,73.375
GND on L2 - GND "full" (solid, remove dead copper, pour order 1628): 0,0 150,0 150,125 0,125
EARTH_ETH on L4 - Bottom Layer "full" (solid, remove dead copper, pour order 1618): 60.2,0 60.3,0.1 60.3,21.7 76.8,21.7 77.975,20.525 77.975,0

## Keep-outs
Keep-Out Layer:
  text ".Layer_Name" at 296.75,-86 h1.5

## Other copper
L1 - Top Layer:
  region net VDD_3V3_LDO: 24.55,52.425 24.55,53.65 23.15,53.65 23.15,52.425
  region net VDD_MAIN_5V: 21.631,52.15 21.631,51.45 23.8,51.45 23.8,52.15
  region net GND: 69.25,83.7 69.3,83.65 70,83.65 70,84.9 69.4,85.5 69.25,85.5
  region net VDD_3V3: 19.4,59.5 19.1,59.8 19.1,62.4 20.8,62.4 20.95,62.25 20.95,60.7 19.875,60.7 19.775,60.6 19.775,60.1 19.875,60 20.55,60 20.55,59.575 20.475,59.5
  region net VDD_3V3_MPU: 21.65,68.475 21.475,68.65 20.125,68.65 19.95,68.475 19.95,67.075 20.025,67 20.45,67 20.45,67.675 20.55,67.775 21.05,67.775 21.15,67.675 21.15,67 21.575,67 21.65,67.075
  region net VDD_3V3: 19.1,62.2 19.6,61.7 20.4,61.7 21.65,62.95 21.65,64.125 21.575,64.2 21.15,64.2 21.15,63.525 21.05,63.425 20.55,63.425 20.45,63.525 20.45,64.2 20.025,64.2 19.1,63.275
  region net VDD_3V3_LDO: 24.5,61.2 24.85,60.85 24.85,58.75 23.25,58.75 22.95,59.05 22.95,60 24.025,60 24.125,60.1 24.125,60.6 24.025,60.7 23.35,60.7 23.35,61.125 23.425,61.2
  region net VDD_1V8: 26.95,52.45 24.8,52.45 24.8,53.85 22.15,53.85 22.15,54.15 25.35,57.35 25.35,58.75 25.8,59.2 27,59.2 27.2,59 27.2,52.7
  region net VDDIOM: 31.525,59.5 31.75,59.725 31.75,60.925 31.475,61.2 29.725,61.2 29.65,61.125 29.65,60.7 30.325,60.7 30.425,60.6 30.425,60.1 30.325,60 29.65,60 29.65,59.575 29.725,59.5
  region net VDD_1V15: 28.525,63.2 29.175,62.55 29.65,62.55 30.225,63.125 30.225,64.125 30.15,64.2 29.725,64.2 29.725,63.525 29.625,63.425 29.125,63.425 29.025,63.525 29.025,64.2 28.6,64.2 28.525,64.125
  region net VDDCORE: 30.225,68.475 29.6,69.1 29.2,69.1 28.525,68.425 28.525,67.075 28.6,67 29.025,67 29.025,67.675 29.125,67.775 29.625,67.775 29.725,67.675 29.725,67 30.15,67 30.225,67.075
  region net GND: 29.75,55.8 29.7,55.85 29.7,58.05 30.65,58.05 30.65,55.8
  region net GND: 120.8,20.1 120.8,18.9 121,18.7 123.6,18.7 122.1,20.2 120.9,20.2
  region net GND: 119.7,107.4 121.8,107.4 121.95,107.25 121.95,105.9 119.7,105.9
  region net GND: 108.3,107.4 110.4,107.4 110.55,107.25 110.55,105.9 108.3,105.9
  region net GND: 9.4,67.1 9.4,69.9 9.2,70.1 7.4,68.3 7.4,67.9 8,67.9 8.8,67.1
  region net VDD_3V3_3U: 10.1,68.1 10.1,70.05 12,70.05 12,68.1
  region net VDD_MAIN_5V: 119.8,29.2 120.6,29.2 121.2,29.8 121.8,29.8 122.2,30.2 122.2,32.2 119.8,32.2
  region net NetL1_1: 25,50.4 23.7,50.4 23.1,51 23.3,51.2 24.325,51.2 24.425,51.3 25,51.3
  region net VDD_MAIN_5V: 21.5,52.6 21.3,52.4 21.3,51.3 21.5,51.1 22.7,51.1 22.9,51.3 22.9,52.4 22.7,52.6
  region net VDD_MAIN_5V_: 25.095,35.65 22.813,35.65 22.3,35.137 22.3,34.025 23.225,33.1 25.099,33.1
  region net VDD_MAIN_5V_: 24.395,33.95 24.22,34.125 24.22,35.475 24.395,35.65 25.795,35.65 25.87,35.575 25.87,35.15 25.195,35.15 25.12,35.075 25.12,34.525 25.195,34.45 25.87,34.45 25.87,34.025 25.795,33.95
  region net DC_5V: 17.7,38.7 17.7,37.2 18,36.9 18,35.25 18.5,35.25 19.05,34.7 19.7,34.7 19.7,35.9 20.9,37.1 20.9,37.8 20,38.7
  region net USB_5V: 21.5,29.9 18.3,29.9 18,30.2 18,33.3 18.1,33.4 19.837,33.4 21.5,31.737
  region: 21.5,29.9
  region net VDD_MAIN_5V: 30.205,33.95 30.38,34.125 30.38,35.475 30.205,35.65 28.805,35.65 28.73,35.575 28.73,35.15 29.405,35.15 29.48,35.075 29.48,34.525 29.405,34.45 28.73,34.45 28.73,34.025 28.805,33.95
  region net VDD_1V8: 25.7,61.2 25.35,60.85 25.35,58.75 26.95,58.75 27.25,59.05 27.25,60 26.175,60 26.075,60.1 26.075,60.6 26.175,60.7 26.85,60.7 26.85,61.125 26.775,61.2
  text "'.Layer_Name'" at 0,126 h1.5
  text "1" at 1.7,48.9 h1 r90
  text ".ProjectRevisionART" at 331.928,-85.822 h1.5
  text ".Layer_Name" at 296.75,-86 h1.5
L2 - GND:
  text "'.Layer_Name'" at 0,126 h1.5
  text "2" at 1.7,51.111 h1 r90
L3 - PWR:
  rectangle net VDDCORE: 55.9,74.275 57.15,75.275
  rectangle net VDD_1V15: 20.75,57.35 22.05,58.65
  rectangle net VDD_1V15: 28.65,62.55 30.15,63.5
  text "'.Layer_Name'" at 0,126 h1.5
  text "3" at 1.7,53.989 h1 r90
L4 - Bottom Layer:
  rectangle net VDD_MAIN_5V: 123.825,117.6 126.825,123.425
  rectangle net NetJ15_48: 100.375,99.375 101.125,99.9
  region net GND: 24.9,67.8 23.4,66.3 23.4,65.7 23.8,65.3 26.5,65.3 26.6,65.4 26.6,67.5 26.3,67.8
  region net GND: 72.062,73.8 73,73.8 73.4,73.4 73.4,72.75 73.25,72.6 73.1,72.75 71.9,72.75 71.75,72.6 71.5,72.6 71.5,73.238
  region net VDDIN33: 69.3,76.75 69.1,76.55 68.8,76.55 68.6,76.75 68.6,77.068 69.232,77.068 69.3,77
  region net GND: 76,25.7 73.4,25.7 73.4,28.3 76,28.3
  text "'.Layer_Name'" at 0,126 h1.5
  text ".ProjectName" at 20.8,122.4 h1.5
  text "Rev .ProjectRevisionART" at 20.8,119.9 h1.5
  text "4" at 1.7,56.2 h1 r90
  text ".ProjectRevisionART" at 217.95,-83.6 h1.2
  text "-R" at 220.45,-83.6 h1.2
  text ".ProjectBoardNumber" at 226.45,-83.6 h1.2
  text "04-" at 230.2,-83.6 h1.2
  text ".ProjectRevisionART" at 331.928,-85.822 h1.5
  text ".ProjectRevisionART" at 331.928,-85.822 h1.5
  text ".ProjectRevisionART" at 331.928,-85.822 h1.5
  text ".Layer_Name" at 296.75,-86 h1.5
Multi-Layer:
  pour cut-out: 2.3,57 0.05,57 0.05,48 2.3,48
  pour cut-out: 150,27.5 143.85,27.5 143.85,0 150,0
  text "Exported with Altium Designer .Application_BuildNumber on .Print_Date at .Print_Time" at 22,125.9 h1.5

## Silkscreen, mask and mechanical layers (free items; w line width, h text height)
Top Overlay:
  drawing of 3136 lines, arcs and shapes, not listed
  text "'.Layer_Name'" at 0,126 h1.5
  text "Exported with Altium Designer .Application_BuildNumber on .Print_Date at .Print_Time" at 22,125.9 h1.5
  text "Voltage selection" at 124,121.6 h1
  text "JTAG" at 9.75,119.45 h1.5 r90
  text "30" at 64.3,117.5 h1
  text "2" at 100.8,117.4 h1
  text "3" at 125.2,116.8 h1
  text "2" at 127.7,116.8 h1
  text "1" at 130.4,116.8 h1
  text "GND" at 6.4,116.6 h1
  text "12-bit ISI connector" at 77.9,116.5 h1.5
  text "1" at 146.4,116.2 h1 r90
  text "RTS" at 6.4,114 h1
  text "Camera should be facing outside" at 81,112.1 h1
  text "VCC" at 6.4,111.4 h1
  text "EXT_VDD" at 135.4,111 h1 r90
  text "GND" at 138,111 h1 r90
  text "LEFT_P" at 140.8,111 h1 r90
  text "LEFT_N" at 143.1,111 h1 r90
  text "CAN" at 111.4,109.3 h1.5
  text "CLASSD" at 130.9,109.2 h1.5
  text "CAN0_P" at 106.8,109 h1 r90
  text "CAN0_N" at 110.9,109 h1 r90
  text "GND" at 114.4,109 h1 r90
  text "CAN1_P" at 118.4,109 h1 r90
  text "CAN1_N" at 122.3,109 h1 r90
  text "RXD" at 6.4,108.9 h1
  text "MAIN_5V" at 127.8,108.5 h1 r90
  text "EXT_VDD" at 130.6,108.5 h1 r90
  text "TXD" at 6.4,106.3 h1
  text "DEBUG" at 2.35,106.225 h1.5 r90
  text "Force Power UP" at 46.1,105.4 h1 r90
  text "ERASE 3U" at 49.2,105.4 h1 r90
  text "DISABLE JLINK" at 52.5,105.4 h1 r90
  text "DISABLE CDC" at 55.8,105.4 h1 r90
  text "DISABLE BOOT" at 59.1,105.4 h1 r90
  text "VDDBU" at 62.5,105.4 h1 r90
  text "CTS" at 6.4,103.8 h1
  text "DISABLE BOOT" at 43.1,103.8 h1.5
  text "GREEN = BOOT ENABLED" at 41,94.5 h1
  text "RED = BOOT DISABLED" at 43.2,93.1 h1
  text "RPI Connector" at 143.9,77.2 h1.5 r90
  text "*h" at 108.1,76.4 h7
  text "www.segger.com" at 3.957,73.621 h1 r90
  text "J-Link Technology" at 2.557,72.821 h1 r90
  text "SAM9X60-EK" at 113.5,71.5 h2
  text "rev. .ProjectRevisionART" at 128.8,69.3 h1
  text "EVALUATION KIT" at 113.4,69.2 h1
  text "" at 102.5,66.4 h10
  text "SD Card" at 128.8,64.9 h1.5
  text "40" at 149,64.5 h1 r90
  text "" at 101.1,57.7 h10
  text "C" at 100.5,49.8 h10
  text "4 LAYERS" at 3.7,48.6 h1 r90
  text "5V DC" at 2.7,44.9 h1
  text "e" at 68.35,43.1 h10
  text "" at 100.4,36.8 h10
  text "WI-FI/BLE" at 138.7,31.4 h1.5
  text "TXD" at 111.8,26.1 h1
  text "RXD" at 111.8,23.52 h1
  text "USBB" at 54,22.3 h1
  text "GND" at 111.8,20.94 h1
  text "USBC" at 54,20.1 h1
  text "RGB LED" at 87.4,19.2 h1.5
  text "USER PUSH BUTTONS" at 86.169,15.1 h1.5
  text "nRST" at 100.8,13 h1
  text "USER_BTN" at 78.5,12.9 h1
  text "DIS_BOOT" at 109.1,12.9 h1
  text "WAKE_UP" at 89,12.8 h1
  text "USBA" at 36.4,6.5 h1
  text "GND" at 124.79,1.7 h1 r90
  text "SDA" at 137.39,1.7 h1 r90
  text "SCL" at 139.99,1.7 h1 r90
  text "3V3" at 142.59,1.7 h1 r90
  text "GPIO17" at 127.19,0.3 h1 r90
  text "GPIO18" at 129.79,0.3 h1 r90
  text "GPIO19" at 132.29,0.3 h1 r90
  text "GPIO20" at 134.89,0.3 h1 r90
  text ".ProjectRevisionART" at 331.928,-85.822 h1.5
  text ".Layer_Name" at 296.75,-86 h1.5
Bottom Overlay:
  lines w0.1: 25.25,87.15 25.15,87.15 ; 25.3,87 25.3,88.3 25.6,88.6 27.6,88.6 28,89 28,92.1 28.3,92.4 29.5,92.4 29.8,92.1 29.8,89.1 30.2,88.7 32.7,88.7 33.1,88.3 33.1,87.1 32.8,86.8 25.5,86.8 25.15,87.15 ; 74.5,105.6 74.5,118.4 ; 104.2,105.4 104.2,118.4 ; 23.8,85.1 23.8,85.8 25.15,87.15 ; 23.8,85.1 24,84.9 24,83.5 24.2,83.3 25.5,83.3 25.6,83.2 25.6,82.3 25.5,82.2 22.4,82.2 22.1,82.2 22,82.3 22,83.1 22.1,83.2 22.7,83.2 23,83.5 23,84.9 23.2,85.1 23.8,85.1 ; 72,65.7 72.3,65.4 75.6,65.4 75.8,65.6 75.8,67.7 75.8,68.9 75.85,68.95 75.85,70.25 75.5,70.6 73.8,70.6 73.4,70.2 73.4,69 73,68.6 72.3,68.6 72,68.3 72,65.7
  lines w0.2: 57.85,60.1 57.85,66.375 57.85,66.775 58.675,67.6 63.4,67.6 64.1,66.9 64.1,60.1 63.475,59.475 58.475,59.475 57.85,60.1
  text "'.Layer_Name'" at 0,126 h1.5
  text "Exported with Altium Designer .Application_BuildNumber on .Print_Date at .Print_Time" at 22,125.9 h1.5
  text "The LCD should be mounted on top of the board and the ribbon cable should cover the ISI connector" at 103.5,113.9 h1
  text "The LCD interface and the Image Sensor Interface are mutually exclusive" at 103.5,109.4 h1
  text "You can use either one or the other at one time" at 103.5,106 h1
  text ".ProjectRevisionART" at 331.928,-85.822 h1.5
  text ".Layer_Name" at 296.75,-86 h1.5
Top Paste:
  text "'.Layer_Name'" at 0,126 h1.5
  text "Exported with Altium Designer .Application_BuildNumber on .Print_Date at .Print_Time" at 22,125.9 h1.5
  text ".ProjectRevisionART" at 331.928,-85.822 h1.5
  text ".Layer_Name" at 296.75,-86 h1.5
Bottom Paste:
  text "'.Layer_Name'" at 0,126 h1.5
  text "Exported with Altium Designer .Application_BuildNumber on .Print_Date at .Print_Time" at 22,125.9 h1.5
  text ".ProjectRevisionART" at 331.928,-85.822 h1.5
  text ".Layer_Name" at 296.75,-86 h1.5
Top Solder:
  text "'.Layer_Name'" at 0,126 h1.5
  text "Exported with Altium Designer .Application_BuildNumber on .Print_Date at .Print_Time" at 22,125.9 h1.5
  text ".ProjectRevisionART" at 331.928,-85.822 h1.5
  text ".Layer_Name" at 296.75,-86 h1.5
Bottom Solder:
  text "'.Layer_Name'" at 0,126 h1.5
  text "Exported with Altium Designer .Application_BuildNumber on .Print_Date at .Print_Time" at 22,125.9 h1.5
  text ".ProjectName" at 20.8,122.4 h1.5
  text "Rev .ProjectRevisionART" at 20.8,119.9 h1.5
  text ".ProjectRevisionART" at 331.928,-85.822 h1.5
  text ".Layer_Name" at 296.75,-86 h1.5
NOTES (M1):
  text ".Layer_Name" at 314.75,-86 h1.5
BOARD (M2):
  lines w0.1: 0,86.075 0,3 ccw(c3,3) 3,0 147,0 ccw(c147,3) 150,3 150,122 ccw(c147,122) 147,125 3,125 ccw(c3,122) 0,122 0,100.375
  text ".ProjectRevisionART" at 331.928,-85.822 h1.5
  text ".Layer_Name" at 296.75,-86 h1.5
REF POINTS (M3):
  text ".Layer_Name" at 296.75,-86 h1.5
FAB (M4):
  drawing of 380 lines, arcs and shapes, not listed
  text "THIS PCB TO BE MANUFACTURED TO MEET ALL ACCEPTANCE LEVELS FROM CLASS 2:" at 229.339,126.462 h1.78
  text "IPC-6013" at 305.891,122.359 h1.78
  text "IPC-A-600" at 255.415,122.241 h1.78
  text "IPC-6012" at 283.355,122.241 h1.78
  text "STANDARD:" at 229.339,121.902 h1.78
  text "X" at 250.791,121.759 h2.6
  text "X" at 278.731,121.759 h2.6
  text "TG 170-180" at 305.841,117.609 h1.78
  text "TG 130-140" at 283.305,117.491 h1.78
  text "MATERIAL:" at 229.33,117.091 h1.78
  text "FR-4 or Equivalent" at 249.65,117.091 h1.78
  text "X" at 278.681,117.009 h2.6
  text "CONTROLLED IMPEDANCE" at 305.841,112.859 h1.78
  text "MULTILAYER" at 255.365,112.741 h1.78
  text "4" at 278.86,112.741 h1.78
  text "LAYERS" at 283.305,112.741 h1.78
  text "X" at 250.741,112.259 h2.6
  text "X" at 301.541,112.259 h2.6
  text "BURIED VIA" at 305.882,107.918 h1.78
  text "TH VIA" at 255.406,107.8 h1.78
  text "BLIND VIA" at 283.346,107.8 h1.78
  text "X" at 250.782,107.318 h2.6
  text "Cu WEIGHT EXTERNAL LAYERS" at 249.641,102.99 h1.78
  text "35um" at 301.711,102.99 h1.78
  text "FINISHED" at 311.236,102.99 h1.78
  text "35um" at 301.711,98.19 h1.78
  text "Cu WEIGHT INTERNAL LAYERS" at 249.641,98.14 h1.78
  text "FINISHED" at 311.236,98.14 h1.78
  text "FINISHED OVERALL THICKNESS" at 249.641,93.29 h1.78
  text "1.6" at 302.981,93.29 h1.78
  text "mm" at 311.236,93.29 h1.78
  text "10" at 325.841,93.29 h1.78
  text "%" at 334.096,93.29 h1.78
  text "PCB OUTLINE WIDTH" at 249.641,88.29 h1.78
  text "150" at 302.981,88.29 h1.78
  text "mm" at 311.236,88.29 h1.78
  text "0.1" at 325.841,88.29 h1.78
  text "mm" at 334.096,88.29 h1.78
  text "PCB OUTLINE HEIGHT" at 249.641,83.29 h1.78
  text "125" at 302.981,83.29 h1.78
  text "mm" at 311.236,83.29 h1.78
  text "0.1" at 325.841,83.29 h1.78
  text "mm" at 334.096,83.29 h1.78
  text "COPPER THIEVING ALLOWED" at 249.832,78.458 h1.78
  text "YES" at 306.832,78.458 h1.78
  text "NO" at 323.832,78.458 h1.78
  text "X" at 318.423,77.958 h2.6
  text "FINISH:" at 229.332,73.208 h1.78
  text "ENIG" at 255.332,72.908 h1.78
  text "X" at 250.632,72.288 h2.6
  text "IMMERSION SILVER" at 255.356,67.37 h1.78
  text "IMMERSION TIN" at 255.356,61.87 h1.78
  text "SMOBC WITH SELECTIVE GOLD PLATING ON LANDS" at 255.356,58.165 h1.78
  text "INDICATED. 1um GOLD OVER 5-10 um NICKEL" at 255.356,54.355 h1.78
  text "SOLDERMASK" at 249.641,47.52 h1.78
  text "IPC-SM-840 Class T" at 271.231,47.52 h1.78
  text "SOLDERMASK COLOR" at 249.641,41.17 h1.78
  text "GREEN HIGH GLOSS" at 281.391,41.17 h1.78
  text "SILKSCREEN COLOR" at 249.641,34.82 h1.78
  text "WHITE" at 281.391,34.82 h1.78
  text "ALL HOLES TO BE LOCATED BY THE COORDINATES FROM THE NC DRILL DATA PROVIDED." at 229.321,28.47 h1.78
  text "PCB REV" at 297.332,22.208 h1.78
  text ".ProjectRevisionART" at 310.925,22.175 h1.78
  text "USE ARTWORK SET NO." at 229.321,22.12 h1.78
  text "'.ProjectPartNumber'" at 260.875,22.1 h1.78
  text "ALL UL LOGO, MANUFACTURER'S ID, AND DATE CODES SHALL BE PLACED" at 229.321,15.77 h1.78
  text "ON THE BOTTOM SIDE UNLESS OTHERWISE INDICATED." at 229.321,11.96 h1.78
  text "ANY ALTERNATIVES TO THE ABOVE SPECIFICATIONS MUST FIRST BE APPROVED." at 228.832,6.708 h1.78
  text "Layer" at -13.775,-22.075 h1.5
  text "Name" at -5.269,-22.075 h1.5
  text "Material" at 18.32,-22.075 h1.5
  text "Thickness" at 34.681,-22.075 h1.5
  text "Constant" at 47.408,-22.075 h1.5
  text "Board Layer Stack" at 59.527,-22.075 h1.5
  text "Top Overlay" at -5.269,-25.075 h1.5
  text "THIS BOARD CONTAINS CONTROLLED IMPEDANCE TRACKS, TRACK AND GAP SIZES ARE AS FOLLOWS:" at 88.5,-25.9 h1.5
  text "Top Solder" at -5.269,-28.075 h1.5
  text "Solder Resist" at 18.32,-28.075 h1.5
  text "0.020mm" at 34.681,-28.075 h1.5
  text "3.5" at 47.408,-28.075 h1.5
  text "TYPE;" at 88.5,-30.9 h1.5
  text "Impedance;" at 100,-30.9 h1.5
  text "Tolerance;" at 117.5,-30.9 h1.5
  text "Layer;" at 134.5,-30.9 h1.5
  text "Reference;" at 146.5,-30.9 h1.5
  text "Width (um);" at 163.5,-30.9 h1.5
  text "Gap (um);" at 183.5,-30.9 h1.5
  text "1" at -13.775,-31.075 h1.5
  text "L1 - Top Layer" at -5.269,-31.075 h1.5
  text "Copper" at 18.32,-31.075 h1.5
  text "0.035mm" at 34.681,-31.075 h1.5
  text "Dielectric 1" at -5.269,-34.075 h1.5
  text "0.090mm" at 34.681,-34.075 h1.5
  text "4.2" at 47.408,-34.075 h1.5
  text "DIFF;" at 88.5,-35.4 h1.5
  text "90ohm;" at 100,-35.4 h1.5
  text "+/- 10%;" at 117.5,-35.4 h1.5
  text "L1;" at 134.5,-35.4 h1.5
  text "L2;" at 146.5,-35.4 h1.5
  text "125;" at 163.5,-35.4 h1.5
  text "200;" at 183.5,-35.4 h1.5
  text "2" at -13.775,-37.075 h1.5
  text "L2 - GND" at -5.269,-37.075 h1.5
  text "Copper" at 18.32,-37.075 h1.5
  text "0.035mm" at 34.681,-37.075 h1.5
  text "DIFF;" at 88.5,-37.9 h1.5
  text "90ohm;" at 100,-37.9 h1.5
  text "+/- 10%;" at 117.5,-37.9 h1.5
  text "L4;" at 134.5,-37.9 h1.5
  text "L3;" at 146.5,-37.9 h1.5
  text "125;" at 163.5,-37.9 h1.5
  text "200;" at 183.5,-37.9 h1.5
  text "Dielectric 2" at -5.269,-40.075 h1.5
  text "FR-4" at 18.32,-40.075 h1.5
  text "1.200mm" at 34.681,-40.075 h1.5
  text "4.2" at 47.408,-40.075 h1.5
  text "DIFF;" at 88.5,-41.4 h1.5
  text "100ohm;" at 100,-41.4 h1.5
  text "+/- 10%;" at 117.5,-41.4 h1.5
  text "L1;" at 134.5,-41.4 h1.5
  text "L2;" at 146.5,-41.4 h1.5
  text "100;" at 163.5,-41.4 h1.5
  text "200;" at 183.5,-41.4 h1.5
  text "3" at -13.775,-43.075 h1.5
  text "L3 - PWR" at -5.269,-43.075 h1.5
  text "Copper" at 18.32,-43.075 h1.5
  text "0.035mm" at 34.681,-43.075 h1.5
  text "DIFF;" at 88.5,-43.9 h1.5
  text "100ohm;" at 100,-43.9 h1.5
  text "+/- 10%;" at 117.5,-43.9 h1.5
  text "L4;" at 134.5,-43.9 h1.5
  text "L3;" at 146.5,-43.9 h1.5
  text "100;" at 163.5,-43.9 h1.5
  text "200;" at 183.5,-43.9 h1.5
  text "Dielectric 3" at -5.269,-46.075 h1.5
  text "0.090mm" at 34.681,-46.075 h1.5
  text "4.2" at 47.408,-46.075 h1.5
  text "SE;" at 88.5,-47.4 h1.5
  text "50ohm;" at 100,-47.4 h1.5
  text "+/- 10%;" at 117.5,-47.4 h1.5
  text "L1;" at 134.5,-47.4 h1.5
  text "L2;" at 146.5,-47.4 h1.5
  text "125;" at 163.5,-47.4 h1.5
  text "4" at -13.775,-49.075 h1.5
  text "L4 - Bottom Layer" at -5.269,-49.075 h1.5
  text "Copper" at 18.32,-49.075 h1.5
  text "0.035mm" at 34.681,-49.075 h1.5
  text "SE;" at 88.5,-49.9 h1.5
  text "50ohm;" at 100,-49.9 h1.5
  text "+/- 10%;" at 117.5,-49.9 h1.5
  text "L4;" at 134.5,-49.9 h1.5
  text "L3;" at 146.5,-49.9 h1.5
  text "125;" at 163.5,-49.9 h1.5
  text "Bottom Solder" at -5.269,-52.075 h1.5
  text "Solder Resist" at 18.32,-52.075 h1.5
  text "0.020mm" at 34.681,-52.075 h1.5
  text "3.5" at 47.408,-52.075 h1.5
  text "Bottom Overlay" at -5.269,-55.075 h1.5
  text ".ProjectRevisionFAB" at 331.928,-85.822 h1.5
  text ".Layer_Name" at 296.75,-86 h1.5
Case (M5):
  text ".Layer_Name" at 296.75,-86 h1.5
Cover (M6):
  text ".Layer_Name" at 296.75,-86 h1.5
Terminal Block (M7):
  text ".Layer_Name" at 296.75,-86 h1.5
Route Tool Path:
  text ".Layer_Name" at 296.75,-86 h1.5
V-Cut (M9):
  text ".Layer_Name" at 296.75,-86 h1.5
Assy BOT (M10):
  text ".variantName" at 46.32,-70 h0.9
  text "ASSEMBLY VARIANT:" at 60.57,-70 h0.9
  text "DOCUMENT NUMBER:" at 14.3,-78.25 h1.14
  text "-D" at 0.3,-81.25 h1.78
  text ".ProjectBoardNumber" at 8.55,-81.25 h1.78
  text "02-" at 14.05,-81.25 h1.78
  text ".ProjectRevisionASSY" at -2.628,-85.822 h1.5
  text ".Layer_Name" at 32.25,-86 h1.5
Assy TOP (M11):
  text "ASSEMBLY VARIANT:" at 268.75,-70 h0.9
  text ".variantName" at 283,-70 h0.9
  text "DOCUMENT NUMBER:" at 315,-78.25 h1.14
  text "02-" at 315.25,-81.25 h1.78
  text ".ProjectBoardNumber" at 320.75,-81.25 h1.78
  text "-D" at 329,-81.25 h1.78
  text ".ProjectRevisionASSY" at 331.928,-85.822 h1.5
  text ".Layer_Name" at 296.75,-86 h1.5
3D BOT (M12):
  text ".Layer_Name" at 296.75,-86 h1.5
3D TOP (M13):
  text ".Layer_Name" at 296.75,-86 h1.5
Guard BOT (M14):
  text ".ProjectRevisionART" at 331.928,-85.822 h1.5
  text ".Layer_Name" at 296.75,-86 h1.5
Guard TOP (M15):
  text ".ProjectRevisionART" at 331.928,-85.822 h1.5
  text ".Layer_Name" at 296.75,-86 h1.5
TITLE (M16):
  lines w0.1: 268.25,-68.75 350.07,-68.75 ; 325.25,-61.25 325.25,-64.25 350.07,-64.25 ; 338.79,-85.885 338.79,-84.615 ; 338.79,-85.25 348.95,-85.25 ; 338.95,-84.05 338.95,-83.05 ; 338.95,-83.55 348.95,-83.55 ; 341.33,-85.885 341.33,-84.615 ; 343.87,-85.885 343.87,-84.615 ; 343.95,-83.85 343.95,-83.25 ; 346.41,-85.885 346.41,-84.615 ; 348.95,-85.885 348.95,-84.615 ; 348.95,-84.05 348.95,-83.05
  lines w0.127: -25.85,-31.425 -20.77,-31.425 ; -25.85,28.9 -20.77,28.9 ; -25.85,89.225 -20.77,89.225 ; 37.65,-91.75 37.65,-86.67 ; 37.65,144.47 37.65,149.55 ; 101.15,-91.75 101.15,-86.67 ; 101.15,144.47 101.15,149.55 ; 164.65,-91.75 164.65,-86.67 ; 164.65,144.47 164.65,149.55 ; 200.21,-86.67 235.77,-86.67 ; 228.15,-91.75 228.15,-86.67 ; 228.15,144.47 228.15,149.55 ; 234.25,-86.67 234.25,-61.25 350.07,-61.25 ; 268.25,-86.67 268.25,-61.25 ; 268.25,-82.25 350.07,-82.25 ; 268.25,-76.25 350.07,-76.25 ; 268.25,-70.25 350.07,-70.25 ; 291.65,-91.75 291.65,-86.67 ; 291.65,144.47 291.65,149.55 ; 296.25,-86.67 296.25,-70.25 ; 319.525,-82.25 319.525,-76.25 ; 327.25,-86.67 327.25,-82.25 ; 334.75,-86.67 334.75,-76.25 ; 350.07,-56.19 350.07,-86.67 ; 350.07,-31.425 355.15,-31.425 ; 350.07,28.9 355.15,28.9 ; 350.07,89.225 355.15,89.225 ; 350.07,-86.67 350.07,144.47 -20.77,144.47 -20.77,-86.67 350.07,-86.67 ; -25.85,-91.75 -25.85,149.55 355.15,149.55 355.15,-91.75 -25.85,-91.75
  lines w0.254: 228.25,144.25 228.25,139.75 ; 239.25,135.25 239.25,139.75 239.25,144.25 ; 251.75,135.25 251.75,139.75 251.75,144.25 ; 330.25,135.25 330.25,139.75 330.25,144.25 ; 349.75,135.25 228.25,135.25 228.25,139.75 ; 349.75,139.75 228.25,139.75
  text "1" at 5.426,146.248 h1.78
  text "2" at 68.816,146.248 h1.78
  text "3" at 132.045,146.248 h1.78
  text "4" at 195.714,146.248 h1.78
  text "5" at 259.189,146.248 h1.78
  text "6" at 322.816,146.248 h1.78
  text "REV" at 230.75,141.25 h1.52
  text "ECO" at 240.75,141.25 h1.52
  text "Comments" at 287.25,140.75 h1.52
  text "Date" at 335.25,140.75 h1.52
  text "A" at -23.945,117.216 h1.78
  text "A" at 351.975,117.216 h1.78
  text "B" at -23.945,56.764 h1.78
  text "B" at 351.975,56.764 h1.78
  text "C" at -23.945,-3.561 h1.78
  text "C" at 351.975,-3.561 h1.78
  text "PART NUMBER:" at 325.55,-63.325 h1
  text ".ProjectpartNumber" at 336.075,-63.625 h1.5
  text "D" at -23.945,-63.759 h1.78
  text "TITLE:" at 269.25,-63.75 h1.14
  text "D" at 351.975,-63.759 h1.78
  text ".ProjectTitle" at 269.25,-67.75 h2.5
  text "PCB DESIGNER:" at 269.25,-72.25 h1.14
  text "GERBER FILE:" at 297.25,-72.25 h1.14
  text ".ProjectDrawnBy" at 269.25,-75.25 h1.78
  text ".Plot_File_Name" at 297.25,-75.25 h1.5
  text "M" at 237.25,-77.25 h15.24
  text "ENGINEER:" at 269.25,-78.25 h1.14
  text "BOARD NUMBER:" at 297.25,-78.25 h1.14
  text "DATE:" at 335.95,-78.25 h1.14
  text "Microchip Technology Inc." at 236.02,-80.51 h1.78
  text ".ProjectEngineer" at 269.25,-81.25 h1.78
  text "04-" at 297.25,-81.25 h1.78
  text ".ProjectBoardNumber" at 302.25,-81.25 h1.78
  text ".PRINT_DATE" at 335.95,-81.25 h1.5
  text "2355 W. Chandler Blvd." at 237.25,-83.25 h1.78
  text "LAYER NAME:" at 297.25,-83.75 h1.14
  text "10mm" at 335.25,-83.85 h0.7
  text "PCB FILE NAME:" at 269.25,-84 h1.14
  text "REV:" at 328,-84 h1.14
  text "400mil" at 335.15,-85.55 h0.7
  text "Chandler, AZ  85224" at 238.25,-85.75 h1.78
  text ".PCB_FILE_NAME_NO_PATH" at 269.25,-86 h1.14
  text "1" at 5.426,-89.972 h1.78
  text "2" at 68.816,-89.972 h1.78
  text "3" at 132.045,-89.972 h1.78
  text "4" at 195.714,-89.972 h1.78
  text "5" at 259.189,-89.972 h1.78
  text "6" at 322.816,-89.972 h1.78
Drill Drawing:
  drawing of 185 lines, arcs and shapes, not listed
  text "Symbol" at 230.625,1.9 h1.2
  text "Hit Count" at 238.038,1.9 h1.2
  text "Finished Hole Size" at 247.542,1.9 h1.2
  text "Hole Tolerance" at 264.125,1.9 h1.2
  text "Plated" at 277.503,1.9 h1.2
  text "Hole Type" at 283.904,1.9 h1.2
  text "Hole Length" at 293.511,1.9 h1.2
  text "Routed Path Length" at 304.569,1.9 h1.2
  text "1" at 238.038,-0.6 h1
  text "1.00mm" at 247.542,-0.6 h1
  text "PTH" at 277.503,-0.6 h1
  text "Slot" at 283.904,-0.6 h1
  text "3.50mm" at 293.511,-0.6 h1
  text "2.50mm" at 304.569,-0.6 h1
  text "2" at 238.038,-3.1 h1
  text "1.00mm" at 247.542,-3.1 h1
  text "PTH" at 277.503,-3.1 h1
  text "Slot" at 283.904,-3.1 h1
  text "3.00mm" at 293.511,-3.1 h1
  text "2.00mm" at 304.569,-3.1 h1
  text "2" at 238.038,-5.6 h1
  text "1.50mm" at 247.542,-5.6 h1
  text "+/-0.05mm" at 264.125,-5.6 h1
  text "NPTH" at 277.503,-5.6 h1
  text "Round" at 283.904,-5.6 h1
  text "-" at 293.511,-5.6 h1
  text "-" at 304.569,-5.6 h1
  text "3" at 238.038,-8.1 h1
  text "1.60mm" at 247.542,-8.1 h1
  text "PTH" at 277.503,-8.1 h1
  text "Round" at 283.904,-8.1 h1
  text "-" at 293.511,-8.1 h1
  text "-" at 304.569,-8.1 h1
  text "4" at 238.038,-10.6 h1
  text "0.85mm" at 247.542,-10.6 h1
  text "PTH" at 277.503,-10.6 h1
  text "Round" at 283.904,-10.6 h1
  text "-" at 293.511,-10.6 h1
  text "-" at 304.569,-10.6 h1
  text "4" at 238.038,-13.1 h1
  text "1.15mm" at 247.542,-13.1 h1
  text "PTH" at 277.503,-13.1 h1
  text "Round" at 283.904,-13.1 h1
  text "-" at 293.511,-13.1 h1
  text "-" at 304.569,-13.1 h1
  text "B" at 230.186,-13.2 h1.11
  text "4" at 238.038,-15.6 h1
  text "2.30mm" at 247.542,-15.6 h1
  text "PTH" at 277.503,-15.6 h1
  text "Round" at 283.904,-15.6 h1
  text "-" at 293.511,-15.6 h1
  text "-" at 304.569,-15.6 h1
  text "4" at 238.038,-18.1 h1
  text "3.20mm" at 247.542,-18.1 h1
  text "+/-0.05mm" at 264.125,-18.1 h1
  text "NPTH" at 277.503,-18.1 h1
  text "Round" at 283.904,-18.1 h1
  text "-" at 293.511,-18.1 h1
  text "-" at 304.569,-18.1 h1
  text "5" at 238.038,-20.6 h1
  text "0.30mm" at 247.542,-20.6 h1
  text "PTH" at 277.503,-20.6 h1
  text "Round" at 283.904,-20.6 h1
  text "-" at 293.511,-20.6 h1
  text "-" at 304.569,-20.6 h1
  text "6" at 238.038,-23.1 h1
  text "0.75mm" at 247.542,-23.1 h1
  text "PTH" at 277.503,-23.1 h1
  text "Round" at 283.904,-23.1 h1
  text "-" at 293.511,-23.1 h1
  text "-" at 304.569,-23.1 h1
  text "H" at 230.186,-23.2 h1.11
  text "6" at 238.038,-25.6 h1
  text "3.20mm" at 247.542,-25.6 h1
  text "NPTH" at 277.503,-25.6 h1
  text "Round" at 283.904,-25.6 h1
  text "-" at 293.511,-25.6 h1
  text "-" at 304.569,-25.6 h1
  text "9" at 238.038,-28.1 h1
  text "1.10mm" at 247.542,-28.1 h1
  text "PTH" at 277.503,-28.1 h1
  text "Round" at 283.904,-28.1 h1
  text "-" at 293.511,-28.1 h1
  text "-" at 304.569,-28.1 h1
  text "12" at 238.038,-30.6 h1
  text "1.00mm" at 247.542,-30.6 h1
  text "PTH" at 277.503,-30.6 h1
  text "Round" at 283.904,-30.6 h1
  text "-" at 293.511,-30.6 h1
  text "-" at 304.569,-30.6 h1
  text "16" at 238.038,-33.1 h1
  text "0.30mm" at 247.542,-33.1 h1
  text "PTH" at 277.503,-33.1 h1
  text "Round" at 283.904,-33.1 h1
  text "-" at 293.511,-33.1 h1
  text "-" at 304.569,-33.1 h1
  text "C" at 230.186,-33.2 h1.11
  text "16" at 238.038,-35.6 h1
  text "0.89mm" at 247.542,-35.6 h1
  text "PTH" at 277.503,-35.6 h1
  text "Round" at 283.904,-35.6 h1
  text "-" at 293.511,-35.6 h1
  text "-" at 304.569,-35.6 h1
  text "20" at 238.038,-38.1 h1
  text "1.07mm" at 247.542,-38.1 h1
  text "PTH" at 277.503,-38.1 h1
  text "Round" at 283.904,-38.1 h1
  text "-" at 293.511,-38.1 h1
  text "-" at 304.569,-38.1 h1
  text "A" at 230.186,-38.2 h1.11
  text "110" at 238.038,-40.6 h1
  text "0.90mm" at 247.542,-40.6 h1
  text "PTH" at 277.503,-40.6 h1
  text "Round" at 283.904,-40.6 h1
  text "-" at 293.511,-40.6 h1
  text "-" at 304.569,-40.6 h1
  text "121" at 238.038,-43.1 h1
  text "0.15mm" at 247.542,-43.1 h1
  text "PTH" at 277.503,-43.1 h1
  text "Round" at 283.904,-43.1 h1
  text "-" at 293.511,-43.1 h1
  text "-" at 304.569,-43.1 h1
  text "896" at 238.038,-45.6 h1
  text "0.20mm" at 247.542,-45.6 h1
  text "PTH" at 277.503,-45.6 h1
  text "Round" at 283.904,-45.6 h1
  text "-" at 293.511,-45.6 h1
  text "-" at 304.569,-45.6 h1
  text "1241 Total" at 238.038,-48.1 h1
  text "Slot definitions :" at 230.625,-50.383 h1
  text "Routed Path Length" at 242.696,-50.383 h1
  text "= Calculated from tool start centre position to tool end centre position." at 257.132,-50.383 h1
  text "Hole Length" at 242.696,-51.916 h1
  text "= Routed Path Length + Tool Size = Slot length as defined in the PCB layout" at 251.424,-51.916 h1
  text "DOCUMENT NUMBER:" at 315,-78.25 h1.14
  text "04-" at 315.25,-81.25 h1.78
  text ".ProjectBoardNumber" at 320.75,-81.25 h1.78
  text "-D" at 329,-81.25 h1.78
  text ".ProjectRevisionFAB" at 331.928,-85.822 h1.5
TITLE MIRROR (M17):
  lines w0.1: -20.75,-68.75 61.07,-68.75 ; -20.75,-64.25 4.07,-64.25 4.07,-61.25 ; -19.65,-85.885 -19.65,-84.615 ; -19.65,-85.25 -9.49,-85.25 ; -19.65,-84.05 -19.65,-83.05 ; -19.65,-83.55 -9.65,-83.55 ; -17.11,-85.885 -17.11,-84.615 ; -14.65,-83.85 -14.65,-83.25 ; -14.57,-85.885 -14.57,-84.615 ; -12.03,-85.885 -12.03,-84.615 ; -9.65,-84.05 -9.65,-83.05 ; -9.49,-85.885 -9.49,-84.615
  lines w0.127: -25.85,-31.425 -20.77,-31.425 ; -25.85,28.9 -20.77,28.9 ; -25.85,89.225 -20.77,89.225 ; -20.77,-82.25 61.05,-82.25 ; -20.77,-76.25 61.05,-76.25 ; -20.75,-70.25 61.07,-70.25 ; -20.75,-61.25 95.07,-61.25 95.07,-86.67 ; -5.45,-86.67 -5.45,-76.25 ; 2.05,-86.67 2.05,-82.25 ; 15.05,-82.25 15.05,-76.25 ; 33.07,-86.67 33.07,-70.25 ; 37.65,-91.75 37.65,-86.67 ; 37.65,144.47 37.65,149.55 ; 61.07,-86.67 61.07,-61.25 ; 101.15,-91.75 101.15,-86.67 ; 101.15,144.47 101.15,149.55 ; 164.65,-91.75 164.65,-86.67 ; 164.65,144.47 164.65,149.55 ; 228.15,-91.75 228.15,-86.67 ; 228.15,144.47 228.15,149.55 ; 291.65,-91.75 291.65,-86.67 ; 291.65,144.47 291.65,149.55 ; 350.07,-31.425 355.15,-31.425 ; 350.07,28.9 355.15,28.9 ; 350.07,89.225 355.15,89.225 ; -25.85,-91.75 355.15,-91.75 355.15,149.55 -25.85,149.55 -25.85,-91.75 ; -20.77,-86.67 350.07,-86.67 350.07,144.47 -20.77,144.47 -20.77,-86.67
  text "6" at 6.484,146.248 h1.78
  text "5" at 70.111,146.248 h1.78
  text "4" at 133.586,146.248 h1.78
  text "3" at 197.255,146.248 h1.78
  text "2" at 260.484,146.248 h1.78
  text "1" at 323.874,146.248 h1.78
  text "A" at -22.675,117.216 h1.78
  text "A" at 353.245,117.216 h1.78
  text "B" at -22.675,56.764 h1.78
  text "B" at 353.245,56.764 h1.78
  text "C" at -22.675,-3.561 h1.78
  text "C" at 353.245,-3.561 h1.78
  text "PART NUMBER:" at 3.07,-63.25 h1
  text "TITLE:" at 60.07,-63.25 h1.14
  text ".ProjectpartNumber" at -8.93,-63.5 h1.5
  text "D" at -22.675,-63.759 h1.78
  text "D" at 353.245,-63.759 h1.78
  text ".ProjectTitle" at 60.07,-67.75 h2.5
  text "GERBER FILE:" at 32.07,-72.25 h1.14
  text "PCB DESIGNER:" at 60.07,-72.25 h1.14
  text ".Plot_File_Name" at 32.07,-75.25 h1.5
  text ".ProjectDrawnBy" at 60.07,-75.25 h1.78
  text "M" at 92.07,-77.25 h15.24
  text "DATE:" at -6.65,-78.25 h1.14
  text "BOARD NUMBER:" at 32.05,-78.25 h1.14
  text "ENGINEER:" at 60.05,-78.25 h1.14
  text "Microchip Technology Inc." at 93.3,-80.51 h1.78
  text ".PRINT_DATE" at -6.65,-81.25 h1.5
  text ".ProjectBoardNumber" at 27.05,-81.25 h1.78
  text "04-" at 32.05,-81.25 h1.78
  text ".ProjectEngineer" at 60.05,-81.25 h1.78
  text "2355 W. Chandler Blvd." at 92.07,-83.25 h1.78
  text "LAYER NAME:" at 32.05,-83.75 h1.14
  text "10mm" at -5.95,-83.85 h0.7
  text "REV:" at 1.3,-84 h1.14
  text "PCB FILE NAME:" at 60.05,-84 h1.14
  text "400mil" at -5.85,-85.55 h0.7
  text "Chandler, AZ  85224" at 91.07,-85.75 h1.78
  text ".PCB_FILE_NAME_NO_PATH" at 60.05,-86 h1.14
  text "6" at 6.484,-89.972 h1.78
  text "5" at 70.111,-89.972 h1.78
  text "4" at 133.586,-89.972 h1.78
  text "3" at 197.255,-89.972 h1.78
  text "2" at 260.484,-89.972 h1.78
  text "1" at 323.874,-89.972 h1.78

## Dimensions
150,-0.7 to 0,0 on FAB (M4)
150.4,0 to 150.8,125 on FAB (M4)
